VERSION 5.7 ;
  NOWIREEXTENSIONATPIN ON ;
  DIVIDERCHAR "/" ;
  BUSBITCHARS "[]" ;
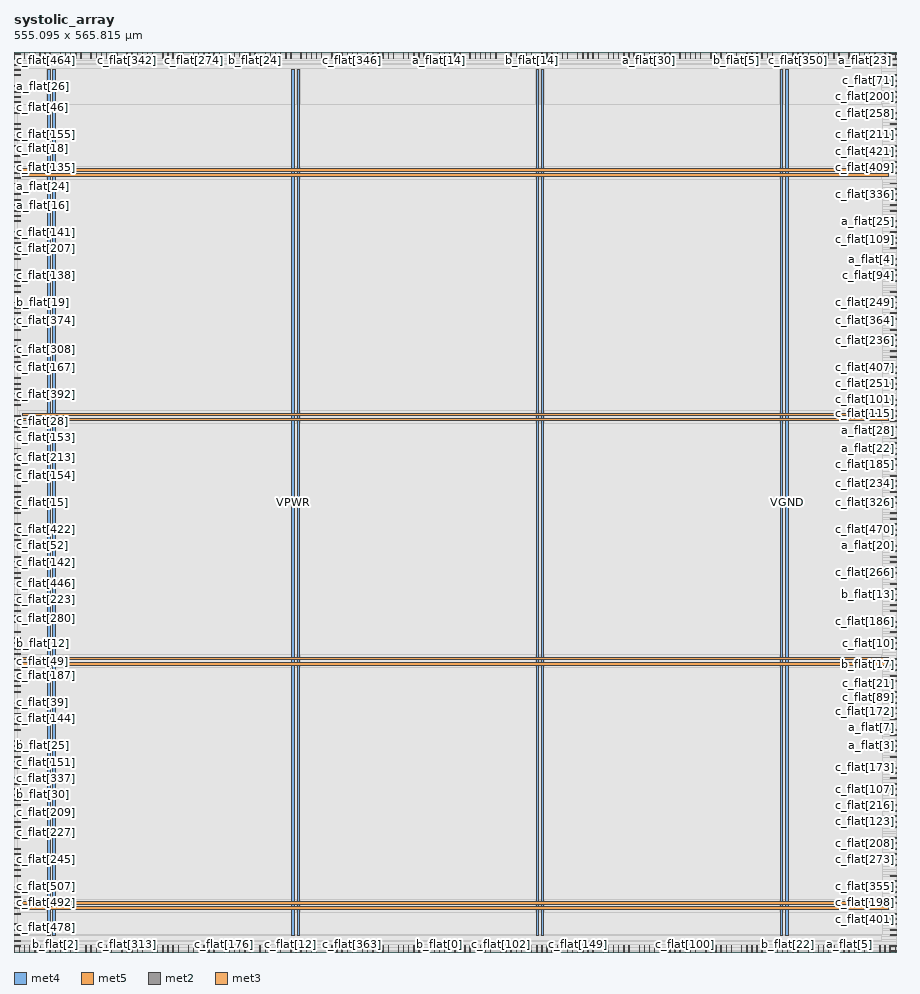
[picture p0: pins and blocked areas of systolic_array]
MACRO systolic_array
  CLASS BLOCK ;
  FOREIGN systolic_array ;
  ORIGIN 0.000 0.000 ;
  SIZE 555.095 BY 565.815 ;
  PIN VGND
    DIRECTION INOUT ;
    USE GROUND ;
    PORT
      LAYER met4 ;
        RECT 24.340 10.640 25.940 555.120 ;
    END
    PORT
      LAYER met4 ;
        RECT 177.940 10.640 179.540 555.120 ;
    END
    PORT
      LAYER met4 ;
        RECT 331.540 10.640 333.140 555.120 ;
    END
    PORT
      LAYER met4 ;
        RECT 485.140 10.640 486.740 555.120 ;
    END
    PORT
      LAYER met5 ;
        RECT 5.280 30.030 549.480 31.630 ;
    END
    PORT
      LAYER met5 ;
        RECT 5.280 183.630 549.480 185.230 ;
    END
    PORT
      LAYER met5 ;
        RECT 5.280 337.230 549.480 338.830 ;
    END
    PORT
      LAYER met5 ;
        RECT 5.280 490.830 549.480 492.430 ;
    END
  END VGND
  PIN VPWR
    DIRECTION INOUT ;
    USE POWER ;
    PORT
      LAYER met4 ;
        RECT 21.040 10.640 22.640 555.120 ;
    END
    PORT
      LAYER met4 ;
        RECT 174.640 10.640 176.240 555.120 ;
    END
    PORT
      LAYER met4 ;
        RECT 328.240 10.640 329.840 555.120 ;
    END
    PORT
      LAYER met4 ;
        RECT 481.840 10.640 483.440 555.120 ;
    END
    PORT
      LAYER met5 ;
        RECT 5.280 26.730 549.480 28.330 ;
    END
    PORT
      LAYER met5 ;
        RECT 5.280 180.330 549.480 181.930 ;
    END
    PORT
      LAYER met5 ;
        RECT 5.280 333.930 549.480 335.530 ;
    END
    PORT
      LAYER met5 ;
        RECT 5.280 487.530 549.480 489.130 ;
    END
  END VPWR
  PIN a_flat[0]
    DIRECTION INPUT ;
    USE SIGNAL ;
    ANTENNAGATEAREA 0.860700 ;
    ANTENNADIFFAREA 0.434700 ;
    PORT
      LAYER met2 ;
        RECT 228.710 0.000 228.990 4.000 ;
    END
  END a_flat[0]
  PIN a_flat[10]
    DIRECTION INPUT ;
    USE SIGNAL ;
    ANTENNAGATEAREA 0.647700 ;
    ANTENNADIFFAREA 0.434700 ;
    PORT
      LAYER met3 ;
        RECT 0.000 95.240 4.000 95.840 ;
    END
  END a_flat[10]
  PIN a_flat[11]
    DIRECTION INPUT ;
    USE SIGNAL ;
    ANTENNAGATEAREA 0.682200 ;
    ANTENNADIFFAREA 0.434700 ;
    PORT
      LAYER met3 ;
        RECT 551.095 319.640 555.095 320.240 ;
    END
  END a_flat[11]
  PIN a_flat[12]
    DIRECTION INPUT ;
    USE SIGNAL ;
    ANTENNAGATEAREA 0.682200 ;
    ANTENNADIFFAREA 0.434700 ;
    PORT
      LAYER met2 ;
        RECT 383.270 0.000 383.550 4.000 ;
    END
  END a_flat[12]
  PIN a_flat[13]
    DIRECTION INPUT ;
    USE SIGNAL ;
    ANTENNAGATEAREA 0.631200 ;
    ANTENNADIFFAREA 0.434700 ;
    PORT
      LAYER met2 ;
        RECT 238.370 561.815 238.650 565.815 ;
    END
  END a_flat[13]
  PIN a_flat[14]
    DIRECTION INPUT ;
    USE SIGNAL ;
    ANTENNAGATEAREA 0.631200 ;
    ANTENNADIFFAREA 0.434700 ;
    PORT
      LAYER met2 ;
        RECT 267.350 561.815 267.630 565.815 ;
    END
  END a_flat[14]
  PIN a_flat[15]
    DIRECTION INPUT ;
    USE SIGNAL ;
    ANTENNAGATEAREA 0.647700 ;
    ANTENNADIFFAREA 0.434700 ;
    PORT
      LAYER met3 ;
        RECT 551.095 353.640 555.095 354.240 ;
    END
  END a_flat[15]
  PIN a_flat[16]
    DIRECTION INPUT ;
    USE SIGNAL ;
    ANTENNAGATEAREA 0.593700 ;
    ANTENNADIFFAREA 0.434700 ;
    PORT
      LAYER met3 ;
        RECT 0.000 469.240 4.000 469.840 ;
    END
  END a_flat[16]
  PIN a_flat[17]
    DIRECTION INPUT ;
    USE SIGNAL ;
    ANTENNAGATEAREA 0.631200 ;
    ANTENNADIFFAREA 0.434700 ;
    PORT
      LAYER met2 ;
        RECT 409.030 561.815 409.310 565.815 ;
    END
  END a_flat[17]
  PIN a_flat[18]
    DIRECTION INPUT ;
    USE SIGNAL ;
    ANTENNAGATEAREA 0.647700 ;
    ANTENNADIFFAREA 0.434700 ;
    PORT
      LAYER met3 ;
        RECT 551.095 561.040 555.095 561.640 ;
    END
  END a_flat[18]
  PIN a_flat[19]
    DIRECTION INPUT ;
    USE SIGNAL ;
    ANTENNAGATEAREA 0.631200 ;
    ANTENNADIFFAREA 0.434700 ;
    PORT
      LAYER met3 ;
        RECT 551.095 448.840 555.095 449.440 ;
    END
  END a_flat[19]
  PIN a_flat[1]
    DIRECTION INPUT ;
    USE SIGNAL ;
    ANTENNAGATEAREA 0.647700 ;
    ANTENNADIFFAREA 0.434700 ;
    PORT
      LAYER met3 ;
        RECT 551.095 550.840 555.095 551.440 ;
    END
  END a_flat[1]
  PIN a_flat[20]
    DIRECTION INPUT ;
    USE SIGNAL ;
    ANTENNAGATEAREA 0.631200 ;
    ANTENNADIFFAREA 0.434700 ;
    PORT
      LAYER met3 ;
        RECT 551.095 255.040 555.095 255.640 ;
    END
  END a_flat[20]
  PIN a_flat[21]
    DIRECTION INPUT ;
    USE SIGNAL ;
    ANTENNAGATEAREA 0.647700 ;
    ANTENNADIFFAREA 0.434700 ;
    PORT
      LAYER met2 ;
        RECT 489.530 561.815 489.810 565.815 ;
    END
  END a_flat[21]
  PIN a_flat[22]
    DIRECTION INPUT ;
    USE SIGNAL ;
    ANTENNAGATEAREA 0.631200 ;
    ANTENNADIFFAREA 0.434700 ;
    PORT
      LAYER met3 ;
        RECT 551.095 316.240 555.095 316.840 ;
    END
  END a_flat[22]
  PIN a_flat[23]
    DIRECTION INPUT ;
    USE SIGNAL ;
    ANTENNAGATEAREA 0.647700 ;
    ANTENNADIFFAREA 0.434700 ;
    PORT
      LAYER met2 ;
        RECT 534.610 561.815 534.890 565.815 ;
    END
  END a_flat[23]
  PIN a_flat[24]
    DIRECTION INPUT ;
    USE SIGNAL ;
    ANTENNAGATEAREA 0.593700 ;
    ANTENNADIFFAREA 0.434700 ;
    PORT
      LAYER met3 ;
        RECT 0.000 476.040 4.000 476.640 ;
    END
  END a_flat[24]
  PIN a_flat[25]
    DIRECTION INPUT ;
    USE SIGNAL ;
    ANTENNAGATEAREA 0.647700 ;
    ANTENNADIFFAREA 0.434700 ;
    PORT
      LAYER met3 ;
        RECT 551.095 459.040 555.095 459.640 ;
    END
  END a_flat[25]
  PIN a_flat[26]
    DIRECTION INPUT ;
    USE SIGNAL ;
    ANTENNAGATEAREA 0.593700 ;
    ANTENNADIFFAREA 0.434700 ;
    PORT
      LAYER met3 ;
        RECT 0.000 544.040 4.000 544.640 ;
    END
  END a_flat[26]
  PIN a_flat[27]
    DIRECTION INPUT ;
    USE SIGNAL ;
    ANTENNAGATEAREA 0.647700 ;
    ANTENNADIFFAREA 0.434700 ;
    PORT
      LAYER met2 ;
        RECT 235.150 561.815 235.430 565.815 ;
    END
  END a_flat[27]
  PIN a_flat[28]
    DIRECTION INPUT ;
    USE SIGNAL ;
    ANTENNAGATEAREA 0.593700 ;
    ANTENNADIFFAREA 0.434700 ;
    PORT
      LAYER met3 ;
        RECT 551.095 323.040 555.095 323.640 ;
    END
  END a_flat[28]
  PIN a_flat[29]
    DIRECTION INPUT ;
    USE SIGNAL ;
    ANTENNAGATEAREA 0.647700 ;
    ANTENNADIFFAREA 0.434700 ;
    PORT
      LAYER met3 ;
        RECT 0.000 292.440 4.000 293.040 ;
    END
  END a_flat[29]
  PIN a_flat[2]
    DIRECTION INPUT ;
    USE SIGNAL ;
    ANTENNAGATEAREA 0.929700 ;
    ANTENNADIFFAREA 0.434700 ;
    PORT
      LAYER met3 ;
        RECT 0.000 3.440 4.000 4.040 ;
    END
  END a_flat[2]
  PIN a_flat[30]
    DIRECTION INPUT ;
    USE SIGNAL ;
    ANTENNAGATEAREA 0.647700 ;
    ANTENNADIFFAREA 0.434700 ;
    PORT
      LAYER met2 ;
        RECT 399.370 561.815 399.650 565.815 ;
    END
  END a_flat[30]
  PIN a_flat[31]
    DIRECTION INPUT ;
    USE SIGNAL ;
    ANTENNAGATEAREA 0.593700 ;
    ANTENNADIFFAREA 0.434700 ;
    PORT
      LAYER met3 ;
        RECT 0.000 489.640 4.000 490.240 ;
    END
  END a_flat[31]
  PIN a_flat[3]
    DIRECTION INPUT ;
    USE SIGNAL ;
    ANTENNAGATEAREA 0.929700 ;
    ANTENNADIFFAREA 0.434700 ;
    PORT
      LAYER met3 ;
        RECT 551.095 129.240 555.095 129.840 ;
    END
  END a_flat[3]
  PIN a_flat[4]
    DIRECTION INPUT ;
    USE SIGNAL ;
    ANTENNAGATEAREA 0.647700 ;
    ANTENNADIFFAREA 0.434700 ;
    PORT
      LAYER met3 ;
        RECT 551.095 435.240 555.095 435.840 ;
    END
  END a_flat[4]
  PIN a_flat[5]
    DIRECTION INPUT ;
    USE SIGNAL ;
    ANTENNAGATEAREA 0.929700 ;
    ANTENNADIFFAREA 0.434700 ;
    PORT
      LAYER met2 ;
        RECT 524.950 0.000 525.230 4.000 ;
    END
  END a_flat[5]
  PIN a_flat[6]
    DIRECTION INPUT ;
    USE SIGNAL ;
    ANTENNAGATEAREA 0.682200 ;
    ANTENNADIFFAREA 0.434700 ;
    PORT
      LAYER met2 ;
        RECT 99.910 561.815 100.190 565.815 ;
    END
  END a_flat[6]
  PIN a_flat[7]
    DIRECTION INPUT ;
    USE SIGNAL ;
    ANTENNAGATEAREA 0.682200 ;
    ANTENNADIFFAREA 0.434700 ;
    PORT
      LAYER met3 ;
        RECT 551.095 136.040 555.095 136.640 ;
    END
  END a_flat[7]
  PIN a_flat[8]
    DIRECTION INPUT ;
    USE SIGNAL ;
    ANTENNAGATEAREA 0.860700 ;
    ANTENNADIFFAREA 0.434700 ;
    PORT
      LAYER met2 ;
        RECT 444.450 0.000 444.730 4.000 ;
    END
  END a_flat[8]
  PIN a_flat[9]
    DIRECTION INPUT ;
    USE SIGNAL ;
    ANTENNAGATEAREA 0.647700 ;
    ANTENNADIFFAREA 0.434700 ;
    PORT
      LAYER met2 ;
        RECT 322.090 561.815 322.370 565.815 ;
    END
  END a_flat[9]
  PIN b_flat[0]
    DIRECTION INPUT ;
    USE SIGNAL ;
    ANTENNAGATEAREA 0.682200 ;
    ANTENNADIFFAREA 0.434700 ;
    PORT
      LAYER met2 ;
        RECT 267.350 0.000 267.630 4.000 ;
    END
  END b_flat[0]
  PIN b_flat[10]
    DIRECTION INPUT ;
    USE SIGNAL ;
    ANTENNAGATEAREA 0.647700 ;
    ANTENNADIFFAREA 0.434700 ;
    PORT
      LAYER met3 ;
        RECT 551.095 479.440 555.095 480.040 ;
    END
  END b_flat[10]
  PIN b_flat[11]
    DIRECTION INPUT ;
    USE SIGNAL ;
    ANTENNAGATEAREA 0.631200 ;
    ANTENNADIFFAREA 0.434700 ;
    PORT
      LAYER met2 ;
        RECT 386.490 561.815 386.770 565.815 ;
    END
  END b_flat[11]
  PIN b_flat[12]
    DIRECTION INPUT ;
    USE SIGNAL ;
    ANTENNAGATEAREA 0.682200 ;
    ANTENNADIFFAREA 0.434700 ;
    PORT
      LAYER met3 ;
        RECT 0.000 193.840 4.000 194.440 ;
    END
  END b_flat[12]
  PIN b_flat[13]
    DIRECTION INPUT ;
    USE SIGNAL ;
    ANTENNAGATEAREA 0.647700 ;
    ANTENNADIFFAREA 0.434700 ;
    PORT
      LAYER met3 ;
        RECT 551.095 224.440 555.095 225.040 ;
    END
  END b_flat[13]
  PIN b_flat[14]
    DIRECTION INPUT ;
    USE SIGNAL ;
    ANTENNAGATEAREA 0.631200 ;
    ANTENNADIFFAREA 0.434700 ;
    PORT
      LAYER met2 ;
        RECT 325.310 561.815 325.590 565.815 ;
    END
  END b_flat[14]
  PIN b_flat[15]
    DIRECTION INPUT ;
    USE SIGNAL ;
    ANTENNAGATEAREA 0.560700 ;
    ANTENNADIFFAREA 0.434700 ;
    PORT
      LAYER met2 ;
        RECT 550.710 561.815 550.990 565.815 ;
    END
  END b_flat[15]
  PIN b_flat[16]
    DIRECTION INPUT ;
    USE SIGNAL ;
    ANTENNAGATEAREA 0.647700 ;
    ANTENNADIFFAREA 0.434700 ;
    PORT
      LAYER met2 ;
        RECT 222.270 561.815 222.550 565.815 ;
    END
  END b_flat[16]
  PIN b_flat[17]
    DIRECTION INPUT ;
    USE SIGNAL ;
    ANTENNAGATEAREA 0.647700 ;
    ANTENNADIFFAREA 0.434700 ;
    PORT
      LAYER met3 ;
        RECT 551.095 180.240 555.095 180.840 ;
    END
  END b_flat[17]
  PIN b_flat[18]
    DIRECTION INPUT ;
    USE SIGNAL ;
    ANTENNAGATEAREA 0.682200 ;
    ANTENNADIFFAREA 0.434700 ;
    PORT
      LAYER met2 ;
        RECT 270.570 0.000 270.850 4.000 ;
    END
  END b_flat[18]
  PIN b_flat[19]
    DIRECTION INPUT ;
    USE SIGNAL ;
    ANTENNAGATEAREA 0.682200 ;
    ANTENNADIFFAREA 0.434700 ;
    PORT
      LAYER met3 ;
        RECT 0.000 408.040 4.000 408.640 ;
    END
  END b_flat[19]
  PIN b_flat[1]
    DIRECTION INPUT ;
    USE SIGNAL ;
    ANTENNAGATEAREA 0.682200 ;
    ANTENNADIFFAREA 0.434700 ;
    PORT
      LAYER met2 ;
        RECT 186.850 0.000 187.130 4.000 ;
    END
  END b_flat[1]
  PIN b_flat[20]
    DIRECTION INPUT ;
    USE SIGNAL ;
    ANTENNAGATEAREA 0.593700 ;
    ANTENNADIFFAREA 0.434700 ;
    PORT
      LAYER met2 ;
        RECT 483.090 0.000 483.370 4.000 ;
    END
  END b_flat[20]
  PIN b_flat[21]
    DIRECTION INPUT ;
    USE SIGNAL ;
    ANTENNAGATEAREA 0.682200 ;
    ANTENNADIFFAREA 0.434700 ;
    PORT
      LAYER met2 ;
        RECT 74.150 561.815 74.430 565.815 ;
    END
  END b_flat[21]
  PIN b_flat[22]
    DIRECTION INPUT ;
    USE SIGNAL ;
    ANTENNAGATEAREA 0.682200 ;
    ANTENNADIFFAREA 0.434700 ;
    PORT
      LAYER met2 ;
        RECT 486.310 0.000 486.590 4.000 ;
    END
  END b_flat[22]
  PIN b_flat[23]
    DIRECTION INPUT ;
    USE SIGNAL ;
    ANTENNAGATEAREA 0.593700 ;
    ANTENNADIFFAREA 0.434700 ;
    PORT
      LAYER met2 ;
        RECT 148.210 0.000 148.490 4.000 ;
    END
  END b_flat[23]
  PIN b_flat[24]
    DIRECTION INPUT ;
    USE SIGNAL ;
    ANTENNAGATEAREA 0.647700 ;
    ANTENNADIFFAREA 0.434700 ;
    PORT
      LAYER met2 ;
        RECT 151.430 561.815 151.710 565.815 ;
    END
  END b_flat[24]
  PIN b_flat[25]
    DIRECTION INPUT ;
    USE SIGNAL ;
    ANTENNAGATEAREA 0.593700 ;
    ANTENNADIFFAREA 0.434700 ;
    PORT
      LAYER met3 ;
        RECT 0.000 129.240 4.000 129.840 ;
    END
  END b_flat[25]
  PIN b_flat[26]
    DIRECTION INPUT ;
    USE SIGNAL ;
    ANTENNAGATEAREA 0.647700 ;
    ANTENNADIFFAREA 0.434700 ;
    PORT
      LAYER met2 ;
        RECT 164.310 0.000 164.590 4.000 ;
    END
  END b_flat[26]
  PIN b_flat[27]
    DIRECTION INPUT ;
    USE SIGNAL ;
    ANTENNAGATEAREA 0.647700 ;
    ANTENNADIFFAREA 0.434700 ;
    PORT
      LAYER met2 ;
        RECT 186.850 561.815 187.130 565.815 ;
    END
  END b_flat[27]
  PIN b_flat[28]
    DIRECTION INPUT ;
    USE SIGNAL ;
    ANTENNAGATEAREA 0.560700 ;
    ANTENNADIFFAREA 0.434700 ;
    PORT
      LAYER met2 ;
        RECT 289.890 561.815 290.170 565.815 ;
    END
  END b_flat[28]
  PIN b_flat[29]
    DIRECTION INPUT ;
    USE SIGNAL ;
    ANTENNAGATEAREA 0.682200 ;
    ANTENNADIFFAREA 0.434700 ;
    PORT
      LAYER met2 ;
        RECT 48.390 0.000 48.670 4.000 ;
    END
  END b_flat[29]
  PIN b_flat[2]
    DIRECTION INPUT ;
    USE SIGNAL ;
    ANTENNAGATEAREA 1.177200 ;
    ANTENNADIFFAREA 0.434700 ;
    PORT
      LAYER met2 ;
        RECT 25.850 0.000 26.130 4.000 ;
    END
  END b_flat[2]
  PIN b_flat[30]
    DIRECTION INPUT ;
    USE SIGNAL ;
    ANTENNAGATEAREA 0.682200 ;
    ANTENNADIFFAREA 0.434700 ;
    PORT
      LAYER met3 ;
        RECT 0.000 98.640 4.000 99.240 ;
    END
  END b_flat[30]
  PIN b_flat[31]
    DIRECTION INPUT ;
    USE SIGNAL ;
    ANTENNAGATEAREA 0.682200 ;
    ANTENNADIFFAREA 0.434700 ;
    PORT
      LAYER met3 ;
        RECT 0.000 47.640 4.000 48.240 ;
    END
  END b_flat[31]
  PIN b_flat[3]
    DIRECTION INPUT ;
    USE SIGNAL ;
    ANTENNAGATEAREA 1.177200 ;
    ANTENNADIFFAREA 0.434700 ;
    PORT
      LAYER met2 ;
        RECT 521.730 0.000 522.010 4.000 ;
    END
  END b_flat[3]
  PIN b_flat[4]
    DIRECTION INPUT ;
    USE SIGNAL ;
    ANTENNAGATEAREA 0.647700 ;
    ANTENNADIFFAREA 0.434700 ;
    PORT
      LAYER met2 ;
        RECT 270.570 561.815 270.850 565.815 ;
    END
  END b_flat[4]
  PIN b_flat[5]
    DIRECTION INPUT ;
    USE SIGNAL ;
    ANTENNAGATEAREA 0.647700 ;
    ANTENNADIFFAREA 0.434700 ;
    PORT
      LAYER met2 ;
        RECT 454.110 561.815 454.390 565.815 ;
    END
  END b_flat[5]
  PIN b_flat[6]
    DIRECTION INPUT ;
    USE SIGNAL ;
    ANTENNAGATEAREA 0.682200 ;
    ANTENNADIFFAREA 0.434700 ;
    PORT
      LAYER met2 ;
        RECT 16.190 0.000 16.470 4.000 ;
    END
  END b_flat[6]
  PIN b_flat[7]
    DIRECTION INPUT ;
    USE SIGNAL ;
    ANTENNAGATEAREA 0.647700 ;
    ANTENNADIFFAREA 0.434700 ;
    PORT
      LAYER met2 ;
        RECT 450.890 561.815 451.170 565.815 ;
    END
  END b_flat[7]
  PIN b_flat[8]
    DIRECTION INPUT ;
    USE SIGNAL ;
    ANTENNAGATEAREA 0.593700 ;
    ANTENNADIFFAREA 0.434700 ;
    PORT
      LAYER met3 ;
        RECT 551.095 285.640 555.095 286.240 ;
    END
  END b_flat[8]
  PIN b_flat[9]
    DIRECTION INPUT ;
    USE SIGNAL ;
    ANTENNAGATEAREA 0.647700 ;
    ANTENNADIFFAREA 0.434700 ;
    PORT
      LAYER met2 ;
        RECT 222.270 0.000 222.550 4.000 ;
    END
  END b_flat[9]
  PIN c_flat[0]
    DIRECTION OUTPUT TRISTATE ;
    USE SIGNAL ;
    ANTENNADIFFAREA 0.445500 ;
    PORT
      LAYER met3 ;
        RECT 551.095 360.440 555.095 361.040 ;
    END
  END c_flat[0]
  PIN c_flat[100]
    DIRECTION OUTPUT TRISTATE ;
    USE SIGNAL ;
    ANTENNADIFFAREA 0.795200 ;
    PORT
      LAYER met2 ;
        RECT 421.910 0.000 422.190 4.000 ;
    END
  END c_flat[100]
  PIN c_flat[101]
    DIRECTION OUTPUT TRISTATE ;
    USE SIGNAL ;
    ANTENNADIFFAREA 0.795200 ;
    PORT
      LAYER met3 ;
        RECT 551.095 346.840 555.095 347.440 ;
    END
  END c_flat[101]
  PIN c_flat[102]
    DIRECTION OUTPUT TRISTATE ;
    USE SIGNAL ;
    ANTENNADIFFAREA 0.795200 ;
    PORT
      LAYER met2 ;
        RECT 305.990 0.000 306.270 4.000 ;
    END
  END c_flat[102]
  PIN c_flat[103]
    DIRECTION OUTPUT TRISTATE ;
    USE SIGNAL ;
    ANTENNADIFFAREA 0.795200 ;
    PORT
      LAYER met2 ;
        RECT 141.770 0.000 142.050 4.000 ;
    END
  END c_flat[103]
  PIN c_flat[104]
    DIRECTION OUTPUT TRISTATE ;
    USE SIGNAL ;
    ANTENNADIFFAREA 0.795200 ;
    PORT
      LAYER met2 ;
        RECT 248.030 561.815 248.310 565.815 ;
    END
  END c_flat[104]
  PIN c_flat[105]
    DIRECTION OUTPUT TRISTATE ;
    USE SIGNAL ;
    ANTENNADIFFAREA 0.795200 ;
    PORT
      LAYER met2 ;
        RECT 505.630 0.000 505.910 4.000 ;
    END
  END c_flat[105]
  PIN c_flat[106]
    DIRECTION OUTPUT TRISTATE ;
    USE SIGNAL ;
    ANTENNADIFFAREA 0.795200 ;
    PORT
      LAYER met2 ;
        RECT 418.690 0.000 418.970 4.000 ;
    END
  END c_flat[106]
  PIN c_flat[107]
    DIRECTION OUTPUT TRISTATE ;
    USE SIGNAL ;
    ANTENNADIFFAREA 0.795200 ;
    PORT
      LAYER met3 ;
        RECT 551.095 102.040 555.095 102.640 ;
    END
  END c_flat[107]
  PIN c_flat[108]
    DIRECTION OUTPUT TRISTATE ;
    USE SIGNAL ;
    ANTENNADIFFAREA 0.445500 ;
    PORT
      LAYER met2 ;
        RECT 251.250 561.815 251.530 565.815 ;
    END
  END c_flat[108]
  PIN c_flat[109]
    DIRECTION OUTPUT TRISTATE ;
    USE SIGNAL ;
    ANTENNADIFFAREA 0.445500 ;
    PORT
      LAYER met3 ;
        RECT 551.095 452.240 555.095 452.840 ;
    END
  END c_flat[109]
  PIN c_flat[10]
    DIRECTION OUTPUT TRISTATE ;
    USE SIGNAL ;
    ANTENNADIFFAREA 0.445500 ;
    PORT
      LAYER met3 ;
        RECT 551.095 193.840 555.095 194.440 ;
    END
  END c_flat[10]
  PIN c_flat[110]
    DIRECTION OUTPUT TRISTATE ;
    USE SIGNAL ;
    ANTENNADIFFAREA 0.445500 ;
    PORT
      LAYER met3 ;
        RECT 551.095 489.640 555.095 490.240 ;
    END
  END c_flat[110]
  PIN c_flat[111]
    DIRECTION OUTPUT TRISTATE ;
    USE SIGNAL ;
    ANTENNADIFFAREA 0.795200 ;
    PORT
      LAYER met2 ;
        RECT 544.270 0.000 544.550 4.000 ;
    END
  END c_flat[111]
  PIN c_flat[112]
    DIRECTION OUTPUT TRISTATE ;
    USE SIGNAL ;
    ANTENNADIFFAREA 0.795200 ;
    PORT
      LAYER met2 ;
        RECT 87.030 0.000 87.310 4.000 ;
    END
  END c_flat[112]
  PIN c_flat[113]
    DIRECTION OUTPUT TRISTATE ;
    USE SIGNAL ;
    ANTENNADIFFAREA 0.795200 ;
    PORT
      LAYER met2 ;
        RECT 12.970 561.815 13.250 565.815 ;
    END
  END c_flat[113]
  PIN c_flat[114]
    DIRECTION OUTPUT TRISTATE ;
    USE SIGNAL ;
    ANTENNADIFFAREA 0.795200 ;
    PORT
      LAYER met3 ;
        RECT 0.000 428.440 4.000 429.040 ;
    END
  END c_flat[114]
  PIN c_flat[115]
    DIRECTION OUTPUT TRISTATE ;
    USE SIGNAL ;
    ANTENNADIFFAREA 0.445500 ;
    PORT
      LAYER met3 ;
        RECT 551.095 333.240 555.095 333.840 ;
    END
  END c_flat[115]
  PIN c_flat[116]
    DIRECTION OUTPUT TRISTATE ;
    USE SIGNAL ;
    ANTENNADIFFAREA 0.795200 ;
    PORT
      LAYER met2 ;
        RECT 29.070 561.815 29.350 565.815 ;
    END
  END c_flat[116]
  PIN c_flat[117]
    DIRECTION OUTPUT TRISTATE ;
    USE SIGNAL ;
    ANTENNADIFFAREA 0.445500 ;
    PORT
      LAYER met2 ;
        RECT 106.350 561.815 106.630 565.815 ;
    END
  END c_flat[117]
  PIN c_flat[118]
    DIRECTION OUTPUT TRISTATE ;
    USE SIGNAL ;
    ANTENNADIFFAREA 0.445500 ;
    PORT
      LAYER met2 ;
        RECT 161.090 561.815 161.370 565.815 ;
    END
  END c_flat[118]
  PIN c_flat[119]
    DIRECTION OUTPUT TRISTATE ;
    USE SIGNAL ;
    ANTENNADIFFAREA 0.795200 ;
    PORT
      LAYER met2 ;
        RECT 537.830 561.815 538.110 565.815 ;
    END
  END c_flat[119]
  PIN c_flat[11]
    DIRECTION OUTPUT TRISTATE ;
    USE SIGNAL ;
    ANTENNADIFFAREA 0.445500 ;
    PORT
      LAYER met3 ;
        RECT 551.095 397.840 555.095 398.440 ;
    END
  END c_flat[11]
  PIN c_flat[120]
    DIRECTION OUTPUT TRISTATE ;
    USE SIGNAL ;
    ANTENNADIFFAREA 0.795200 ;
    PORT
      LAYER met2 ;
        RECT 109.570 0.000 109.850 4.000 ;
    END
  END c_flat[120]
  PIN c_flat[121]
    DIRECTION OUTPUT TRISTATE ;
    USE SIGNAL ;
    ANTENNADIFFAREA 0.795200 ;
    PORT
      LAYER met2 ;
        RECT 553.930 561.815 554.210 565.815 ;
    END
  END c_flat[121]
  PIN c_flat[122]
    DIRECTION OUTPUT TRISTATE ;
    USE SIGNAL ;
    ANTENNADIFFAREA 0.795200 ;
    PORT
      LAYER met2 ;
        RECT 19.410 561.815 19.690 565.815 ;
    END
  END c_flat[122]
  PIN c_flat[123]
    DIRECTION OUTPUT TRISTATE ;
    USE SIGNAL ;
    ANTENNADIFFAREA 0.445500 ;
    PORT
      LAYER met3 ;
        RECT 551.095 81.640 555.095 82.240 ;
    END
  END c_flat[123]
  PIN c_flat[124]
    DIRECTION OUTPUT TRISTATE ;
    USE SIGNAL ;
    ANTENNADIFFAREA 0.795200 ;
    PORT
      LAYER met3 ;
        RECT 551.095 496.440 555.095 497.040 ;
    END
  END c_flat[124]
  PIN c_flat[125]
    DIRECTION OUTPUT TRISTATE ;
    USE SIGNAL ;
    ANTENNADIFFAREA 0.795200 ;
    PORT
      LAYER met2 ;
        RECT 489.530 0.000 489.810 4.000 ;
    END
  END c_flat[125]
  PIN c_flat[126]
    DIRECTION OUTPUT TRISTATE ;
    USE SIGNAL ;
    ANTENNADIFFAREA 0.795200 ;
    PORT
      LAYER met3 ;
        RECT 0.000 78.240 4.000 78.840 ;
    END
  END c_flat[126]
  PIN c_flat[127]
    DIRECTION OUTPUT TRISTATE ;
    USE SIGNAL ;
    ANTENNADIFFAREA 0.795200 ;
    PORT
      LAYER met3 ;
        RECT 0.000 510.040 4.000 510.640 ;
    END
  END c_flat[127]
  PIN c_flat[128]
    DIRECTION OUTPUT TRISTATE ;
    USE SIGNAL ;
    ANTENNADIFFAREA 0.795200 ;
    PORT
      LAYER met3 ;
        RECT 0.000 496.440 4.000 497.040 ;
    END
  END c_flat[128]
  PIN c_flat[129]
    DIRECTION OUTPUT TRISTATE ;
    USE SIGNAL ;
    ANTENNADIFFAREA 0.445500 ;
    PORT
      LAYER met2 ;
        RECT 119.230 561.815 119.510 565.815 ;
    END
  END c_flat[129]
  PIN c_flat[12]
    DIRECTION OUTPUT TRISTATE ;
    USE SIGNAL ;
    ANTENNADIFFAREA 0.795200 ;
    PORT
      LAYER met2 ;
        RECT 173.970 0.000 174.250 4.000 ;
    END
  END c_flat[12]
  PIN c_flat[130]
    DIRECTION OUTPUT TRISTATE ;
    USE SIGNAL ;
    ANTENNADIFFAREA 0.795200 ;
    PORT
      LAYER met2 ;
        RECT 351.070 0.000 351.350 4.000 ;
    END
  END c_flat[130]
  PIN c_flat[131]
    DIRECTION OUTPUT TRISTATE ;
    USE SIGNAL ;
    ANTENNADIFFAREA 0.445500 ;
    PORT
      LAYER met2 ;
        RECT 486.310 561.815 486.590 565.815 ;
    END
  END c_flat[131]
  PIN c_flat[132]
    DIRECTION OUTPUT TRISTATE ;
    USE SIGNAL ;
    ANTENNADIFFAREA 0.795200 ;
    PORT
      LAYER met3 ;
        RECT 0.000 336.640 4.000 337.240 ;
    END
  END c_flat[132]
  PIN c_flat[133]
    DIRECTION OUTPUT TRISTATE ;
    USE SIGNAL ;
    ANTENNADIFFAREA 0.795200 ;
    PORT
      LAYER met2 ;
        RECT 12.970 0.000 13.250 4.000 ;
    END
  END c_flat[133]
  PIN c_flat[134]
    DIRECTION OUTPUT TRISTATE ;
    USE SIGNAL ;
    ANTENNADIFFAREA 0.795200 ;
    PORT
      LAYER met2 ;
        RECT 231.930 561.815 232.210 565.815 ;
    END
  END c_flat[134]
  PIN c_flat[135]
    DIRECTION OUTPUT TRISTATE ;
    USE SIGNAL ;
    ANTENNADIFFAREA 0.795200 ;
    PORT
      LAYER met3 ;
        RECT 0.000 493.040 4.000 493.640 ;
    END
  END c_flat[135]
  PIN c_flat[136]
    DIRECTION OUTPUT TRISTATE ;
    USE SIGNAL ;
    ANTENNADIFFAREA 0.445500 ;
    PORT
      LAYER met3 ;
        RECT 551.095 329.840 555.095 330.440 ;
    END
  END c_flat[136]
  PIN c_flat[137]
    DIRECTION OUTPUT TRISTATE ;
    USE SIGNAL ;
    ANTENNADIFFAREA 0.445500 ;
    PORT
      LAYER met3 ;
        RECT 551.095 387.640 555.095 388.240 ;
    END
  END c_flat[137]
  PIN c_flat[138]
    DIRECTION OUTPUT TRISTATE ;
    USE SIGNAL ;
    ANTENNADIFFAREA 0.795200 ;
    PORT
      LAYER met3 ;
        RECT 0.000 425.040 4.000 425.640 ;
    END
  END c_flat[138]
  PIN c_flat[139]
    DIRECTION OUTPUT TRISTATE ;
    USE SIGNAL ;
    ANTENNADIFFAREA 0.445500 ;
    PORT
      LAYER met2 ;
        RECT 438.010 561.815 438.290 565.815 ;
    END
  END c_flat[139]
  PIN c_flat[13]
    DIRECTION OUTPUT TRISTATE ;
    USE SIGNAL ;
    ANTENNADIFFAREA 0.795200 ;
    PORT
      LAYER met2 ;
        RECT 228.710 561.815 228.990 565.815 ;
    END
  END c_flat[13]
  PIN c_flat[140]
    DIRECTION OUTPUT TRISTATE ;
    USE SIGNAL ;
    ANTENNADIFFAREA 0.795200 ;
    PORT
      LAYER met3 ;
        RECT 551.095 275.440 555.095 276.040 ;
    END
  END c_flat[140]
  PIN c_flat[141]
    DIRECTION OUTPUT TRISTATE ;
    USE SIGNAL ;
    ANTENNADIFFAREA 0.795200 ;
    PORT
      LAYER met3 ;
        RECT 0.000 452.240 4.000 452.840 ;
    END
  END c_flat[141]
  PIN c_flat[142]
    DIRECTION OUTPUT TRISTATE ;
    USE SIGNAL ;
    ANTENNADIFFAREA 0.795200 ;
    PORT
      LAYER met3 ;
        RECT 0.000 244.840 4.000 245.440 ;
    END
  END c_flat[142]
  PIN c_flat[143]
    DIRECTION OUTPUT TRISTATE ;
    USE SIGNAL ;
    ANTENNADIFFAREA 0.795200 ;
    PORT
      LAYER met2 ;
        RECT 206.170 0.000 206.450 4.000 ;
    END
  END c_flat[143]
  PIN c_flat[144]
    DIRECTION OUTPUT TRISTATE ;
    USE SIGNAL ;
    ANTENNADIFFAREA 0.795200 ;
    PORT
      LAYER met3 ;
        RECT 0.000 146.240 4.000 146.840 ;
    END
  END c_flat[144]
  PIN c_flat[145]
    DIRECTION OUTPUT TRISTATE ;
    USE SIGNAL ;
    ANTENNADIFFAREA 0.795200 ;
    PORT
      LAYER met3 ;
        RECT 0.000 61.240 4.000 61.840 ;
    END
  END c_flat[145]
  PIN c_flat[146]
    DIRECTION OUTPUT TRISTATE ;
    USE SIGNAL ;
    ANTENNADIFFAREA 0.795200 ;
    PORT
      LAYER met3 ;
        RECT 0.000 241.440 4.000 242.040 ;
    END
  END c_flat[146]
  PIN c_flat[147]
    DIRECTION OUTPUT TRISTATE ;
    USE SIGNAL ;
    ANTENNADIFFAREA 0.795200 ;
    PORT
      LAYER met2 ;
        RECT 219.050 0.000 219.330 4.000 ;
    END
  END c_flat[147]
  PIN c_flat[148]
    DIRECTION OUTPUT TRISTATE ;
    USE SIGNAL ;
    ANTENNADIFFAREA 0.795200 ;
    PORT
      LAYER met2 ;
        RECT 376.830 561.815 377.110 565.815 ;
    END
  END c_flat[148]
  PIN c_flat[149]
    DIRECTION OUTPUT TRISTATE ;
    USE SIGNAL ;
    ANTENNADIFFAREA 0.795200 ;
    PORT
      LAYER met2 ;
        RECT 354.290 0.000 354.570 4.000 ;
    END
  END c_flat[149]
  PIN c_flat[14]
    DIRECTION OUTPUT TRISTATE ;
    USE SIGNAL ;
    ANTENNADIFFAREA 0.795200 ;
    PORT
      LAYER met2 ;
        RECT 164.310 561.815 164.590 565.815 ;
    END
  END c_flat[14]
  PIN c_flat[150]
    DIRECTION OUTPUT TRISTATE ;
    USE SIGNAL ;
    ANTENNADIFFAREA 0.795200 ;
    PORT
      LAYER met2 ;
        RECT 363.950 561.815 364.230 565.815 ;
    END
  END c_flat[150]
  PIN c_flat[151]
    DIRECTION OUTPUT TRISTATE ;
    USE SIGNAL ;
    ANTENNADIFFAREA 0.795200 ;
    PORT
      LAYER met3 ;
        RECT 0.000 119.040 4.000 119.640 ;
    END
  END c_flat[151]
  PIN c_flat[152]
    DIRECTION OUTPUT TRISTATE ;
    USE SIGNAL ;
    ANTENNADIFFAREA 0.795200 ;
    PORT
      LAYER met3 ;
        RECT 551.095 183.640 555.095 184.240 ;
    END
  END c_flat[152]
  PIN c_flat[153]
    DIRECTION OUTPUT TRISTATE ;
    USE SIGNAL ;
    ANTENNADIFFAREA 0.795200 ;
    PORT
      LAYER met3 ;
        RECT 0.000 323.040 4.000 323.640 ;
    END
  END c_flat[153]
  PIN c_flat[154]
    DIRECTION OUTPUT TRISTATE ;
    USE SIGNAL ;
    ANTENNADIFFAREA 0.795200 ;
    PORT
      LAYER met3 ;
        RECT 0.000 299.240 4.000 299.840 ;
    END
  END c_flat[154]
  PIN c_flat[155]
    DIRECTION OUTPUT TRISTATE ;
    USE SIGNAL ;
    ANTENNADIFFAREA 0.795200 ;
    PORT
      LAYER met3 ;
        RECT 0.000 513.440 4.000 514.040 ;
    END
  END c_flat[155]
  PIN c_flat[156]
    DIRECTION OUTPUT TRISTATE ;
    USE SIGNAL ;
    ANTENNADIFFAREA 0.795200 ;
    PORT
      LAYER met3 ;
        RECT 0.000 183.640 4.000 184.240 ;
    END
  END c_flat[156]
  PIN c_flat[157]
    DIRECTION OUTPUT TRISTATE ;
    USE SIGNAL ;
    ANTENNADIFFAREA 0.445500 ;
    PORT
      LAYER met2 ;
        RECT 312.430 561.815 312.710 565.815 ;
    END
  END c_flat[157]
  PIN c_flat[158]
    DIRECTION OUTPUT TRISTATE ;
    USE SIGNAL ;
    ANTENNADIFFAREA 0.795200 ;
    PORT
      LAYER met2 ;
        RECT 48.390 561.815 48.670 565.815 ;
    END
  END c_flat[158]
  PIN c_flat[159]
    DIRECTION OUTPUT TRISTATE ;
    USE SIGNAL ;
    ANTENNADIFFAREA 0.795200 ;
    PORT
      LAYER met3 ;
        RECT 0.000 51.040 4.000 51.640 ;
    END
  END c_flat[159]
  PIN c_flat[15]
    DIRECTION OUTPUT TRISTATE ;
    USE SIGNAL ;
    ANTENNADIFFAREA 0.795200 ;
    PORT
      LAYER met3 ;
        RECT 0.000 282.240 4.000 282.840 ;
    END
  END c_flat[15]
  PIN c_flat[160]
    DIRECTION OUTPUT TRISTATE ;
    USE SIGNAL ;
    ANTENNADIFFAREA 0.795200 ;
    PORT
      LAYER met2 ;
        RECT 280.230 561.815 280.510 565.815 ;
    END
  END c_flat[160]
  PIN c_flat[161]
    DIRECTION OUTPUT TRISTATE ;
    USE SIGNAL ;
    ANTENNADIFFAREA 0.795200 ;
    PORT
      LAYER met2 ;
        RECT 441.230 561.815 441.510 565.815 ;
    END
  END c_flat[161]
  PIN c_flat[162]
    DIRECTION OUTPUT TRISTATE ;
    USE SIGNAL ;
    ANTENNADIFFAREA 0.795200 ;
    PORT
      LAYER met2 ;
        RECT 254.470 0.000 254.750 4.000 ;
    END
  END c_flat[162]
  PIN c_flat[163]
    DIRECTION OUTPUT TRISTATE ;
    USE SIGNAL ;
    ANTENNADIFFAREA 0.795200 ;
    PORT
      LAYER met3 ;
        RECT 0.000 149.640 4.000 150.240 ;
    END
  END c_flat[163]
  PIN c_flat[164]
    DIRECTION OUTPUT TRISTATE ;
    USE SIGNAL ;
    ANTENNADIFFAREA 0.445500 ;
    PORT
      LAYER met3 ;
        RECT 551.095 251.640 555.095 252.240 ;
    END
  END c_flat[164]
  PIN c_flat[165]
    DIRECTION OUTPUT TRISTATE ;
    USE SIGNAL ;
    ANTENNADIFFAREA 0.795200 ;
    PORT
      LAYER met2 ;
        RECT 289.890 0.000 290.170 4.000 ;
    END
  END c_flat[165]
  PIN c_flat[166]
    DIRECTION OUTPUT TRISTATE ;
    USE SIGNAL ;
    ANTENNADIFFAREA 0.445500 ;
    PORT
      LAYER met2 ;
        RECT 202.950 561.815 203.230 565.815 ;
    END
  END c_flat[166]
  PIN c_flat[167]
    DIRECTION OUTPUT TRISTATE ;
    USE SIGNAL ;
    ANTENNADIFFAREA 0.795200 ;
    PORT
      LAYER met3 ;
        RECT 0.000 367.240 4.000 367.840 ;
    END
  END c_flat[167]
  PIN c_flat[168]
    DIRECTION OUTPUT TRISTATE ;
    USE SIGNAL ;
    ANTENNADIFFAREA 0.795200 ;
    PORT
      LAYER met3 ;
        RECT 0.000 380.840 4.000 381.440 ;
    END
  END c_flat[168]
  PIN c_flat[169]
    DIRECTION OUTPUT TRISTATE ;
    USE SIGNAL ;
    ANTENNADIFFAREA 0.445500 ;
    PORT
      LAYER met2 ;
        RECT 383.270 561.815 383.550 565.815 ;
    END
  END c_flat[169]
  PIN c_flat[16]
    DIRECTION OUTPUT TRISTATE ;
    USE SIGNAL ;
    ANTENNADIFFAREA 0.445500 ;
    PORT
      LAYER met3 ;
        RECT 551.095 221.040 555.095 221.640 ;
    END
  END c_flat[16]
  PIN c_flat[170]
    DIRECTION OUTPUT TRISTATE ;
    USE SIGNAL ;
    ANTENNADIFFAREA 0.795200 ;
    PORT
      LAYER met2 ;
        RECT 170.750 561.815 171.030 565.815 ;
    END
  END c_flat[170]
  PIN c_flat[171]
    DIRECTION OUTPUT TRISTATE ;
    USE SIGNAL ;
    ANTENNADIFFAREA 0.795200 ;
    PORT
      LAYER met3 ;
        RECT 551.095 340.040 555.095 340.640 ;
    END
  END c_flat[171]
  PIN c_flat[172]
    DIRECTION OUTPUT TRISTATE ;
    USE SIGNAL ;
    ANTENNADIFFAREA 0.445500 ;
    PORT
      LAYER met3 ;
        RECT 551.095 146.240 555.095 146.840 ;
    END
  END c_flat[172]
  PIN c_flat[173]
    DIRECTION OUTPUT TRISTATE ;
    USE SIGNAL ;
    ANTENNADIFFAREA 0.445500 ;
    PORT
      LAYER met3 ;
        RECT 551.095 115.640 555.095 116.240 ;
    END
  END c_flat[173]
  PIN c_flat[174]
    DIRECTION OUTPUT TRISTATE ;
    USE SIGNAL ;
    ANTENNADIFFAREA 0.795200 ;
    PORT
      LAYER met2 ;
        RECT 476.650 561.815 476.930 565.815 ;
    END
  END c_flat[174]
  PIN c_flat[175]
    DIRECTION OUTPUT TRISTATE ;
    USE SIGNAL ;
    ANTENNADIFFAREA 0.445500 ;
    PORT
      LAYER met3 ;
        RECT 551.095 132.640 555.095 133.240 ;
    END
  END c_flat[175]
  PIN c_flat[176]
    DIRECTION OUTPUT TRISTATE ;
    USE SIGNAL ;
    ANTENNADIFFAREA 0.795200 ;
    PORT
      LAYER met2 ;
        RECT 132.110 0.000 132.390 4.000 ;
    END
  END c_flat[176]
  PIN c_flat[177]
    DIRECTION OUTPUT TRISTATE ;
    USE SIGNAL ;
    ANTENNADIFFAREA 0.445500 ;
    PORT
      LAYER met2 ;
        RECT 431.570 561.815 431.850 565.815 ;
    END
  END c_flat[177]
  PIN c_flat[178]
    DIRECTION OUTPUT TRISTATE ;
    USE SIGNAL ;
    ANTENNADIFFAREA 0.445500 ;
    PORT
      LAYER met3 ;
        RECT 551.095 428.440 555.095 429.040 ;
    END
  END c_flat[178]
  PIN c_flat[179]
    DIRECTION OUTPUT TRISTATE ;
    USE SIGNAL ;
    ANTENNADIFFAREA 0.445500 ;
    PORT
      LAYER met2 ;
        RECT 93.470 561.815 93.750 565.815 ;
    END
  END c_flat[179]
  PIN c_flat[17]
    DIRECTION OUTPUT TRISTATE ;
    USE SIGNAL ;
    ANTENNADIFFAREA 0.795200 ;
    PORT
      LAYER met2 ;
        RECT 125.670 0.000 125.950 4.000 ;
    END
  END c_flat[17]
  PIN c_flat[180]
    DIRECTION OUTPUT TRISTATE ;
    USE SIGNAL ;
    ANTENNADIFFAREA 0.445500 ;
    PORT
      LAYER met2 ;
        RECT 141.770 561.815 142.050 565.815 ;
    END
  END c_flat[180]
  PIN c_flat[181]
    DIRECTION OUTPUT TRISTATE ;
    USE SIGNAL ;
    ANTENNADIFFAREA 0.445500 ;
    PORT
      LAYER met2 ;
        RECT 341.410 561.815 341.690 565.815 ;
    END
  END c_flat[181]
  PIN c_flat[182]
    DIRECTION OUTPUT TRISTATE ;
    USE SIGNAL ;
    ANTENNADIFFAREA 0.795200 ;
    PORT
      LAYER met2 ;
        RECT 260.910 0.000 261.190 4.000 ;
    END
  END c_flat[182]
  PIN c_flat[183]
    DIRECTION OUTPUT TRISTATE ;
    USE SIGNAL ;
    ANTENNADIFFAREA 0.795200 ;
    PORT
      LAYER met2 ;
        RECT 405.810 0.000 406.090 4.000 ;
    END
  END c_flat[183]
  PIN c_flat[184]
    DIRECTION OUTPUT TRISTATE ;
    USE SIGNAL ;
    ANTENNADIFFAREA 0.795200 ;
    PORT
      LAYER met2 ;
        RECT 524.950 561.815 525.230 565.815 ;
    END
  END c_flat[184]
  PIN c_flat[185]
    DIRECTION OUTPUT TRISTATE ;
    USE SIGNAL ;
    ANTENNADIFFAREA 0.445500 ;
    PORT
      LAYER met3 ;
        RECT 551.095 306.040 555.095 306.640 ;
    END
  END c_flat[185]
  PIN c_flat[186]
    DIRECTION OUTPUT TRISTATE ;
    USE SIGNAL ;
    ANTENNADIFFAREA 0.795200 ;
    PORT
      LAYER met3 ;
        RECT 551.095 207.440 555.095 208.040 ;
    END
  END c_flat[186]
  PIN c_flat[187]
    DIRECTION OUTPUT TRISTATE ;
    USE SIGNAL ;
    ANTENNADIFFAREA 0.795200 ;
    PORT
      LAYER met3 ;
        RECT 0.000 173.440 4.000 174.040 ;
    END
  END c_flat[187]
  PIN c_flat[188]
    DIRECTION OUTPUT TRISTATE ;
    USE SIGNAL ;
    ANTENNADIFFAREA 0.445500 ;
    PORT
      LAYER met2 ;
        RECT 293.110 561.815 293.390 565.815 ;
    END
  END c_flat[188]
  PIN c_flat[189]
    DIRECTION OUTPUT TRISTATE ;
    USE SIGNAL ;
    ANTENNADIFFAREA 0.795200 ;
    PORT
      LAYER met2 ;
        RECT 412.250 561.815 412.530 565.815 ;
    END
  END c_flat[189]
  PIN c_flat[18]
    DIRECTION OUTPUT TRISTATE ;
    USE SIGNAL ;
    ANTENNADIFFAREA 0.795200 ;
    PORT
      LAYER met3 ;
        RECT 0.000 499.840 4.000 500.440 ;
    END
  END c_flat[18]
  PIN c_flat[190]
    DIRECTION OUTPUT TRISTATE ;
    USE SIGNAL ;
    ANTENNADIFFAREA 0.795200 ;
    PORT
      LAYER met3 ;
        RECT 0.000 285.640 4.000 286.240 ;
    END
  END c_flat[190]
  PIN c_flat[191]
    DIRECTION OUTPUT TRISTATE ;
    USE SIGNAL ;
    ANTENNADIFFAREA 0.445500 ;
    PORT
      LAYER met3 ;
        RECT 551.095 312.840 555.095 313.440 ;
    END
  END c_flat[191]
  PIN c_flat[192]
    DIRECTION OUTPUT TRISTATE ;
    USE SIGNAL ;
    ANTENNADIFFAREA 0.795200 ;
    PORT
      LAYER met2 ;
        RECT 58.050 0.000 58.330 4.000 ;
    END
  END c_flat[192]
  PIN c_flat[193]
    DIRECTION OUTPUT TRISTATE ;
    USE SIGNAL ;
    ANTENNADIFFAREA 0.445500 ;
    PORT
      LAYER met3 ;
        RECT 551.095 455.640 555.095 456.240 ;
    END
  END c_flat[193]
  PIN c_flat[194]
    DIRECTION OUTPUT TRISTATE ;
    USE SIGNAL ;
    ANTENNADIFFAREA 0.795200 ;
    PORT
      LAYER met2 ;
        RECT 3.310 0.000 3.590 4.000 ;
    END
  END c_flat[194]
  PIN c_flat[195]
    DIRECTION OUTPUT TRISTATE ;
    USE SIGNAL ;
    ANTENNADIFFAREA 0.795200 ;
    PORT
      LAYER met3 ;
        RECT 0.000 360.440 4.000 361.040 ;
    END
  END c_flat[195]
  PIN c_flat[196]
    DIRECTION OUTPUT TRISTATE ;
    USE SIGNAL ;
    ANTENNADIFFAREA 0.795200 ;
    PORT
      LAYER met2 ;
        RECT 386.490 0.000 386.770 4.000 ;
    END
  END c_flat[196]
  PIN c_flat[197]
    DIRECTION OUTPUT TRISTATE ;
    USE SIGNAL ;
    ANTENNADIFFAREA 0.445500 ;
    PORT
      LAYER met2 ;
        RECT 38.730 561.815 39.010 565.815 ;
    END
  END c_flat[197]
  PIN c_flat[198]
    DIRECTION OUTPUT TRISTATE ;
    USE SIGNAL ;
    ANTENNADIFFAREA 0.445500 ;
    PORT
      LAYER met3 ;
        RECT 551.095 30.640 555.095 31.240 ;
    END
  END c_flat[198]
  PIN c_flat[199]
    DIRECTION OUTPUT TRISTATE ;
    USE SIGNAL ;
    ANTENNADIFFAREA 0.795200 ;
    PORT
      LAYER met2 ;
        RECT 512.070 0.000 512.350 4.000 ;
    END
  END c_flat[199]
  PIN c_flat[19]
    DIRECTION OUTPUT TRISTATE ;
    USE SIGNAL ;
    ANTENNADIFFAREA 0.795200 ;
    PORT
      LAYER met2 ;
        RECT 103.130 0.000 103.410 4.000 ;
    END
  END c_flat[19]
  PIN c_flat[1]
    DIRECTION OUTPUT TRISTATE ;
    USE SIGNAL ;
    ANTENNADIFFAREA 0.445500 ;
    PORT
      LAYER met2 ;
        RECT 64.490 561.815 64.770 565.815 ;
    END
  END c_flat[1]
  PIN c_flat[200]
    DIRECTION OUTPUT TRISTATE ;
    USE SIGNAL ;
    ANTENNADIFFAREA 0.795200 ;
    PORT
      LAYER met3 ;
        RECT 551.095 537.240 555.095 537.840 ;
    END
  END c_flat[200]
  PIN c_flat[201]
    DIRECTION OUTPUT TRISTATE ;
    USE SIGNAL ;
    ANTENNADIFFAREA 0.795200 ;
    PORT
      LAYER met2 ;
        RECT 54.830 561.815 55.110 565.815 ;
    END
  END c_flat[201]
  PIN c_flat[202]
    DIRECTION OUTPUT TRISTATE ;
    USE SIGNAL ;
    ANTENNADIFFAREA 0.795200 ;
    PORT
      LAYER met2 ;
        RECT 421.910 561.815 422.190 565.815 ;
    END
  END c_flat[202]
  PIN c_flat[203]
    DIRECTION OUTPUT TRISTATE ;
    USE SIGNAL ;
    ANTENNADIFFAREA 0.795200 ;
    PORT
      LAYER met3 ;
        RECT 0.000 486.240 4.000 486.840 ;
    END
  END c_flat[203]
  PIN c_flat[204]
    DIRECTION OUTPUT TRISTATE ;
    USE SIGNAL ;
    ANTENNADIFFAREA 0.795200 ;
    PORT
      LAYER met2 ;
        RECT 531.390 0.000 531.670 4.000 ;
    END
  END c_flat[204]
  PIN c_flat[205]
    DIRECTION OUTPUT TRISTATE ;
    USE SIGNAL ;
    ANTENNADIFFAREA 0.445500 ;
    PORT
      LAYER met2 ;
        RECT 528.170 561.815 528.450 565.815 ;
    END
  END c_flat[205]
  PIN c_flat[206]
    DIRECTION OUTPUT TRISTATE ;
    USE SIGNAL ;
    ANTENNADIFFAREA 0.445500 ;
    PORT
      LAYER met3 ;
        RECT 551.095 431.840 555.095 432.440 ;
    END
  END c_flat[206]
  PIN c_flat[207]
    DIRECTION OUTPUT TRISTATE ;
    USE SIGNAL ;
    ANTENNADIFFAREA 0.795200 ;
    PORT
      LAYER met3 ;
        RECT 0.000 442.040 4.000 442.640 ;
    END
  END c_flat[207]
  PIN c_flat[208]
    DIRECTION OUTPUT TRISTATE ;
    USE SIGNAL ;
    ANTENNADIFFAREA 0.795200 ;
    PORT
      LAYER met3 ;
        RECT 551.095 68.040 555.095 68.640 ;
    END
  END c_flat[208]
  PIN c_flat[209]
    DIRECTION OUTPUT TRISTATE ;
    USE SIGNAL ;
    ANTENNADIFFAREA 0.795200 ;
    PORT
      LAYER met3 ;
        RECT 0.000 91.840 4.000 92.440 ;
    END
  END c_flat[209]
  PIN c_flat[20]
    DIRECTION OUTPUT TRISTATE ;
    USE SIGNAL ;
    ANTENNADIFFAREA 0.795200 ;
    PORT
      LAYER met3 ;
        RECT 0.000 377.440 4.000 378.040 ;
    END
  END c_flat[20]
  PIN c_flat[210]
    DIRECTION OUTPUT TRISTATE ;
    USE SIGNAL ;
    ANTENNADIFFAREA 0.795200 ;
    PORT
      LAYER met2 ;
        RECT 492.750 0.000 493.030 4.000 ;
    END
  END c_flat[210]
  PIN c_flat[211]
    DIRECTION OUTPUT TRISTATE ;
    USE SIGNAL ;
    ANTENNADIFFAREA 0.445500 ;
    PORT
      LAYER met3 ;
        RECT 551.095 513.440 555.095 514.040 ;
    END
  END c_flat[211]
  PIN c_flat[212]
    DIRECTION OUTPUT TRISTATE ;
    USE SIGNAL ;
    ANTENNADIFFAREA 0.795200 ;
    PORT
      LAYER met3 ;
        RECT 0.000 268.640 4.000 269.240 ;
    END
  END c_flat[212]
  PIN c_flat[213]
    DIRECTION OUTPUT TRISTATE ;
    USE SIGNAL ;
    ANTENNADIFFAREA 0.795200 ;
    PORT
      LAYER met3 ;
        RECT 0.000 306.040 4.000 306.640 ;
    END
  END c_flat[213]
  PIN c_flat[214]
    DIRECTION OUTPUT TRISTATE ;
    USE SIGNAL ;
    ANTENNADIFFAREA 0.795200 ;
    PORT
      LAYER met3 ;
        RECT 0.000 462.440 4.000 463.040 ;
    END
  END c_flat[214]
  PIN c_flat[215]
    DIRECTION OUTPUT TRISTATE ;
    USE SIGNAL ;
    ANTENNADIFFAREA 0.795200 ;
    PORT
      LAYER met3 ;
        RECT 0.000 326.440 4.000 327.040 ;
    END
  END c_flat[215]
  PIN c_flat[216]
    DIRECTION OUTPUT TRISTATE ;
    USE SIGNAL ;
    ANTENNADIFFAREA 0.445500 ;
    PORT
      LAYER met3 ;
        RECT 551.095 91.840 555.095 92.440 ;
    END
  END c_flat[216]
  PIN c_flat[217]
    DIRECTION OUTPUT TRISTATE ;
    USE SIGNAL ;
    ANTENNADIFFAREA 0.445500 ;
    PORT
      LAYER met3 ;
        RECT 551.095 108.840 555.095 109.440 ;
    END
  END c_flat[217]
  PIN c_flat[218]
    DIRECTION OUTPUT TRISTATE ;
    USE SIGNAL ;
    ANTENNADIFFAREA 0.795200 ;
    PORT
      LAYER met2 ;
        RECT 412.250 0.000 412.530 4.000 ;
    END
  END c_flat[218]
  PIN c_flat[219]
    DIRECTION OUTPUT TRISTATE ;
    USE SIGNAL ;
    ANTENNADIFFAREA 0.795200 ;
    PORT
      LAYER met3 ;
        RECT 551.095 516.840 555.095 517.440 ;
    END
  END c_flat[219]
  PIN c_flat[21]
    DIRECTION OUTPUT TRISTATE ;
    USE SIGNAL ;
    ANTENNADIFFAREA 0.445500 ;
    PORT
      LAYER met3 ;
        RECT 551.095 173.440 555.095 174.040 ;
    END
  END c_flat[21]
  PIN c_flat[220]
    DIRECTION OUTPUT TRISTATE ;
    USE SIGNAL ;
    ANTENNADIFFAREA 0.795200 ;
    PORT
      LAYER met2 ;
        RECT 67.710 0.000 67.990 4.000 ;
    END
  END c_flat[220]
  PIN c_flat[221]
    DIRECTION OUTPUT TRISTATE ;
    USE SIGNAL ;
    ANTENNADIFFAREA 0.445500 ;
    PORT
      LAYER met3 ;
        RECT 551.095 404.640 555.095 405.240 ;
    END
  END c_flat[221]
  PIN c_flat[222]
    DIRECTION OUTPUT TRISTATE ;
    USE SIGNAL ;
    ANTENNADIFFAREA 0.795200 ;
    PORT
      LAYER met3 ;
        RECT 0.000 17.040 4.000 17.640 ;
    END
  END c_flat[222]
  PIN c_flat[223]
    DIRECTION OUTPUT TRISTATE ;
    USE SIGNAL ;
    ANTENNADIFFAREA 0.795200 ;
    PORT
      LAYER met3 ;
        RECT 0.000 221.040 4.000 221.640 ;
    END
  END c_flat[223]
  PIN c_flat[224]
    DIRECTION OUTPUT TRISTATE ;
    USE SIGNAL ;
    ANTENNADIFFAREA 0.795200 ;
    PORT
      LAYER met2 ;
        RECT 402.590 0.000 402.870 4.000 ;
    END
  END c_flat[224]
  PIN c_flat[225]
    DIRECTION OUTPUT TRISTATE ;
    USE SIGNAL ;
    ANTENNADIFFAREA 0.795200 ;
    PORT
      LAYER met2 ;
        RECT 32.290 561.815 32.570 565.815 ;
    END
  END c_flat[225]
  PIN c_flat[226]
    DIRECTION OUTPUT TRISTATE ;
    USE SIGNAL ;
    ANTENNADIFFAREA 0.795200 ;
    PORT
      LAYER met2 ;
        RECT 425.130 0.000 425.410 4.000 ;
    END
  END c_flat[226]
  PIN c_flat[227]
    DIRECTION OUTPUT TRISTATE ;
    USE SIGNAL ;
    ANTENNADIFFAREA 0.795200 ;
    PORT
      LAYER met3 ;
        RECT 0.000 74.840 4.000 75.440 ;
    END
  END c_flat[227]
  PIN c_flat[228]
    DIRECTION OUTPUT TRISTATE ;
    USE SIGNAL ;
    ANTENNADIFFAREA 0.795200 ;
    PORT
      LAYER met3 ;
        RECT 0.000 346.840 4.000 347.440 ;
    END
  END c_flat[228]
  PIN c_flat[229]
    DIRECTION OUTPUT TRISTATE ;
    USE SIGNAL ;
    ANTENNADIFFAREA 0.445500 ;
    PORT
      LAYER met2 ;
        RECT 396.150 561.815 396.430 565.815 ;
    END
  END c_flat[229]
  PIN c_flat[22]
    DIRECTION OUTPUT TRISTATE ;
    USE SIGNAL ;
    ANTENNADIFFAREA 0.795200 ;
    PORT
      LAYER met2 ;
        RECT 83.810 561.815 84.090 565.815 ;
    END
  END c_flat[22]
  PIN c_flat[230]
    DIRECTION OUTPUT TRISTATE ;
    USE SIGNAL ;
    ANTENNADIFFAREA 0.795200 ;
    PORT
      LAYER met2 ;
        RECT 144.990 561.815 145.270 565.815 ;
    END
  END c_flat[230]
  PIN c_flat[231]
    DIRECTION OUTPUT TRISTATE ;
    USE SIGNAL ;
    ANTENNADIFFAREA 0.795200 ;
    PORT
      LAYER met2 ;
        RECT 202.950 0.000 203.230 4.000 ;
    END
  END c_flat[231]
  PIN c_flat[232]
    DIRECTION OUTPUT TRISTATE ;
    USE SIGNAL ;
    ANTENNADIFFAREA 0.795200 ;
    PORT
      LAYER met2 ;
        RECT 553.930 0.000 554.210 4.000 ;
    END
  END c_flat[232]
  PIN c_flat[233]
    DIRECTION OUTPUT TRISTATE ;
    USE SIGNAL ;
    ANTENNADIFFAREA 0.795200 ;
    PORT
      LAYER met3 ;
        RECT 0.000 200.640 4.000 201.240 ;
    END
  END c_flat[233]
  PIN c_flat[234]
    DIRECTION OUTPUT TRISTATE ;
    USE SIGNAL ;
    ANTENNADIFFAREA 0.445500 ;
    PORT
      LAYER met3 ;
        RECT 551.095 299.240 555.095 299.840 ;
    END
  END c_flat[234]
  PIN c_flat[235]
    DIRECTION OUTPUT TRISTATE ;
    USE SIGNAL ;
    ANTENNADIFFAREA 0.445500 ;
    PORT
      LAYER met3 ;
        RECT 551.095 200.640 555.095 201.240 ;
    END
  END c_flat[235]
  PIN c_flat[236]
    DIRECTION OUTPUT TRISTATE ;
    USE SIGNAL ;
    ANTENNADIFFAREA 0.445500 ;
    PORT
      LAYER met3 ;
        RECT 551.095 384.240 555.095 384.840 ;
    END
  END c_flat[236]
  PIN c_flat[237]
    DIRECTION OUTPUT TRISTATE ;
    USE SIGNAL ;
    ANTENNADIFFAREA 0.795200 ;
    PORT
      LAYER met3 ;
        RECT 0.000 234.640 4.000 235.240 ;
    END
  END c_flat[237]
  PIN c_flat[238]
    DIRECTION OUTPUT TRISTATE ;
    USE SIGNAL ;
    ANTENNADIFFAREA 0.795200 ;
    PORT
      LAYER met3 ;
        RECT 551.095 47.640 555.095 48.240 ;
    END
  END c_flat[238]
  PIN c_flat[239]
    DIRECTION OUTPUT TRISTATE ;
    USE SIGNAL ;
    ANTENNADIFFAREA 0.795200 ;
    PORT
      LAYER met2 ;
        RECT 116.010 561.815 116.290 565.815 ;
    END
  END c_flat[239]
  PIN c_flat[23]
    DIRECTION OUTPUT TRISTATE ;
    USE SIGNAL ;
    ANTENNADIFFAREA 0.795200 ;
    PORT
      LAYER met3 ;
        RECT 551.095 0.040 555.095 0.640 ;
    END
  END c_flat[23]
  PIN c_flat[240]
    DIRECTION OUTPUT TRISTATE ;
    USE SIGNAL ;
    ANTENNADIFFAREA 0.795200 ;
    PORT
      LAYER met2 ;
        RECT 112.790 0.000 113.070 4.000 ;
    END
  END c_flat[240]
  PIN c_flat[241]
    DIRECTION OUTPUT TRISTATE ;
    USE SIGNAL ;
    ANTENNADIFFAREA 0.445500 ;
    PORT
      LAYER met3 ;
        RECT 551.095 149.640 555.095 150.240 ;
    END
  END c_flat[241]
  PIN c_flat[242]
    DIRECTION OUTPUT TRISTATE ;
    USE SIGNAL ;
    ANTENNADIFFAREA 0.795200 ;
    PORT
      LAYER met2 ;
        RECT 77.370 561.815 77.650 565.815 ;
    END
  END c_flat[242]
  PIN c_flat[243]
    DIRECTION OUTPUT TRISTATE ;
    USE SIGNAL ;
    ANTENNADIFFAREA 0.795200 ;
    PORT
      LAYER met2 ;
        RECT 434.790 0.000 435.070 4.000 ;
    END
  END c_flat[243]
  PIN c_flat[244]
    DIRECTION OUTPUT TRISTATE ;
    USE SIGNAL ;
    ANTENNADIFFAREA 0.795200 ;
    PORT
      LAYER met2 ;
        RECT 328.530 0.000 328.810 4.000 ;
    END
  END c_flat[244]
  PIN c_flat[245]
    DIRECTION OUTPUT TRISTATE ;
    USE SIGNAL ;
    ANTENNADIFFAREA 0.795200 ;
    PORT
      LAYER met3 ;
        RECT 0.000 57.840 4.000 58.440 ;
    END
  END c_flat[245]
  PIN c_flat[246]
    DIRECTION OUTPUT TRISTATE ;
    USE SIGNAL ;
    ANTENNADIFFAREA 0.795200 ;
    PORT
      LAYER met3 ;
        RECT 0.000 176.840 4.000 177.440 ;
    END
  END c_flat[246]
  PIN c_flat[247]
    DIRECTION OUTPUT TRISTATE ;
    USE SIGNAL ;
    ANTENNADIFFAREA 0.445500 ;
    PORT
      LAYER met2 ;
        RECT 334.970 561.815 335.250 565.815 ;
    END
  END c_flat[247]
  PIN c_flat[248]
    DIRECTION OUTPUT TRISTATE ;
    USE SIGNAL ;
    ANTENNADIFFAREA 0.795200 ;
    PORT
      LAYER met2 ;
        RECT 193.290 561.815 193.570 565.815 ;
    END
  END c_flat[248]
  PIN c_flat[249]
    DIRECTION OUTPUT TRISTATE ;
    USE SIGNAL ;
    ANTENNADIFFAREA 0.445500 ;
    PORT
      LAYER met3 ;
        RECT 551.095 408.040 555.095 408.640 ;
    END
  END c_flat[249]
  PIN c_flat[24]
    DIRECTION OUTPUT TRISTATE ;
    USE SIGNAL ;
    ANTENNADIFFAREA 0.795200 ;
    PORT
      LAYER met3 ;
        RECT 0.000 217.640 4.000 218.240 ;
    END
  END c_flat[24]
  PIN c_flat[250]
    DIRECTION OUTPUT TRISTATE ;
    USE SIGNAL ;
    ANTENNADIFFAREA 0.795200 ;
    PORT
      LAYER met3 ;
        RECT 0.000 71.440 4.000 72.040 ;
    END
  END c_flat[250]
  PIN c_flat[251]
    DIRECTION OUTPUT TRISTATE ;
    USE SIGNAL ;
    ANTENNADIFFAREA 0.795200 ;
    PORT
      LAYER met3 ;
        RECT 551.095 357.040 555.095 357.640 ;
    END
  END c_flat[251]
  PIN c_flat[252]
    DIRECTION OUTPUT TRISTATE ;
    USE SIGNAL ;
    ANTENNADIFFAREA 0.445500 ;
    PORT
      LAYER met2 ;
        RECT 244.810 561.815 245.090 565.815 ;
    END
  END c_flat[252]
  PIN c_flat[253]
    DIRECTION OUTPUT TRISTATE ;
    USE SIGNAL ;
    ANTENNADIFFAREA 0.795200 ;
    PORT
      LAYER met3 ;
        RECT 0.000 309.440 4.000 310.040 ;
    END
  END c_flat[253]
  PIN c_flat[254]
    DIRECTION OUTPUT TRISTATE ;
    USE SIGNAL ;
    ANTENNADIFFAREA 0.445500 ;
    PORT
      LAYER met2 ;
        RECT 209.390 561.815 209.670 565.815 ;
    END
  END c_flat[254]
  PIN c_flat[255]
    DIRECTION OUTPUT TRISTATE ;
    USE SIGNAL ;
    ANTENNADIFFAREA 0.795200 ;
    PORT
      LAYER met3 ;
        RECT 0.000 142.840 4.000 143.440 ;
    END
  END c_flat[255]
  PIN c_flat[256]
    DIRECTION OUTPUT TRISTATE ;
    USE SIGNAL ;
    ANTENNADIFFAREA 0.795200 ;
    PORT
      LAYER met3 ;
        RECT 0.000 224.440 4.000 225.040 ;
    END
  END c_flat[256]
  PIN c_flat[257]
    DIRECTION OUTPUT TRISTATE ;
    USE SIGNAL ;
    ANTENNADIFFAREA 0.795200 ;
    PORT
      LAYER met3 ;
        RECT 0.000 37.440 4.000 38.040 ;
    END
  END c_flat[257]
  PIN c_flat[258]
    DIRECTION OUTPUT TRISTATE ;
    USE SIGNAL ;
    ANTENNADIFFAREA 0.445500 ;
    PORT
      LAYER met3 ;
        RECT 551.095 527.040 555.095 527.640 ;
    END
  END c_flat[258]
  PIN c_flat[259]
    DIRECTION OUTPUT TRISTATE ;
    USE SIGNAL ;
    ANTENNADIFFAREA 0.795200 ;
    PORT
      LAYER met2 ;
        RECT 534.610 0.000 534.890 4.000 ;
    END
  END c_flat[259]
  PIN c_flat[25]
    DIRECTION OUTPUT TRISTATE ;
    USE SIGNAL ;
    ANTENNADIFFAREA 0.795200 ;
    PORT
      LAYER met3 ;
        RECT 0.000 404.640 4.000 405.240 ;
    END
  END c_flat[25]
  PIN c_flat[260]
    DIRECTION OUTPUT TRISTATE ;
    USE SIGNAL ;
    ANTENNADIFFAREA 0.795200 ;
    PORT
      LAYER met3 ;
        RECT 0.000 435.240 4.000 435.840 ;
    END
  END c_flat[260]
  PIN c_flat[261]
    DIRECTION OUTPUT TRISTATE ;
    USE SIGNAL ;
    ANTENNADIFFAREA 0.445500 ;
    PORT
      LAYER met3 ;
        RECT 551.095 85.040 555.095 85.640 ;
    END
  END c_flat[261]
  PIN c_flat[262]
    DIRECTION OUTPUT TRISTATE ;
    USE SIGNAL ;
    ANTENNADIFFAREA 0.795200 ;
    PORT
      LAYER met2 ;
        RECT 167.530 0.000 167.810 4.000 ;
    END
  END c_flat[262]
  PIN c_flat[263]
    DIRECTION OUTPUT TRISTATE ;
    USE SIGNAL ;
    ANTENNADIFFAREA 0.795200 ;
    PORT
      LAYER met2 ;
        RECT 470.210 0.000 470.490 4.000 ;
    END
  END c_flat[263]
  PIN c_flat[264]
    DIRECTION OUTPUT TRISTATE ;
    USE SIGNAL ;
    ANTENNADIFFAREA 0.795200 ;
    PORT
      LAYER met2 ;
        RECT 296.330 0.000 296.610 4.000 ;
    END
  END c_flat[264]
  PIN c_flat[265]
    DIRECTION OUTPUT TRISTATE ;
    USE SIGNAL ;
    ANTENNADIFFAREA 0.445500 ;
    PORT
      LAYER met2 ;
        RECT 463.770 561.815 464.050 565.815 ;
    END
  END c_flat[265]
  PIN c_flat[266]
    DIRECTION OUTPUT TRISTATE ;
    USE SIGNAL ;
    ANTENNADIFFAREA 0.445500 ;
    PORT
      LAYER met3 ;
        RECT 551.095 238.040 555.095 238.640 ;
    END
  END c_flat[266]
  PIN c_flat[267]
    DIRECTION OUTPUT TRISTATE ;
    USE SIGNAL ;
    ANTENNADIFFAREA 0.795200 ;
    PORT
      LAYER met3 ;
        RECT 551.095 204.040 555.095 204.640 ;
    END
  END c_flat[267]
  PIN c_flat[268]
    DIRECTION OUTPUT TRISTATE ;
    USE SIGNAL ;
    ANTENNADIFFAREA 0.795200 ;
    PORT
      LAYER met2 ;
        RECT 80.590 0.000 80.870 4.000 ;
    END
  END c_flat[268]
  PIN c_flat[269]
    DIRECTION OUTPUT TRISTATE ;
    USE SIGNAL ;
    ANTENNADIFFAREA 0.445500 ;
    PORT
      LAYER met3 ;
        RECT 551.095 227.840 555.095 228.440 ;
    END
  END c_flat[269]
  PIN c_flat[26]
    DIRECTION OUTPUT TRISTATE ;
    USE SIGNAL ;
    ANTENNADIFFAREA 0.795200 ;
    PORT
      LAYER met2 ;
        RECT 508.850 0.000 509.130 4.000 ;
    END
  END c_flat[26]
  PIN c_flat[270]
    DIRECTION OUTPUT TRISTATE ;
    USE SIGNAL ;
    ANTENNADIFFAREA 0.795200 ;
    PORT
      LAYER met2 ;
        RECT 380.050 0.000 380.330 4.000 ;
    END
  END c_flat[270]
  PIN c_flat[271]
    DIRECTION OUTPUT TRISTATE ;
    USE SIGNAL ;
    ANTENNADIFFAREA 0.795200 ;
    PORT
      LAYER met3 ;
        RECT 0.000 506.640 4.000 507.240 ;
    END
  END c_flat[271]
  PIN c_flat[272]
    DIRECTION OUTPUT TRISTATE ;
    USE SIGNAL ;
    ANTENNADIFFAREA 0.445500 ;
    PORT
      LAYER met3 ;
        RECT 551.095 411.440 555.095 412.040 ;
    END
  END c_flat[272]
  PIN c_flat[273]
    DIRECTION OUTPUT TRISTATE ;
    USE SIGNAL ;
    ANTENNADIFFAREA 0.445500 ;
    PORT
      LAYER met3 ;
        RECT 551.095 57.840 555.095 58.440 ;
    END
  END c_flat[273]
  PIN c_flat[274]
    DIRECTION OUTPUT TRISTATE ;
    USE SIGNAL ;
    ANTENNADIFFAREA 0.445500 ;
    PORT
      LAYER met2 ;
        RECT 112.790 561.815 113.070 565.815 ;
    END
  END c_flat[274]
  PIN c_flat[275]
    DIRECTION OUTPUT TRISTATE ;
    USE SIGNAL ;
    ANTENNADIFFAREA 0.795200 ;
    PORT
      LAYER met2 ;
        RECT 357.510 0.000 357.790 4.000 ;
    END
  END c_flat[275]
  PIN c_flat[276]
    DIRECTION OUTPUT TRISTATE ;
    USE SIGNAL ;
    ANTENNADIFFAREA 0.795200 ;
    PORT
      LAYER met3 ;
        RECT 551.095 241.440 555.095 242.040 ;
    END
  END c_flat[276]
  PIN c_flat[277]
    DIRECTION OUTPUT TRISTATE ;
    USE SIGNAL ;
    ANTENNADIFFAREA 0.795200 ;
    PORT
      LAYER met3 ;
        RECT 551.095 170.040 555.095 170.640 ;
    END
  END c_flat[277]
  PIN c_flat[278]
    DIRECTION OUTPUT TRISTATE ;
    USE SIGNAL ;
    ANTENNADIFFAREA 0.795200 ;
    PORT
      LAYER met2 ;
        RECT 235.150 0.000 235.430 4.000 ;
    END
  END c_flat[278]
  PIN c_flat[279]
    DIRECTION OUTPUT TRISTATE ;
    USE SIGNAL ;
    ANTENNADIFFAREA 0.795200 ;
    PORT
      LAYER met3 ;
        RECT 0.000 418.240 4.000 418.840 ;
    END
  END c_flat[279]
  PIN c_flat[27]
    DIRECTION OUTPUT TRISTATE ;
    USE SIGNAL ;
    ANTENNADIFFAREA 0.795200 ;
    PORT
      LAYER met2 ;
        RECT 363.950 0.000 364.230 4.000 ;
    END
  END c_flat[27]
  PIN c_flat[280]
    DIRECTION OUTPUT TRISTATE ;
    USE SIGNAL ;
    ANTENNADIFFAREA 0.795200 ;
    PORT
      LAYER met3 ;
        RECT 0.000 214.240 4.000 214.840 ;
    END
  END c_flat[280]
  PIN c_flat[281]
    DIRECTION OUTPUT TRISTATE ;
    USE SIGNAL ;
    ANTENNADIFFAREA 0.795200 ;
    PORT
      LAYER met2 ;
        RECT 77.370 0.000 77.650 4.000 ;
    END
  END c_flat[281]
  PIN c_flat[282]
    DIRECTION OUTPUT TRISTATE ;
    USE SIGNAL ;
    ANTENNADIFFAREA 0.445500 ;
    PORT
      LAYER met3 ;
        RECT 551.095 125.840 555.095 126.440 ;
    END
  END c_flat[282]
  PIN c_flat[283]
    DIRECTION OUTPUT TRISTATE ;
    USE SIGNAL ;
    ANTENNADIFFAREA 0.795200 ;
    PORT
      LAYER met2 ;
        RECT 338.190 561.815 338.470 565.815 ;
    END
  END c_flat[283]
  PIN c_flat[284]
    DIRECTION OUTPUT TRISTATE ;
    USE SIGNAL ;
    ANTENNADIFFAREA 0.795200 ;
    PORT
      LAYER met2 ;
        RECT 244.810 0.000 245.090 4.000 ;
    END
  END c_flat[284]
  PIN c_flat[285]
    DIRECTION OUTPUT TRISTATE ;
    USE SIGNAL ;
    ANTENNADIFFAREA 0.795200 ;
    PORT
      LAYER met3 ;
        RECT 0.000 6.840 4.000 7.440 ;
    END
  END c_flat[285]
  PIN c_flat[286]
    DIRECTION OUTPUT TRISTATE ;
    USE SIGNAL ;
    ANTENNADIFFAREA 0.795200 ;
    PORT
      LAYER met3 ;
        RECT 0.000 207.440 4.000 208.040 ;
    END
  END c_flat[286]
  PIN c_flat[287]
    DIRECTION OUTPUT TRISTATE ;
    USE SIGNAL ;
    ANTENNADIFFAREA 0.795200 ;
    PORT
      LAYER met2 ;
        RECT 457.330 0.000 457.610 4.000 ;
    END
  END c_flat[287]
  PIN c_flat[288]
    DIRECTION OUTPUT TRISTATE ;
    USE SIGNAL ;
    ANTENNADIFFAREA 0.795200 ;
    PORT
      LAYER met2 ;
        RECT 447.670 561.815 447.950 565.815 ;
    END
  END c_flat[288]
  PIN c_flat[289]
    DIRECTION OUTPUT TRISTATE ;
    USE SIGNAL ;
    ANTENNADIFFAREA 0.795200 ;
    PORT
      LAYER met2 ;
        RECT 547.490 0.000 547.770 4.000 ;
    END
  END c_flat[289]
  PIN c_flat[28]
    DIRECTION OUTPUT TRISTATE ;
    USE SIGNAL ;
    ANTENNADIFFAREA 0.795200 ;
    PORT
      LAYER met3 ;
        RECT 0.000 333.240 4.000 333.840 ;
    END
  END c_flat[28]
  PIN c_flat[290]
    DIRECTION OUTPUT TRISTATE ;
    USE SIGNAL ;
    ANTENNADIFFAREA 0.795200 ;
    PORT
      LAYER met3 ;
        RECT 0.000 421.640 4.000 422.240 ;
    END
  END c_flat[290]
  PIN c_flat[291]
    DIRECTION OUTPUT TRISTATE ;
    USE SIGNAL ;
    ANTENNADIFFAREA 0.795200 ;
    PORT
      LAYER met2 ;
        RECT 248.030 0.000 248.310 4.000 ;
    END
  END c_flat[291]
  PIN c_flat[292]
    DIRECTION OUTPUT TRISTATE ;
    USE SIGNAL ;
    ANTENNADIFFAREA 0.445500 ;
    PORT
      LAYER met3 ;
        RECT 551.095 112.240 555.095 112.840 ;
    END
  END c_flat[292]
  PIN c_flat[293]
    DIRECTION OUTPUT TRISTATE ;
    USE SIGNAL ;
    ANTENNADIFFAREA 0.445500 ;
    PORT
      LAYER met3 ;
        RECT 551.095 421.640 555.095 422.240 ;
    END
  END c_flat[293]
  PIN c_flat[294]
    DIRECTION OUTPUT TRISTATE ;
    USE SIGNAL ;
    ANTENNADIFFAREA 0.795200 ;
    PORT
      LAYER met2 ;
        RECT 360.730 0.000 361.010 4.000 ;
    END
  END c_flat[294]
  PIN c_flat[295]
    DIRECTION OUTPUT TRISTATE ;
    USE SIGNAL ;
    ANTENNADIFFAREA 0.795200 ;
    PORT
      LAYER met2 ;
        RECT 293.110 0.000 293.390 4.000 ;
    END
  END c_flat[295]
  PIN c_flat[296]
    DIRECTION OUTPUT TRISTATE ;
    USE SIGNAL ;
    ANTENNADIFFAREA 0.795200 ;
    PORT
      LAYER met2 ;
        RECT 206.170 561.815 206.450 565.815 ;
    END
  END c_flat[296]
  PIN c_flat[297]
    DIRECTION OUTPUT TRISTATE ;
    USE SIGNAL ;
    ANTENNADIFFAREA 0.795200 ;
    PORT
      LAYER met2 ;
        RECT 51.610 0.000 51.890 4.000 ;
    END
  END c_flat[297]
  PIN c_flat[298]
    DIRECTION OUTPUT TRISTATE ;
    USE SIGNAL ;
    ANTENNADIFFAREA 0.795200 ;
    PORT
      LAYER met3 ;
        RECT 0.000 302.640 4.000 303.240 ;
    END
  END c_flat[298]
  PIN c_flat[299]
    DIRECTION OUTPUT TRISTATE ;
    USE SIGNAL ;
    ANTENNADIFFAREA 0.795200 ;
    PORT
      LAYER met3 ;
        RECT 0.000 27.240 4.000 27.840 ;
    END
  END c_flat[299]
  PIN c_flat[29]
    DIRECTION OUTPUT TRISTATE ;
    USE SIGNAL ;
    ANTENNADIFFAREA 0.795200 ;
    PORT
      LAYER met2 ;
        RECT 425.130 561.815 425.410 565.815 ;
    END
  END c_flat[29]
  PIN c_flat[2]
    DIRECTION OUTPUT TRISTATE ;
    USE SIGNAL ;
    ANTENNADIFFAREA 0.445500 ;
    PORT
      LAYER met3 ;
        RECT 551.095 105.440 555.095 106.040 ;
    END
  END c_flat[2]
  PIN c_flat[300]
    DIRECTION OUTPUT TRISTATE ;
    USE SIGNAL ;
    ANTENNADIFFAREA 0.795200 ;
    PORT
      LAYER met2 ;
        RECT 518.510 561.815 518.790 565.815 ;
    END
  END c_flat[300]
  PIN c_flat[301]
    DIRECTION OUTPUT TRISTATE ;
    USE SIGNAL ;
    ANTENNADIFFAREA 0.795200 ;
    PORT
      LAYER met2 ;
        RECT 35.510 0.000 35.790 4.000 ;
    END
  END c_flat[301]
  PIN c_flat[302]
    DIRECTION OUTPUT TRISTATE ;
    USE SIGNAL ;
    ANTENNADIFFAREA 0.795200 ;
    PORT
      LAYER met3 ;
        RECT 551.095 564.440 555.095 565.040 ;
    END
  END c_flat[302]
  PIN c_flat[303]
    DIRECTION OUTPUT TRISTATE ;
    USE SIGNAL ;
    ANTENNADIFFAREA 0.795200 ;
    PORT
      LAYER met2 ;
        RECT 309.210 0.000 309.490 4.000 ;
    END
  END c_flat[303]
  PIN c_flat[304]
    DIRECTION OUTPUT TRISTATE ;
    USE SIGNAL ;
    ANTENNADIFFAREA 0.795200 ;
    PORT
      LAYER met2 ;
        RECT 161.090 0.000 161.370 4.000 ;
    END
  END c_flat[304]
  PIN c_flat[305]
    DIRECTION OUTPUT TRISTATE ;
    USE SIGNAL ;
    ANTENNADIFFAREA 0.795200 ;
    PORT
      LAYER met3 ;
        RECT 0.000 394.440 4.000 395.040 ;
    END
  END c_flat[305]
  PIN c_flat[306]
    DIRECTION OUTPUT TRISTATE ;
    USE SIGNAL ;
    ANTENNADIFFAREA 0.445500 ;
    PORT
      LAYER met3 ;
        RECT 551.095 244.840 555.095 245.440 ;
    END
  END c_flat[306]
  PIN c_flat[307]
    DIRECTION OUTPUT TRISTATE ;
    USE SIGNAL ;
    ANTENNADIFFAREA 0.795200 ;
    PORT
      LAYER met2 ;
        RECT 550.710 0.000 550.990 4.000 ;
    END
  END c_flat[307]
  PIN c_flat[308]
    DIRECTION OUTPUT TRISTATE ;
    USE SIGNAL ;
    ANTENNADIFFAREA 0.795200 ;
    PORT
      LAYER met3 ;
        RECT 0.000 374.040 4.000 374.640 ;
    END
  END c_flat[308]
  PIN c_flat[309]
    DIRECTION OUTPUT TRISTATE ;
    USE SIGNAL ;
    ANTENNADIFFAREA 0.795200 ;
    PORT
      LAYER met3 ;
        RECT 0.000 170.040 4.000 170.640 ;
    END
  END c_flat[309]
  PIN c_flat[30]
    DIRECTION OUTPUT TRISTATE ;
    USE SIGNAL ;
    ANTENNADIFFAREA 0.795200 ;
    PORT
      LAYER met2 ;
        RECT 277.010 561.815 277.290 565.815 ;
    END
  END c_flat[30]
  PIN c_flat[310]
    DIRECTION OUTPUT TRISTATE ;
    USE SIGNAL ;
    ANTENNADIFFAREA 0.795200 ;
    PORT
      LAYER met3 ;
        RECT 0.000 278.840 4.000 279.440 ;
    END
  END c_flat[310]
  PIN c_flat[311]
    DIRECTION OUTPUT TRISTATE ;
    USE SIGNAL ;
    ANTENNADIFFAREA 0.795200 ;
    PORT
      LAYER met2 ;
        RECT 473.430 561.815 473.710 565.815 ;
    END
  END c_flat[311]
  PIN c_flat[312]
    DIRECTION OUTPUT TRISTATE ;
    USE SIGNAL ;
    ANTENNADIFFAREA 0.795200 ;
    PORT
      LAYER met2 ;
        RECT 547.490 561.815 547.770 565.815 ;
    END
  END c_flat[312]
  PIN c_flat[313]
    DIRECTION OUTPUT TRISTATE ;
    USE SIGNAL ;
    ANTENNADIFFAREA 0.795200 ;
    PORT
      LAYER met2 ;
        RECT 70.930 0.000 71.210 4.000 ;
    END
  END c_flat[313]
  PIN c_flat[314]
    DIRECTION OUTPUT TRISTATE ;
    USE SIGNAL ;
    ANTENNADIFFAREA 0.795200 ;
    PORT
      LAYER met3 ;
        RECT 0.000 561.040 4.000 561.640 ;
    END
  END c_flat[314]
  PIN c_flat[315]
    DIRECTION OUTPUT TRISTATE ;
    USE SIGNAL ;
    ANTENNADIFFAREA 0.795200 ;
    PORT
      LAYER met2 ;
        RECT 460.550 0.000 460.830 4.000 ;
    END
  END c_flat[315]
  PIN c_flat[316]
    DIRECTION OUTPUT TRISTATE ;
    USE SIGNAL ;
    ANTENNADIFFAREA 0.795200 ;
    PORT
      LAYER met3 ;
        RECT 0.000 414.840 4.000 415.440 ;
    END
  END c_flat[316]
  PIN c_flat[317]
    DIRECTION OUTPUT TRISTATE ;
    USE SIGNAL ;
    ANTENNADIFFAREA 0.445500 ;
    PORT
      LAYER met2 ;
        RECT 444.450 561.815 444.730 565.815 ;
    END
  END c_flat[317]
  PIN c_flat[318]
    DIRECTION OUTPUT TRISTATE ;
    USE SIGNAL ;
    ANTENNADIFFAREA 0.445500 ;
    PORT
      LAYER met3 ;
        RECT 551.095 44.240 555.095 44.840 ;
    END
  END c_flat[318]
  PIN c_flat[319]
    DIRECTION OUTPUT TRISTATE ;
    USE SIGNAL ;
    ANTENNADIFFAREA 0.795200 ;
    PORT
      LAYER met2 ;
        RECT 251.250 0.000 251.530 4.000 ;
    END
  END c_flat[319]
  PIN c_flat[31]
    DIRECTION OUTPUT TRISTATE ;
    USE SIGNAL ;
    ANTENNADIFFAREA 0.795200 ;
    PORT
      LAYER met2 ;
        RECT 180.410 561.815 180.690 565.815 ;
    END
  END c_flat[31]
  PIN c_flat[320]
    DIRECTION OUTPUT TRISTATE ;
    USE SIGNAL ;
    ANTENNADIFFAREA 0.795200 ;
    PORT
      LAYER met2 ;
        RECT 196.510 0.000 196.790 4.000 ;
    END
  END c_flat[320]
  PIN c_flat[321]
    DIRECTION OUTPUT TRISTATE ;
    USE SIGNAL ;
    ANTENNADIFFAREA 0.795200 ;
    PORT
      LAYER met2 ;
        RECT 541.050 561.815 541.330 565.815 ;
    END
  END c_flat[321]
  PIN c_flat[322]
    DIRECTION OUTPUT TRISTATE ;
    USE SIGNAL ;
    ANTENNADIFFAREA 0.445500 ;
    PORT
      LAYER met2 ;
        RECT 215.830 561.815 216.110 565.815 ;
    END
  END c_flat[322]
  PIN c_flat[323]
    DIRECTION OUTPUT TRISTATE ;
    USE SIGNAL ;
    ANTENNADIFFAREA 0.795200 ;
    PORT
      LAYER met3 ;
        RECT 0.000 210.840 4.000 211.440 ;
    END
  END c_flat[323]
  PIN c_flat[324]
    DIRECTION OUTPUT TRISTATE ;
    USE SIGNAL ;
    ANTENNADIFFAREA 0.795200 ;
    PORT
      LAYER met2 ;
        RECT 315.650 0.000 315.930 4.000 ;
    END
  END c_flat[324]
  PIN c_flat[325]
    DIRECTION OUTPUT TRISTATE ;
    USE SIGNAL ;
    ANTENNADIFFAREA 0.795200 ;
    PORT
      LAYER met2 ;
        RECT 138.550 0.000 138.830 4.000 ;
    END
  END c_flat[325]
  PIN c_flat[326]
    DIRECTION OUTPUT TRISTATE ;
    USE SIGNAL ;
    ANTENNADIFFAREA 0.795200 ;
    PORT
      LAYER met3 ;
        RECT 551.095 282.240 555.095 282.840 ;
    END
  END c_flat[326]
  PIN c_flat[327]
    DIRECTION OUTPUT TRISTATE ;
    USE SIGNAL ;
    ANTENNADIFFAREA 0.795200 ;
    PORT
      LAYER met2 ;
        RECT 264.130 0.000 264.410 4.000 ;
    END
  END c_flat[327]
  PIN c_flat[328]
    DIRECTION OUTPUT TRISTATE ;
    USE SIGNAL ;
    ANTENNADIFFAREA 0.795200 ;
    PORT
      LAYER met3 ;
        RECT 0.000 289.040 4.000 289.640 ;
    END
  END c_flat[328]
  PIN c_flat[329]
    DIRECTION OUTPUT TRISTATE ;
    USE SIGNAL ;
    ANTENNADIFFAREA 0.795200 ;
    PORT
      LAYER met2 ;
        RECT 502.410 0.000 502.690 4.000 ;
    END
  END c_flat[329]
  PIN c_flat[32]
    DIRECTION OUTPUT TRISTATE ;
    USE SIGNAL ;
    ANTENNADIFFAREA 0.795200 ;
    PORT
      LAYER met3 ;
        RECT 551.095 88.440 555.095 89.040 ;
    END
  END c_flat[32]
  PIN c_flat[330]
    DIRECTION OUTPUT TRISTATE ;
    USE SIGNAL ;
    ANTENNADIFFAREA 0.795200 ;
    PORT
      LAYER met3 ;
        RECT 551.095 61.240 555.095 61.840 ;
    END
  END c_flat[330]
  PIN c_flat[331]
    DIRECTION OUTPUT TRISTATE ;
    USE SIGNAL ;
    ANTENNADIFFAREA 0.795200 ;
    PORT
      LAYER met2 ;
        RECT 199.730 0.000 200.010 4.000 ;
    END
  END c_flat[331]
  PIN c_flat[332]
    DIRECTION OUTPUT TRISTATE ;
    USE SIGNAL ;
    ANTENNADIFFAREA 0.795200 ;
    PORT
      LAYER met2 ;
        RECT 9.750 561.815 10.030 565.815 ;
    END
  END c_flat[332]
  PIN c_flat[333]
    DIRECTION OUTPUT TRISTATE ;
    USE SIGNAL ;
    ANTENNADIFFAREA 0.795200 ;
    PORT
      LAYER met2 ;
        RECT 370.390 0.000 370.670 4.000 ;
    END
  END c_flat[333]
  PIN c_flat[334]
    DIRECTION OUTPUT TRISTATE ;
    USE SIGNAL ;
    ANTENNADIFFAREA 0.795200 ;
    PORT
      LAYER met3 ;
        RECT 551.095 523.640 555.095 524.240 ;
    END
  END c_flat[334]
  PIN c_flat[335]
    DIRECTION OUTPUT TRISTATE ;
    USE SIGNAL ;
    ANTENNADIFFAREA 0.795200 ;
    PORT
      LAYER met2 ;
        RECT 428.350 0.000 428.630 4.000 ;
    END
  END c_flat[335]
  PIN c_flat[336]
    DIRECTION OUTPUT TRISTATE ;
    USE SIGNAL ;
    ANTENNADIFFAREA 0.445500 ;
    PORT
      LAYER met3 ;
        RECT 551.095 476.040 555.095 476.640 ;
    END
  END c_flat[336]
  PIN c_flat[337]
    DIRECTION OUTPUT TRISTATE ;
    USE SIGNAL ;
    ANTENNADIFFAREA 0.795200 ;
    PORT
      LAYER met3 ;
        RECT 0.000 108.840 4.000 109.440 ;
    END
  END c_flat[337]
  PIN c_flat[338]
    DIRECTION OUTPUT TRISTATE ;
    USE SIGNAL ;
    ANTENNADIFFAREA 0.795200 ;
    PORT
      LAYER met2 ;
        RECT 528.170 0.000 528.450 4.000 ;
    END
  END c_flat[338]
  PIN c_flat[339]
    DIRECTION OUTPUT TRISTATE ;
    USE SIGNAL ;
    ANTENNADIFFAREA 0.445500 ;
    PORT
      LAYER met3 ;
        RECT 551.095 261.840 555.095 262.440 ;
    END
  END c_flat[339]
  PIN c_flat[33]
    DIRECTION OUTPUT TRISTATE ;
    USE SIGNAL ;
    ANTENNADIFFAREA 0.795200 ;
    PORT
      LAYER met2 ;
        RECT 344.630 561.815 344.910 565.815 ;
    END
  END c_flat[33]
  PIN c_flat[340]
    DIRECTION OUTPUT TRISTATE ;
    USE SIGNAL ;
    ANTENNADIFFAREA 0.795200 ;
    PORT
      LAYER met2 ;
        RECT 338.190 0.000 338.470 4.000 ;
    END
  END c_flat[340]
  PIN c_flat[341]
    DIRECTION OUTPUT TRISTATE ;
    USE SIGNAL ;
    ANTENNADIFFAREA 0.795200 ;
    PORT
      LAYER met2 ;
        RECT 331.750 561.815 332.030 565.815 ;
    END
  END c_flat[341]
  PIN c_flat[342]
    DIRECTION OUTPUT TRISTATE ;
    USE SIGNAL ;
    ANTENNADIFFAREA 0.445500 ;
    PORT
      LAYER met2 ;
        RECT 70.930 561.815 71.210 565.815 ;
    END
  END c_flat[342]
  PIN c_flat[343]
    DIRECTION OUTPUT TRISTATE ;
    USE SIGNAL ;
    ANTENNADIFFAREA 0.795200 ;
    PORT
      LAYER met2 ;
        RECT 399.370 0.000 399.650 4.000 ;
    END
  END c_flat[343]
  PIN c_flat[344]
    DIRECTION OUTPUT TRISTATE ;
    USE SIGNAL ;
    ANTENNADIFFAREA 0.795200 ;
    PORT
      LAYER met2 ;
        RECT 447.670 0.000 447.950 4.000 ;
    END
  END c_flat[344]
  PIN c_flat[345]
    DIRECTION OUTPUT TRISTATE ;
    USE SIGNAL ;
    ANTENNADIFFAREA 0.795200 ;
    PORT
      LAYER met2 ;
        RECT 173.970 561.815 174.250 565.815 ;
    END
  END c_flat[345]
  PIN c_flat[346]
    DIRECTION OUTPUT TRISTATE ;
    USE SIGNAL ;
    ANTENNADIFFAREA 0.795200 ;
    PORT
      LAYER met2 ;
        RECT 212.610 561.815 212.890 565.815 ;
    END
  END c_flat[346]
  PIN c_flat[347]
    DIRECTION OUTPUT TRISTATE ;
    USE SIGNAL ;
    ANTENNADIFFAREA 0.795200 ;
    PORT
      LAYER met3 ;
        RECT 0.000 516.840 4.000 517.440 ;
    END
  END c_flat[347]
  PIN c_flat[348]
    DIRECTION OUTPUT TRISTATE ;
    USE SIGNAL ;
    ANTENNADIFFAREA 0.795200 ;
    PORT
      LAYER met2 ;
        RECT 125.670 561.815 125.950 565.815 ;
    END
  END c_flat[348]
  PIN c_flat[349]
    DIRECTION OUTPUT TRISTATE ;
    USE SIGNAL ;
    ANTENNADIFFAREA 0.445500 ;
    PORT
      LAYER met3 ;
        RECT 551.095 139.440 555.095 140.040 ;
    END
  END c_flat[349]
  PIN c_flat[34]
    DIRECTION OUTPUT TRISTATE ;
    USE SIGNAL ;
    ANTENNADIFFAREA 0.795200 ;
    PORT
      LAYER met2 ;
        RECT 508.850 561.815 509.130 565.815 ;
    END
  END c_flat[34]
  PIN c_flat[350]
    DIRECTION OUTPUT TRISTATE ;
    USE SIGNAL ;
    ANTENNADIFFAREA 0.445500 ;
    PORT
      LAYER met2 ;
        RECT 492.750 561.815 493.030 565.815 ;
    END
  END c_flat[350]
  PIN c_flat[351]
    DIRECTION OUTPUT TRISTATE ;
    USE SIGNAL ;
    ANTENNADIFFAREA 0.795200 ;
    PORT
      LAYER met2 ;
        RECT 537.830 0.000 538.110 4.000 ;
    END
  END c_flat[351]
  PIN c_flat[352]
    DIRECTION OUTPUT TRISTATE ;
    USE SIGNAL ;
    ANTENNADIFFAREA 0.795200 ;
    PORT
      LAYER met2 ;
        RECT 241.590 0.000 241.870 4.000 ;
    END
  END c_flat[352]
  PIN c_flat[353]
    DIRECTION OUTPUT TRISTATE ;
    USE SIGNAL ;
    ANTENNADIFFAREA 0.795200 ;
    PORT
      LAYER met2 ;
        RECT 283.450 0.000 283.730 4.000 ;
    END
  END c_flat[353]
  PIN c_flat[354]
    DIRECTION OUTPUT TRISTATE ;
    USE SIGNAL ;
    ANTENNADIFFAREA 0.445500 ;
    PORT
      LAYER met3 ;
        RECT 551.095 520.240 555.095 520.840 ;
    END
  END c_flat[354]
  PIN c_flat[355]
    DIRECTION OUTPUT TRISTATE ;
    USE SIGNAL ;
    ANTENNADIFFAREA 0.795200 ;
    PORT
      LAYER met3 ;
        RECT 551.095 40.840 555.095 41.440 ;
    END
  END c_flat[355]
  PIN c_flat[356]
    DIRECTION OUTPUT TRISTATE ;
    USE SIGNAL ;
    ANTENNADIFFAREA 0.445500 ;
    PORT
      LAYER met2 ;
        RECT 22.630 561.815 22.910 565.815 ;
    END
  END c_flat[356]
  PIN c_flat[357]
    DIRECTION OUTPUT TRISTATE ;
    USE SIGNAL ;
    ANTENNADIFFAREA 0.795200 ;
    PORT
      LAYER met2 ;
        RECT 135.330 0.000 135.610 4.000 ;
    END
  END c_flat[357]
  PIN c_flat[358]
    DIRECTION OUTPUT TRISTATE ;
    USE SIGNAL ;
    ANTENNADIFFAREA 0.795200 ;
    PORT
      LAYER met2 ;
        RECT 260.910 561.815 261.190 565.815 ;
    END
  END c_flat[358]
  PIN c_flat[359]
    DIRECTION OUTPUT TRISTATE ;
    USE SIGNAL ;
    ANTENNADIFFAREA 0.795200 ;
    PORT
      LAYER met2 ;
        RECT 296.330 561.815 296.610 565.815 ;
    END
  END c_flat[359]
  PIN c_flat[35]
    DIRECTION OUTPUT TRISTATE ;
    USE SIGNAL ;
    ANTENNADIFFAREA 0.795200 ;
    PORT
      LAYER met3 ;
        RECT 0.000 139.440 4.000 140.040 ;
    END
  END c_flat[35]
  PIN c_flat[360]
    DIRECTION OUTPUT TRISTATE ;
    USE SIGNAL ;
    ANTENNADIFFAREA 0.445500 ;
    PORT
      LAYER met3 ;
        RECT 551.095 292.440 555.095 293.040 ;
    END
  END c_flat[360]
  PIN c_flat[361]
    DIRECTION OUTPUT TRISTATE ;
    USE SIGNAL ;
    ANTENNADIFFAREA 0.445500 ;
    PORT
      LAYER met2 ;
        RECT 402.590 561.815 402.870 565.815 ;
    END
  END c_flat[361]
  PIN c_flat[362]
    DIRECTION OUTPUT TRISTATE ;
    USE SIGNAL ;
    ANTENNADIFFAREA 0.795200 ;
    PORT
      LAYER met2 ;
        RECT 466.990 561.815 467.270 565.815 ;
    END
  END c_flat[362]
  PIN c_flat[363]
    DIRECTION OUTPUT TRISTATE ;
    USE SIGNAL ;
    ANTENNADIFFAREA 0.795200 ;
    PORT
      LAYER met2 ;
        RECT 212.610 0.000 212.890 4.000 ;
    END
  END c_flat[363]
  PIN c_flat[364]
    DIRECTION OUTPUT TRISTATE ;
    USE SIGNAL ;
    ANTENNADIFFAREA 0.445500 ;
    PORT
      LAYER met3 ;
        RECT 551.095 401.240 555.095 401.840 ;
    END
  END c_flat[364]
  PIN c_flat[365]
    DIRECTION OUTPUT TRISTATE ;
    USE SIGNAL ;
    ANTENNADIFFAREA 0.795200 ;
    PORT
      LAYER met2 ;
        RECT 392.930 0.000 393.210 4.000 ;
    END
  END c_flat[365]
  PIN c_flat[366]
    DIRECTION OUTPUT TRISTATE ;
    USE SIGNAL ;
    ANTENNADIFFAREA 0.795200 ;
    PORT
      LAYER met3 ;
        RECT 0.000 166.640 4.000 167.240 ;
    END
  END c_flat[366]
  PIN c_flat[367]
    DIRECTION OUTPUT TRISTATE ;
    USE SIGNAL ;
    ANTENNADIFFAREA 0.795200 ;
    PORT
      LAYER met2 ;
        RECT 99.910 0.000 100.190 4.000 ;
    END
  END c_flat[367]
  PIN c_flat[368]
    DIRECTION OUTPUT TRISTATE ;
    USE SIGNAL ;
    ANTENNADIFFAREA 0.795200 ;
    PORT
      LAYER met3 ;
        RECT 0.000 438.640 4.000 439.240 ;
    END
  END c_flat[368]
  PIN c_flat[369]
    DIRECTION OUTPUT TRISTATE ;
    USE SIGNAL ;
    ANTENNADIFFAREA 0.795200 ;
    PORT
      LAYER met2 ;
        RECT 312.430 0.000 312.710 4.000 ;
    END
  END c_flat[369]
  PIN c_flat[36]
    DIRECTION OUTPUT TRISTATE ;
    USE SIGNAL ;
    ANTENNADIFFAREA 0.795200 ;
    PORT
      LAYER met3 ;
        RECT 0.000 540.640 4.000 541.240 ;
    END
  END c_flat[36]
  PIN c_flat[370]
    DIRECTION OUTPUT TRISTATE ;
    USE SIGNAL ;
    ANTENNADIFFAREA 0.445500 ;
    PORT
      LAYER met3 ;
        RECT 551.095 506.640 555.095 507.240 ;
    END
  END c_flat[370]
  PIN c_flat[371]
    DIRECTION OUTPUT TRISTATE ;
    USE SIGNAL ;
    ANTENNADIFFAREA 0.445500 ;
    PORT
      LAYER met3 ;
        RECT 551.095 197.240 555.095 197.840 ;
    END
  END c_flat[371]
  PIN c_flat[372]
    DIRECTION OUTPUT TRISTATE ;
    USE SIGNAL ;
    ANTENNADIFFAREA 0.795200 ;
    PORT
      LAYER met3 ;
        RECT 551.095 10.240 555.095 10.840 ;
    END
  END c_flat[372]
  PIN c_flat[373]
    DIRECTION OUTPUT TRISTATE ;
    USE SIGNAL ;
    ANTENNADIFFAREA 0.795200 ;
    PORT
      LAYER met3 ;
        RECT 551.095 295.840 555.095 296.440 ;
    END
  END c_flat[373]
  PIN c_flat[374]
    DIRECTION OUTPUT TRISTATE ;
    USE SIGNAL ;
    ANTENNADIFFAREA 0.795200 ;
    PORT
      LAYER met3 ;
        RECT 0.000 401.240 4.000 401.840 ;
    END
  END c_flat[374]
  PIN c_flat[375]
    DIRECTION OUTPUT TRISTATE ;
    USE SIGNAL ;
    ANTENNADIFFAREA 0.795200 ;
    PORT
      LAYER met2 ;
        RECT 190.070 0.000 190.350 4.000 ;
    END
  END c_flat[375]
  PIN c_flat[376]
    DIRECTION OUTPUT TRISTATE ;
    USE SIGNAL ;
    ANTENNADIFFAREA 0.795200 ;
    PORT
      LAYER met2 ;
        RECT 157.870 561.815 158.150 565.815 ;
    END
  END c_flat[376]
  PIN c_flat[377]
    DIRECTION OUTPUT TRISTATE ;
    USE SIGNAL ;
    ANTENNADIFFAREA 0.795200 ;
    PORT
      LAYER met2 ;
        RECT 122.450 561.815 122.730 565.815 ;
    END
  END c_flat[377]
  PIN c_flat[378]
    DIRECTION OUTPUT TRISTATE ;
    USE SIGNAL ;
    ANTENNADIFFAREA 0.795200 ;
    PORT
      LAYER met2 ;
        RECT 138.550 561.815 138.830 565.815 ;
    END
  END c_flat[378]
  PIN c_flat[379]
    DIRECTION OUTPUT TRISTATE ;
    USE SIGNAL ;
    ANTENNADIFFAREA 0.445500 ;
    PORT
      LAYER met3 ;
        RECT 551.095 248.240 555.095 248.840 ;
    END
  END c_flat[379]
  PIN c_flat[37]
    DIRECTION OUTPUT TRISTATE ;
    USE SIGNAL ;
    ANTENNADIFFAREA 0.795200 ;
    PORT
      LAYER met3 ;
        RECT 0.000 105.440 4.000 106.040 ;
    END
  END c_flat[37]
  PIN c_flat[380]
    DIRECTION OUTPUT TRISTATE ;
    USE SIGNAL ;
    ANTENNADIFFAREA 0.795200 ;
    PORT
      LAYER met3 ;
        RECT 0.000 482.840 4.000 483.440 ;
    END
  END c_flat[380]
  PIN c_flat[381]
    DIRECTION OUTPUT TRISTATE ;
    USE SIGNAL ;
    ANTENNADIFFAREA 0.445500 ;
    PORT
      LAYER met3 ;
        RECT 551.095 363.840 555.095 364.440 ;
    END
  END c_flat[381]
  PIN c_flat[382]
    DIRECTION OUTPUT TRISTATE ;
    USE SIGNAL ;
    ANTENNADIFFAREA 0.795200 ;
    PORT
      LAYER met2 ;
        RECT 35.510 561.815 35.790 565.815 ;
    END
  END c_flat[382]
  PIN c_flat[383]
    DIRECTION OUTPUT TRISTATE ;
    USE SIGNAL ;
    ANTENNADIFFAREA 0.795200 ;
    PORT
      LAYER met3 ;
        RECT 0.000 81.640 4.000 82.240 ;
    END
  END c_flat[383]
  PIN c_flat[384]
    DIRECTION OUTPUT TRISTATE ;
    USE SIGNAL ;
    ANTENNADIFFAREA 0.795200 ;
    PORT
      LAYER met2 ;
        RECT 286.670 0.000 286.950 4.000 ;
    END
  END c_flat[384]
  PIN c_flat[385]
    DIRECTION OUTPUT TRISTATE ;
    USE SIGNAL ;
    ANTENNADIFFAREA 0.795200 ;
    PORT
      LAYER met3 ;
        RECT 0.000 448.840 4.000 449.440 ;
    END
  END c_flat[385]
  PIN c_flat[386]
    DIRECTION OUTPUT TRISTATE ;
    USE SIGNAL ;
    ANTENNADIFFAREA 0.445500 ;
    PORT
      LAYER met3 ;
        RECT 551.095 78.240 555.095 78.840 ;
    END
  END c_flat[386]
  PIN c_flat[387]
    DIRECTION OUTPUT TRISTATE ;
    USE SIGNAL ;
    ANTENNADIFFAREA 0.795200 ;
    PORT
      LAYER met2 ;
        RECT 32.290 0.000 32.570 4.000 ;
    END
  END c_flat[387]
  PIN c_flat[388]
    DIRECTION OUTPUT TRISTATE ;
    USE SIGNAL ;
    ANTENNADIFFAREA 0.795200 ;
    PORT
      LAYER met2 ;
        RECT 157.870 0.000 158.150 4.000 ;
    END
  END c_flat[388]
  PIN c_flat[389]
    DIRECTION OUTPUT TRISTATE ;
    USE SIGNAL ;
    ANTENNADIFFAREA 0.445500 ;
    PORT
      LAYER met3 ;
        RECT 551.095 64.640 555.095 65.240 ;
    END
  END c_flat[389]
  PIN c_flat[38]
    DIRECTION OUTPUT TRISTATE ;
    USE SIGNAL ;
    ANTENNADIFFAREA 0.795200 ;
    PORT
      LAYER met2 ;
        RECT 103.130 561.815 103.410 565.815 ;
    END
  END c_flat[38]
  PIN c_flat[390]
    DIRECTION OUTPUT TRISTATE ;
    USE SIGNAL ;
    ANTENNADIFFAREA 0.445500 ;
    PORT
      LAYER met3 ;
        RECT 551.095 217.640 555.095 218.240 ;
    END
  END c_flat[390]
  PIN c_flat[391]
    DIRECTION OUTPUT TRISTATE ;
    USE SIGNAL ;
    ANTENNADIFFAREA 0.795200 ;
    PORT
      LAYER met3 ;
        RECT 0.000 397.840 4.000 398.440 ;
    END
  END c_flat[391]
  PIN c_flat[392]
    DIRECTION OUTPUT TRISTATE ;
    USE SIGNAL ;
    ANTENNADIFFAREA 0.795200 ;
    PORT
      LAYER met3 ;
        RECT 0.000 350.240 4.000 350.840 ;
    END
  END c_flat[392]
  PIN c_flat[393]
    DIRECTION OUTPUT TRISTATE ;
    USE SIGNAL ;
    ANTENNADIFFAREA 0.795200 ;
    PORT
      LAYER met2 ;
        RECT 373.610 0.000 373.890 4.000 ;
    END
  END c_flat[393]
  PIN c_flat[394]
    DIRECTION OUTPUT TRISTATE ;
    USE SIGNAL ;
    ANTENNADIFFAREA 0.445500 ;
    PORT
      LAYER met2 ;
        RECT 512.070 561.815 512.350 565.815 ;
    END
  END c_flat[394]
  PIN c_flat[395]
    DIRECTION OUTPUT TRISTATE ;
    USE SIGNAL ;
    ANTENNADIFFAREA 0.795200 ;
    PORT
      LAYER met2 ;
        RECT 347.850 0.000 348.130 4.000 ;
    END
  END c_flat[395]
  PIN c_flat[396]
    DIRECTION OUTPUT TRISTATE ;
    USE SIGNAL ;
    ANTENNADIFFAREA 0.795200 ;
    PORT
      LAYER met3 ;
        RECT 0.000 312.840 4.000 313.440 ;
    END
  END c_flat[396]
  PIN c_flat[397]
    DIRECTION OUTPUT TRISTATE ;
    USE SIGNAL ;
    ANTENNADIFFAREA 0.795200 ;
    PORT
      LAYER met3 ;
        RECT 551.095 544.040 555.095 544.640 ;
    END
  END c_flat[397]
  PIN c_flat[398]
    DIRECTION OUTPUT TRISTATE ;
    USE SIGNAL ;
    ANTENNADIFFAREA 0.795200 ;
    PORT
      LAYER met2 ;
        RECT 515.290 561.815 515.570 565.815 ;
    END
  END c_flat[398]
  PIN c_flat[399]
    DIRECTION OUTPUT TRISTATE ;
    USE SIGNAL ;
    ANTENNADIFFAREA 0.795200 ;
    PORT
      LAYER met2 ;
        RECT 380.050 561.815 380.330 565.815 ;
    END
  END c_flat[399]
  PIN c_flat[39]
    DIRECTION OUTPUT TRISTATE ;
    USE SIGNAL ;
    ANTENNADIFFAREA 0.795200 ;
    PORT
      LAYER met3 ;
        RECT 0.000 156.440 4.000 157.040 ;
    END
  END c_flat[39]
  PIN c_flat[3]
    DIRECTION OUTPUT TRISTATE ;
    USE SIGNAL ;
    ANTENNADIFFAREA 0.445500 ;
    PORT
      LAYER met2 ;
        RECT 190.070 561.815 190.350 565.815 ;
    END
  END c_flat[3]
  PIN c_flat[400]
    DIRECTION OUTPUT TRISTATE ;
    USE SIGNAL ;
    ANTENNADIFFAREA 0.795200 ;
    PORT
      LAYER met2 ;
        RECT 177.190 0.000 177.470 4.000 ;
    END
  END c_flat[400]
  PIN c_flat[401]
    DIRECTION OUTPUT TRISTATE ;
    USE SIGNAL ;
    ANTENNADIFFAREA 0.445500 ;
    PORT
      LAYER met3 ;
        RECT 551.095 20.440 555.095 21.040 ;
    END
  END c_flat[401]
  PIN c_flat[402]
    DIRECTION OUTPUT TRISTATE ;
    USE SIGNAL ;
    ANTENNADIFFAREA 0.445500 ;
    PORT
      LAYER met3 ;
        RECT 551.095 163.240 555.095 163.840 ;
    END
  END c_flat[402]
  PIN c_flat[403]
    DIRECTION OUTPUT TRISTATE ;
    USE SIGNAL ;
    ANTENNADIFFAREA 0.795200 ;
    PORT
      LAYER met3 ;
        RECT 551.095 309.440 555.095 310.040 ;
    END
  END c_flat[403]
  PIN c_flat[404]
    DIRECTION OUTPUT TRISTATE ;
    USE SIGNAL ;
    ANTENNADIFFAREA 0.445500 ;
    PORT
      LAYER met2 ;
        RECT 299.550 561.815 299.830 565.815 ;
    END
  END c_flat[404]
  PIN c_flat[405]
    DIRECTION OUTPUT TRISTATE ;
    USE SIGNAL ;
    ANTENNADIFFAREA 0.795200 ;
    PORT
      LAYER met2 ;
        RECT 415.470 0.000 415.750 4.000 ;
    END
  END c_flat[405]
  PIN c_flat[406]
    DIRECTION OUTPUT TRISTATE ;
    USE SIGNAL ;
    ANTENNADIFFAREA 0.795200 ;
    PORT
      LAYER met2 ;
        RECT 41.950 561.815 42.230 565.815 ;
    END
  END c_flat[406]
  PIN c_flat[407]
    DIRECTION OUTPUT TRISTATE ;
    USE SIGNAL ;
    ANTENNADIFFAREA 0.445500 ;
    PORT
      LAYER met3 ;
        RECT 551.095 367.240 555.095 367.840 ;
    END
  END c_flat[407]
  PIN c_flat[408]
    DIRECTION OUTPUT TRISTATE ;
    USE SIGNAL ;
    ANTENNADIFFAREA 0.795200 ;
    PORT
      LAYER met2 ;
        RECT 531.390 561.815 531.670 565.815 ;
    END
  END c_flat[408]
  PIN c_flat[409]
    DIRECTION OUTPUT TRISTATE ;
    USE SIGNAL ;
    ANTENNADIFFAREA 0.445500 ;
    PORT
      LAYER met3 ;
        RECT 551.095 493.040 555.095 493.640 ;
    END
  END c_flat[409]
  PIN c_flat[40]
    DIRECTION OUTPUT TRISTATE ;
    USE SIGNAL ;
    ANTENNADIFFAREA 0.795200 ;
    PORT
      LAYER met3 ;
        RECT 0.000 533.840 4.000 534.440 ;
    END
  END c_flat[40]
  PIN c_flat[410]
    DIRECTION OUTPUT TRISTATE ;
    USE SIGNAL ;
    ANTENNADIFFAREA 0.445500 ;
    PORT
      LAYER met2 ;
        RECT 58.050 561.815 58.330 565.815 ;
    END
  END c_flat[410]
  PIN c_flat[411]
    DIRECTION OUTPUT TRISTATE ;
    USE SIGNAL ;
    ANTENNADIFFAREA 0.795200 ;
    PORT
      LAYER met3 ;
        RECT 0.000 554.240 4.000 554.840 ;
    END
  END c_flat[411]
  PIN c_flat[412]
    DIRECTION OUTPUT TRISTATE ;
    USE SIGNAL ;
    ANTENNADIFFAREA 0.795200 ;
    PORT
      LAYER met3 ;
        RECT 0.000 445.440 4.000 446.040 ;
    END
  END c_flat[412]
  PIN c_flat[413]
    DIRECTION OUTPUT TRISTATE ;
    USE SIGNAL ;
    ANTENNADIFFAREA 0.795200 ;
    PORT
      LAYER met2 ;
        RECT 96.690 0.000 96.970 4.000 ;
    END
  END c_flat[413]
  PIN c_flat[414]
    DIRECTION OUTPUT TRISTATE ;
    USE SIGNAL ;
    ANTENNADIFFAREA 0.795200 ;
    PORT
      LAYER met2 ;
        RECT 144.990 0.000 145.270 4.000 ;
    END
  END c_flat[414]
  PIN c_flat[415]
    DIRECTION OUTPUT TRISTATE ;
    USE SIGNAL ;
    ANTENNADIFFAREA 0.795200 ;
    PORT
      LAYER met2 ;
        RECT 515.290 0.000 515.570 4.000 ;
    END
  END c_flat[415]
  PIN c_flat[416]
    DIRECTION OUTPUT TRISTATE ;
    USE SIGNAL ;
    ANTENNADIFFAREA 0.795200 ;
    PORT
      LAYER met3 ;
        RECT 0.000 557.640 4.000 558.240 ;
    END
  END c_flat[416]
  PIN c_flat[417]
    DIRECTION OUTPUT TRISTATE ;
    USE SIGNAL ;
    ANTENNADIFFAREA 0.795200 ;
    PORT
      LAYER met3 ;
        RECT 0.000 54.440 4.000 55.040 ;
    END
  END c_flat[417]
  PIN c_flat[418]
    DIRECTION OUTPUT TRISTATE ;
    USE SIGNAL ;
    ANTENNADIFFAREA 0.795200 ;
    PORT
      LAYER met2 ;
        RECT 309.210 561.815 309.490 565.815 ;
    END
  END c_flat[418]
  PIN c_flat[419]
    DIRECTION OUTPUT TRISTATE ;
    USE SIGNAL ;
    ANTENNADIFFAREA 0.445500 ;
    PORT
      LAYER met2 ;
        RECT 286.670 561.815 286.950 565.815 ;
    END
  END c_flat[419]
  PIN c_flat[41]
    DIRECTION OUTPUT TRISTATE ;
    USE SIGNAL ;
    ANTENNADIFFAREA 0.795200 ;
    PORT
      LAYER met2 ;
        RECT 199.730 561.815 200.010 565.815 ;
    END
  END c_flat[41]
  PIN c_flat[420]
    DIRECTION OUTPUT TRISTATE ;
    USE SIGNAL ;
    ANTENNADIFFAREA 0.795200 ;
    PORT
      LAYER met3 ;
        RECT 0.000 197.240 4.000 197.840 ;
    END
  END c_flat[420]
  PIN c_flat[421]
    DIRECTION OUTPUT TRISTATE ;
    USE SIGNAL ;
    ANTENNADIFFAREA 0.795200 ;
    PORT
      LAYER met3 ;
        RECT 551.095 503.240 555.095 503.840 ;
    END
  END c_flat[421]
  PIN c_flat[422]
    DIRECTION OUTPUT TRISTATE ;
    USE SIGNAL ;
    ANTENNADIFFAREA 0.795200 ;
    PORT
      LAYER met3 ;
        RECT 0.000 265.240 4.000 265.840 ;
    END
  END c_flat[422]
  PIN c_flat[423]
    DIRECTION OUTPUT TRISTATE ;
    USE SIGNAL ;
    ANTENNADIFFAREA 0.445500 ;
    PORT
      LAYER met2 ;
        RECT 167.530 561.815 167.810 565.815 ;
    END
  END c_flat[423]
  PIN c_flat[424]
    DIRECTION OUTPUT TRISTATE ;
    USE SIGNAL ;
    ANTENNADIFFAREA 0.795200 ;
    PORT
      LAYER met3 ;
        RECT 0.000 85.040 4.000 85.640 ;
    END
  END c_flat[424]
  PIN c_flat[425]
    DIRECTION OUTPUT TRISTATE ;
    USE SIGNAL ;
    ANTENNADIFFAREA 0.445500 ;
    PORT
      LAYER met3 ;
        RECT 551.095 442.040 555.095 442.640 ;
    END
  END c_flat[425]
  PIN c_flat[426]
    DIRECTION OUTPUT TRISTATE ;
    USE SIGNAL ;
    ANTENNADIFFAREA 0.795200 ;
    PORT
      LAYER met3 ;
        RECT 0.000 163.240 4.000 163.840 ;
    END
  END c_flat[426]
  PIN c_flat[427]
    DIRECTION OUTPUT TRISTATE ;
    USE SIGNAL ;
    ANTENNADIFFAREA 0.795200 ;
    PORT
      LAYER met3 ;
        RECT 0.000 125.840 4.000 126.440 ;
    END
  END c_flat[427]
  PIN c_flat[428]
    DIRECTION OUTPUT TRISTATE ;
    USE SIGNAL ;
    ANTENNADIFFAREA 0.795200 ;
    PORT
      LAYER met2 ;
        RECT 470.210 561.815 470.490 565.815 ;
    END
  END c_flat[428]
  PIN c_flat[429]
    DIRECTION OUTPUT TRISTATE ;
    USE SIGNAL ;
    ANTENNADIFFAREA 0.795200 ;
    PORT
      LAYER met2 ;
        RECT 495.970 561.815 496.250 565.815 ;
    END
  END c_flat[429]
  PIN c_flat[42]
    DIRECTION OUTPUT TRISTATE ;
    USE SIGNAL ;
    ANTENNADIFFAREA 0.445500 ;
    PORT
      LAYER met2 ;
        RECT 499.190 561.815 499.470 565.815 ;
    END
  END c_flat[42]
  PIN c_flat[430]
    DIRECTION OUTPUT TRISTATE ;
    USE SIGNAL ;
    ANTENNADIFFAREA 0.795200 ;
    PORT
      LAYER met3 ;
        RECT 0.000 275.440 4.000 276.040 ;
    END
  END c_flat[430]
  PIN c_flat[431]
    DIRECTION OUTPUT TRISTATE ;
    USE SIGNAL ;
    ANTENNADIFFAREA 0.795200 ;
    PORT
      LAYER met2 ;
        RECT 315.650 561.815 315.930 565.815 ;
    END
  END c_flat[431]
  PIN c_flat[432]
    DIRECTION OUTPUT TRISTATE ;
    USE SIGNAL ;
    ANTENNADIFFAREA 0.795200 ;
    PORT
      LAYER met3 ;
        RECT 0.000 550.840 4.000 551.440 ;
    END
  END c_flat[432]
  PIN c_flat[433]
    DIRECTION OUTPUT TRISTATE ;
    USE SIGNAL ;
    ANTENNADIFFAREA 0.795200 ;
    PORT
      LAYER met2 ;
        RECT 6.530 0.000 6.810 4.000 ;
    END
  END c_flat[433]
  PIN c_flat[434]
    DIRECTION OUTPUT TRISTATE ;
    USE SIGNAL ;
    ANTENNADIFFAREA 0.795200 ;
    PORT
      LAYER met3 ;
        RECT 0.000 353.640 4.000 354.240 ;
    END
  END c_flat[434]
  PIN c_flat[435]
    DIRECTION OUTPUT TRISTATE ;
    USE SIGNAL ;
    ANTENNADIFFAREA 0.795200 ;
    PORT
      LAYER met2 ;
        RECT 325.310 0.000 325.590 4.000 ;
    END
  END c_flat[435]
  PIN c_flat[436]
    DIRECTION OUTPUT TRISTATE ;
    USE SIGNAL ;
    ANTENNADIFFAREA 0.445500 ;
    PORT
      LAYER met3 ;
        RECT 551.095 98.640 555.095 99.240 ;
    END
  END c_flat[436]
  PIN c_flat[437]
    DIRECTION OUTPUT TRISTATE ;
    USE SIGNAL ;
    ANTENNADIFFAREA 0.445500 ;
    PORT
      LAYER met2 ;
        RECT 367.170 561.815 367.450 565.815 ;
    END
  END c_flat[437]
  PIN c_flat[438]
    DIRECTION OUTPUT TRISTATE ;
    USE SIGNAL ;
    ANTENNADIFFAREA 0.445500 ;
    PORT
      LAYER met3 ;
        RECT 551.095 153.040 555.095 153.640 ;
    END
  END c_flat[438]
  PIN c_flat[439]
    DIRECTION OUTPUT TRISTATE ;
    USE SIGNAL ;
    ANTENNADIFFAREA 0.795200 ;
    PORT
      LAYER met2 ;
        RECT 6.530 561.815 6.810 565.815 ;
    END
  END c_flat[439]
  PIN c_flat[43]
    DIRECTION OUTPUT TRISTATE ;
    USE SIGNAL ;
    ANTENNADIFFAREA 0.795200 ;
    PORT
      LAYER met3 ;
        RECT 0.000 261.840 4.000 262.440 ;
    END
  END c_flat[43]
  PIN c_flat[440]
    DIRECTION OUTPUT TRISTATE ;
    USE SIGNAL ;
    ANTENNADIFFAREA 0.795200 ;
    PORT
      LAYER met3 ;
        RECT 0.000 258.440 4.000 259.040 ;
    END
  END c_flat[440]
  PIN c_flat[441]
    DIRECTION OUTPUT TRISTATE ;
    USE SIGNAL ;
    ANTENNADIFFAREA 0.795200 ;
    PORT
      LAYER met2 ;
        RECT 273.790 0.000 274.070 4.000 ;
    END
  END c_flat[441]
  PIN c_flat[442]
    DIRECTION OUTPUT TRISTATE ;
    USE SIGNAL ;
    ANTENNADIFFAREA 0.795200 ;
    PORT
      LAYER met2 ;
        RECT 302.770 561.815 303.050 565.815 ;
    END
  END c_flat[442]
  PIN c_flat[443]
    DIRECTION OUTPUT TRISTATE ;
    USE SIGNAL ;
    ANTENNADIFFAREA 0.795200 ;
    PORT
      LAYER met2 ;
        RECT 499.190 0.000 499.470 4.000 ;
    END
  END c_flat[443]
  PIN c_flat[444]
    DIRECTION OUTPUT TRISTATE ;
    USE SIGNAL ;
    ANTENNADIFFAREA 0.795200 ;
    PORT
      LAYER met2 ;
        RECT 231.930 0.000 232.210 4.000 ;
    END
  END c_flat[444]
  PIN c_flat[445]
    DIRECTION OUTPUT TRISTATE ;
    USE SIGNAL ;
    ANTENNADIFFAREA 0.795200 ;
    PORT
      LAYER met3 ;
        RECT 0.000 190.440 4.000 191.040 ;
    END
  END c_flat[445]
  PIN c_flat[446]
    DIRECTION OUTPUT TRISTATE ;
    USE SIGNAL ;
    ANTENNADIFFAREA 0.795200 ;
    PORT
      LAYER met3 ;
        RECT 0.000 231.240 4.000 231.840 ;
    END
  END c_flat[446]
  PIN c_flat[447]
    DIRECTION OUTPUT TRISTATE ;
    USE SIGNAL ;
    ANTENNADIFFAREA 0.795200 ;
    PORT
      LAYER met3 ;
        RECT 0.000 391.040 4.000 391.640 ;
    END
  END c_flat[447]
  PIN c_flat[448]
    DIRECTION OUTPUT TRISTATE ;
    USE SIGNAL ;
    ANTENNADIFFAREA 0.795200 ;
    PORT
      LAYER met2 ;
        RECT 473.430 0.000 473.710 4.000 ;
    END
  END c_flat[448]
  PIN c_flat[449]
    DIRECTION OUTPUT TRISTATE ;
    USE SIGNAL ;
    ANTENNADIFFAREA 0.795200 ;
    PORT
      LAYER met2 ;
        RECT 0.090 561.815 0.370 565.815 ;
    END
  END c_flat[449]
  PIN c_flat[44]
    DIRECTION OUTPUT TRISTATE ;
    USE SIGNAL ;
    ANTENNADIFFAREA 0.795200 ;
    PORT
      LAYER met3 ;
        RECT 551.095 54.440 555.095 55.040 ;
    END
  END c_flat[44]
  PIN c_flat[450]
    DIRECTION OUTPUT TRISTATE ;
    USE SIGNAL ;
    ANTENNADIFFAREA 0.445500 ;
    PORT
      LAYER met3 ;
        RECT 551.095 472.640 555.095 473.240 ;
    END
  END c_flat[450]
  PIN c_flat[451]
    DIRECTION OUTPUT TRISTATE ;
    USE SIGNAL ;
    ANTENNADIFFAREA 0.795200 ;
    PORT
      LAYER met2 ;
        RECT 225.490 561.815 225.770 565.815 ;
    END
  END c_flat[451]
  PIN c_flat[452]
    DIRECTION OUTPUT TRISTATE ;
    USE SIGNAL ;
    ANTENNADIFFAREA 0.795200 ;
    PORT
      LAYER met3 ;
        RECT 0.000 329.840 4.000 330.440 ;
    END
  END c_flat[452]
  PIN c_flat[453]
    DIRECTION OUTPUT TRISTATE ;
    USE SIGNAL ;
    ANTENNADIFFAREA 0.795200 ;
    PORT
      LAYER met2 ;
        RECT 466.990 0.000 467.270 4.000 ;
    END
  END c_flat[453]
  PIN c_flat[454]
    DIRECTION OUTPUT TRISTATE ;
    USE SIGNAL ;
    ANTENNADIFFAREA 0.795200 ;
    PORT
      LAYER met2 ;
        RECT 357.510 561.815 357.790 565.815 ;
    END
  END c_flat[454]
  PIN c_flat[455]
    DIRECTION OUTPUT TRISTATE ;
    USE SIGNAL ;
    ANTENNADIFFAREA 0.445500 ;
    PORT
      LAYER met3 ;
        RECT 551.095 122.440 555.095 123.040 ;
    END
  END c_flat[455]
  PIN c_flat[456]
    DIRECTION OUTPUT TRISTATE ;
    USE SIGNAL ;
    ANTENNADIFFAREA 0.795200 ;
    PORT
      LAYER met2 ;
        RECT 183.630 561.815 183.910 565.815 ;
    END
  END c_flat[456]
  PIN c_flat[457]
    DIRECTION OUTPUT TRISTATE ;
    USE SIGNAL ;
    ANTENNADIFFAREA 0.795200 ;
    PORT
      LAYER met3 ;
        RECT 551.095 3.440 555.095 4.040 ;
    END
  END c_flat[457]
  PIN c_flat[458]
    DIRECTION OUTPUT TRISTATE ;
    USE SIGNAL ;
    ANTENNADIFFAREA 0.795200 ;
    PORT
      LAYER met3 ;
        RECT 0.000 537.240 4.000 537.840 ;
    END
  END c_flat[458]
  PIN c_flat[459]
    DIRECTION OUTPUT TRISTATE ;
    USE SIGNAL ;
    ANTENNADIFFAREA 0.795200 ;
    PORT
      LAYER met2 ;
        RECT 74.150 0.000 74.430 4.000 ;
    END
  END c_flat[459]
  PIN c_flat[45]
    DIRECTION OUTPUT TRISTATE ;
    USE SIGNAL ;
    ANTENNADIFFAREA 0.445500 ;
    PORT
      LAYER met3 ;
        RECT 551.095 374.040 555.095 374.640 ;
    END
  END c_flat[45]
  PIN c_flat[460]
    DIRECTION OUTPUT TRISTATE ;
    USE SIGNAL ;
    ANTENNADIFFAREA 0.795200 ;
    PORT
      LAYER met2 ;
        RECT 341.410 0.000 341.690 4.000 ;
    END
  END c_flat[460]
  PIN c_flat[461]
    DIRECTION OUTPUT TRISTATE ;
    USE SIGNAL ;
    ANTENNADIFFAREA 0.445500 ;
    PORT
      LAYER met3 ;
        RECT 551.095 469.240 555.095 469.840 ;
    END
  END c_flat[461]
  PIN c_flat[462]
    DIRECTION OUTPUT TRISTATE ;
    USE SIGNAL ;
    ANTENNADIFFAREA 0.795200 ;
    PORT
      LAYER met2 ;
        RECT 154.650 0.000 154.930 4.000 ;
    END
  END c_flat[462]
  PIN c_flat[463]
    DIRECTION OUTPUT TRISTATE ;
    USE SIGNAL ;
    ANTENNADIFFAREA 0.445500 ;
    PORT
      LAYER met3 ;
        RECT 551.095 17.040 555.095 17.640 ;
    END
  END c_flat[463]
  PIN c_flat[464]
    DIRECTION OUTPUT TRISTATE ;
    USE SIGNAL ;
    ANTENNADIFFAREA 0.445500 ;
    PORT
      LAYER met2 ;
        RECT 16.190 561.815 16.470 565.815 ;
    END
  END c_flat[464]
  PIN c_flat[465]
    DIRECTION OUTPUT TRISTATE ;
    USE SIGNAL ;
    ANTENNADIFFAREA 0.795200 ;
    PORT
      LAYER met3 ;
        RECT 0.000 316.240 4.000 316.840 ;
    END
  END c_flat[465]
  PIN c_flat[466]
    DIRECTION OUTPUT TRISTATE ;
    USE SIGNAL ;
    ANTENNADIFFAREA 0.445500 ;
    PORT
      LAYER met3 ;
        RECT 551.095 533.840 555.095 534.440 ;
    END
  END c_flat[466]
  PIN c_flat[467]
    DIRECTION OUTPUT TRISTATE ;
    USE SIGNAL ;
    ANTENNADIFFAREA 0.795200 ;
    PORT
      LAYER met3 ;
        RECT 0.000 564.440 4.000 565.040 ;
    END
  END c_flat[467]
  PIN c_flat[468]
    DIRECTION OUTPUT TRISTATE ;
    USE SIGNAL ;
    ANTENNADIFFAREA 0.445500 ;
    PORT
      LAYER met2 ;
        RECT 51.610 561.815 51.890 565.815 ;
    END
  END c_flat[468]
  PIN c_flat[469]
    DIRECTION OUTPUT TRISTATE ;
    USE SIGNAL ;
    ANTENNADIFFAREA 0.445500 ;
    PORT
      LAYER met3 ;
        RECT 551.095 156.440 555.095 157.040 ;
    END
  END c_flat[469]
  PIN c_flat[46]
    DIRECTION OUTPUT TRISTATE ;
    USE SIGNAL ;
    ANTENNADIFFAREA 0.795200 ;
    PORT
      LAYER met3 ;
        RECT 0.000 530.440 4.000 531.040 ;
    END
  END c_flat[46]
  PIN c_flat[470]
    DIRECTION OUTPUT TRISTATE ;
    USE SIGNAL ;
    ANTENNADIFFAREA 0.445500 ;
    PORT
      LAYER met3 ;
        RECT 551.095 265.240 555.095 265.840 ;
    END
  END c_flat[470]
  PIN c_flat[471]
    DIRECTION OUTPUT TRISTATE ;
    USE SIGNAL ;
    ANTENNADIFFAREA 0.795200 ;
    PORT
      LAYER met2 ;
        RECT 254.470 561.815 254.750 565.815 ;
    END
  END c_flat[471]
  PIN c_flat[472]
    DIRECTION OUTPUT TRISTATE ;
    USE SIGNAL ;
    ANTENNADIFFAREA 0.795200 ;
    PORT
      LAYER met2 ;
        RECT 128.890 561.815 129.170 565.815 ;
    END
  END c_flat[472]
  PIN c_flat[473]
    DIRECTION OUTPUT TRISTATE ;
    USE SIGNAL ;
    ANTENNADIFFAREA 0.795200 ;
    PORT
      LAYER met3 ;
        RECT 0.000 459.040 4.000 459.640 ;
    END
  END c_flat[473]
  PIN c_flat[474]
    DIRECTION OUTPUT TRISTATE ;
    USE SIGNAL ;
    ANTENNADIFFAREA 0.795200 ;
    PORT
      LAYER met2 ;
        RECT 54.830 0.000 55.110 4.000 ;
    END
  END c_flat[474]
  PIN c_flat[475]
    DIRECTION OUTPUT TRISTATE ;
    USE SIGNAL ;
    ANTENNADIFFAREA 0.795200 ;
    PORT
      LAYER met3 ;
        RECT 0.000 248.240 4.000 248.840 ;
    END
  END c_flat[475]
  PIN c_flat[476]
    DIRECTION OUTPUT TRISTATE ;
    USE SIGNAL ;
    ANTENNADIFFAREA 0.445500 ;
    PORT
      LAYER met3 ;
        RECT 551.095 499.840 555.095 500.440 ;
    END
  END c_flat[476]
  PIN c_flat[477]
    DIRECTION OUTPUT TRISTATE ;
    USE SIGNAL ;
    ANTENNADIFFAREA 0.445500 ;
    PORT
      LAYER met3 ;
        RECT 551.095 465.840 555.095 466.440 ;
    END
  END c_flat[477]
  PIN c_flat[478]
    DIRECTION OUTPUT TRISTATE ;
    USE SIGNAL ;
    ANTENNADIFFAREA 0.795200 ;
    PORT
      LAYER met3 ;
        RECT 0.000 10.240 4.000 10.840 ;
    END
  END c_flat[478]
  PIN c_flat[479]
    DIRECTION OUTPUT TRISTATE ;
    USE SIGNAL ;
    ANTENNADIFFAREA 0.445500 ;
    PORT
      LAYER met3 ;
        RECT 551.095 414.840 555.095 415.440 ;
    END
  END c_flat[479]
  PIN c_flat[47]
    DIRECTION OUTPUT TRISTATE ;
    USE SIGNAL ;
    ANTENNADIFFAREA 0.445500 ;
    PORT
      LAYER met3 ;
        RECT 551.095 231.240 555.095 231.840 ;
    END
  END c_flat[47]
  PIN c_flat[480]
    DIRECTION OUTPUT TRISTATE ;
    USE SIGNAL ;
    ANTENNADIFFAREA 0.445500 ;
    PORT
      LAYER met3 ;
        RECT 551.095 13.640 555.095 14.240 ;
    END
  END c_flat[480]
  PIN c_flat[481]
    DIRECTION OUTPUT TRISTATE ;
    USE SIGNAL ;
    ANTENNADIFFAREA 0.445500 ;
    PORT
      LAYER met2 ;
        RECT 257.690 561.815 257.970 565.815 ;
    END
  END c_flat[481]
  PIN c_flat[482]
    DIRECTION OUTPUT TRISTATE ;
    USE SIGNAL ;
    ANTENNADIFFAREA 0.795200 ;
    PORT
      LAYER met2 ;
        RECT 428.350 561.815 428.630 565.815 ;
    END
  END c_flat[482]
  PIN c_flat[483]
    DIRECTION OUTPUT TRISTATE ;
    USE SIGNAL ;
    ANTENNADIFFAREA 0.795200 ;
    PORT
      LAYER met3 ;
        RECT 0.000 34.040 4.000 34.640 ;
    END
  END c_flat[483]
  PIN c_flat[484]
    DIRECTION OUTPUT TRISTATE ;
    USE SIGNAL ;
    ANTENNADIFFAREA 0.795200 ;
    PORT
      LAYER met2 ;
        RECT 479.870 0.000 480.150 4.000 ;
    END
  END c_flat[484]
  PIN c_flat[485]
    DIRECTION OUTPUT TRISTATE ;
    USE SIGNAL ;
    ANTENNADIFFAREA 0.445500 ;
    PORT
      LAYER met3 ;
        RECT 551.095 176.840 555.095 177.440 ;
    END
  END c_flat[485]
  PIN c_flat[486]
    DIRECTION OUTPUT TRISTATE ;
    USE SIGNAL ;
    ANTENNADIFFAREA 0.795200 ;
    PORT
      LAYER met3 ;
        RECT 0.000 520.240 4.000 520.840 ;
    END
  END c_flat[486]
  PIN c_flat[487]
    DIRECTION OUTPUT TRISTATE ;
    USE SIGNAL ;
    ANTENNADIFFAREA 0.795200 ;
    PORT
      LAYER met2 ;
        RECT 318.870 0.000 319.150 4.000 ;
    END
  END c_flat[487]
  PIN c_flat[488]
    DIRECTION OUTPUT TRISTATE ;
    USE SIGNAL ;
    ANTENNADIFFAREA 0.795200 ;
    PORT
      LAYER met2 ;
        RECT 61.270 0.000 61.550 4.000 ;
    END
  END c_flat[488]
  PIN c_flat[489]
    DIRECTION OUTPUT TRISTATE ;
    USE SIGNAL ;
    ANTENNADIFFAREA 0.445500 ;
    PORT
      LAYER met2 ;
        RECT 87.030 561.815 87.310 565.815 ;
    END
  END c_flat[489]
  PIN c_flat[48]
    DIRECTION OUTPUT TRISTATE ;
    USE SIGNAL ;
    ANTENNADIFFAREA 0.445500 ;
    PORT
      LAYER met3 ;
        RECT 551.095 391.040 555.095 391.640 ;
    END
  END c_flat[48]
  PIN c_flat[490]
    DIRECTION OUTPUT TRISTATE ;
    USE SIGNAL ;
    ANTENNADIFFAREA 0.445500 ;
    PORT
      LAYER met2 ;
        RECT 505.630 561.815 505.910 565.815 ;
    END
  END c_flat[490]
  PIN c_flat[491]
    DIRECTION OUTPUT TRISTATE ;
    USE SIGNAL ;
    ANTENNADIFFAREA 0.795200 ;
    PORT
      LAYER met2 ;
        RECT 225.490 0.000 225.770 4.000 ;
    END
  END c_flat[491]
  PIN c_flat[492]
    DIRECTION OUTPUT TRISTATE ;
    USE SIGNAL ;
    ANTENNADIFFAREA 0.795200 ;
    PORT
      LAYER met3 ;
        RECT 0.000 30.640 4.000 31.240 ;
    END
  END c_flat[492]
  PIN c_flat[493]
    DIRECTION OUTPUT TRISTATE ;
    USE SIGNAL ;
    ANTENNADIFFAREA 0.445500 ;
    PORT
      LAYER met3 ;
        RECT 551.095 289.040 555.095 289.640 ;
    END
  END c_flat[493]
  PIN c_flat[494]
    DIRECTION OUTPUT TRISTATE ;
    USE SIGNAL ;
    ANTENNADIFFAREA 0.795200 ;
    PORT
      LAYER met2 ;
        RECT 450.890 0.000 451.170 4.000 ;
    END
  END c_flat[494]
  PIN c_flat[495]
    DIRECTION OUTPUT TRISTATE ;
    USE SIGNAL ;
    ANTENNADIFFAREA 0.445500 ;
    PORT
      LAYER met2 ;
        RECT 347.850 561.815 348.130 565.815 ;
    END
  END c_flat[495]
  PIN c_flat[496]
    DIRECTION OUTPUT TRISTATE ;
    USE SIGNAL ;
    ANTENNADIFFAREA 0.795200 ;
    PORT
      LAYER met2 ;
        RECT 438.010 0.000 438.290 4.000 ;
    END
  END c_flat[496]
  PIN c_flat[497]
    DIRECTION OUTPUT TRISTATE ;
    USE SIGNAL ;
    ANTENNADIFFAREA 0.795200 ;
    PORT
      LAYER met2 ;
        RECT 183.630 0.000 183.910 4.000 ;
    END
  END c_flat[497]
  PIN c_flat[498]
    DIRECTION OUTPUT TRISTATE ;
    USE SIGNAL ;
    ANTENNADIFFAREA 0.795200 ;
    PORT
      LAYER met2 ;
        RECT 29.070 0.000 29.350 4.000 ;
    END
  END c_flat[498]
  PIN c_flat[499]
    DIRECTION OUTPUT TRISTATE ;
    USE SIGNAL ;
    ANTENNADIFFAREA 0.445500 ;
    PORT
      LAYER met3 ;
        RECT 551.095 23.840 555.095 24.440 ;
    END
  END c_flat[499]
  PIN c_flat[49]
    DIRECTION OUTPUT TRISTATE ;
    USE SIGNAL ;
    ANTENNADIFFAREA 0.795200 ;
    PORT
      LAYER met3 ;
        RECT 0.000 187.040 4.000 187.640 ;
    END
  END c_flat[49]
  PIN c_flat[4]
    DIRECTION OUTPUT TRISTATE ;
    USE SIGNAL ;
    ANTENNADIFFAREA 0.795200 ;
    PORT
      LAYER met2 ;
        RECT 96.690 561.815 96.970 565.815 ;
    END
  END c_flat[4]
  PIN c_flat[500]
    DIRECTION OUTPUT TRISTATE ;
    USE SIGNAL ;
    ANTENNADIFFAREA 0.795200 ;
    PORT
      LAYER met3 ;
        RECT 551.095 557.640 555.095 558.240 ;
    END
  END c_flat[500]
  PIN c_flat[501]
    DIRECTION OUTPUT TRISTATE ;
    USE SIGNAL ;
    ANTENNADIFFAREA 0.795200 ;
    PORT
      LAYER met3 ;
        RECT 0.000 343.440 4.000 344.040 ;
    END
  END c_flat[501]
  PIN c_flat[502]
    DIRECTION OUTPUT TRISTATE ;
    USE SIGNAL ;
    ANTENNADIFFAREA 0.795200 ;
    PORT
      LAYER met3 ;
        RECT 0.000 384.240 4.000 384.840 ;
    END
  END c_flat[502]
  PIN c_flat[503]
    DIRECTION OUTPUT TRISTATE ;
    USE SIGNAL ;
    ANTENNADIFFAREA 0.795200 ;
    PORT
      LAYER met3 ;
        RECT 0.000 370.640 4.000 371.240 ;
    END
  END c_flat[503]
  PIN c_flat[504]
    DIRECTION OUTPUT TRISTATE ;
    USE SIGNAL ;
    ANTENNADIFFAREA 0.795200 ;
    PORT
      LAYER met2 ;
        RECT 22.630 0.000 22.910 4.000 ;
    END
  END c_flat[504]
  PIN c_flat[505]
    DIRECTION OUTPUT TRISTATE ;
    USE SIGNAL ;
    ANTENNADIFFAREA 0.795200 ;
    PORT
      LAYER met2 ;
        RECT 122.450 0.000 122.730 4.000 ;
    END
  END c_flat[505]
  PIN c_flat[506]
    DIRECTION OUTPUT TRISTATE ;
    USE SIGNAL ;
    ANTENNADIFFAREA 0.795200 ;
    PORT
      LAYER met3 ;
        RECT 551.095 336.640 555.095 337.240 ;
    END
  END c_flat[506]
  PIN c_flat[507]
    DIRECTION OUTPUT TRISTATE ;
    USE SIGNAL ;
    ANTENNADIFFAREA 0.795200 ;
    PORT
      LAYER met3 ;
        RECT 0.000 40.840 4.000 41.440 ;
    END
  END c_flat[507]
  PIN c_flat[508]
    DIRECTION OUTPUT TRISTATE ;
    USE SIGNAL ;
    ANTENNADIFFAREA 0.445500 ;
    PORT
      LAYER met2 ;
        RECT 318.870 561.815 319.150 565.815 ;
    END
  END c_flat[508]
  PIN c_flat[509]
    DIRECTION OUTPUT TRISTATE ;
    USE SIGNAL ;
    ANTENNADIFFAREA 0.795200 ;
    PORT
      LAYER met2 ;
        RECT 460.550 561.815 460.830 565.815 ;
    END
  END c_flat[509]
  PIN c_flat[50]
    DIRECTION OUTPUT TRISTATE ;
    USE SIGNAL ;
    ANTENNADIFFAREA 0.795200 ;
    PORT
      LAYER met3 ;
        RECT 0.000 23.840 4.000 24.440 ;
    END
  END c_flat[50]
  PIN c_flat[510]
    DIRECTION OUTPUT TRISTATE ;
    USE SIGNAL ;
    ANTENNADIFFAREA 0.795200 ;
    PORT
      LAYER met2 ;
        RECT 90.250 0.000 90.530 4.000 ;
    END
  END c_flat[510]
  PIN c_flat[511]
    DIRECTION OUTPUT TRISTATE ;
    USE SIGNAL ;
    ANTENNADIFFAREA 0.445500 ;
    PORT
      LAYER met3 ;
        RECT 551.095 380.840 555.095 381.440 ;
    END
  END c_flat[511]
  PIN c_flat[51]
    DIRECTION OUTPUT TRISTATE ;
    USE SIGNAL ;
    ANTENNADIFFAREA 0.795200 ;
    PORT
      LAYER met2 ;
        RECT 483.090 561.815 483.370 565.815 ;
    END
  END c_flat[51]
  PIN c_flat[52]
    DIRECTION OUTPUT TRISTATE ;
    USE SIGNAL ;
    ANTENNADIFFAREA 0.795200 ;
    PORT
      LAYER met3 ;
        RECT 0.000 255.040 4.000 255.640 ;
    END
  END c_flat[52]
  PIN c_flat[53]
    DIRECTION OUTPUT TRISTATE ;
    USE SIGNAL ;
    ANTENNADIFFAREA 0.445500 ;
    PORT
      LAYER met3 ;
        RECT 551.095 482.840 555.095 483.440 ;
    END
  END c_flat[53]
  PIN c_flat[54]
    DIRECTION OUTPUT TRISTATE ;
    USE SIGNAL ;
    ANTENNADIFFAREA 0.445500 ;
    PORT
      LAYER met3 ;
        RECT 551.095 214.240 555.095 214.840 ;
    END
  END c_flat[54]
  PIN c_flat[55]
    DIRECTION OUTPUT TRISTATE ;
    USE SIGNAL ;
    ANTENNADIFFAREA 0.795200 ;
    PORT
      LAYER met3 ;
        RECT 0.000 13.640 4.000 14.240 ;
    END
  END c_flat[55]
  PIN c_flat[56]
    DIRECTION OUTPUT TRISTATE ;
    USE SIGNAL ;
    ANTENNADIFFAREA 0.795200 ;
    PORT
      LAYER met2 ;
        RECT 418.690 561.815 418.970 565.815 ;
    END
  END c_flat[56]
  PIN c_flat[57]
    DIRECTION OUTPUT TRISTATE ;
    USE SIGNAL ;
    ANTENNADIFFAREA 0.795200 ;
    PORT
      LAYER met2 ;
        RECT 80.590 561.815 80.870 565.815 ;
    END
  END c_flat[57]
  PIN c_flat[58]
    DIRECTION OUTPUT TRISTATE ;
    USE SIGNAL ;
    ANTENNADIFFAREA 0.795200 ;
    PORT
      LAYER met2 ;
        RECT 180.410 0.000 180.690 4.000 ;
    END
  END c_flat[58]
  PIN c_flat[59]
    DIRECTION OUTPUT TRISTATE ;
    USE SIGNAL ;
    ANTENNADIFFAREA 0.795200 ;
    PORT
      LAYER met3 ;
        RECT 551.095 377.440 555.095 378.040 ;
    END
  END c_flat[59]
  PIN c_flat[5]
    DIRECTION OUTPUT TRISTATE ;
    USE SIGNAL ;
    ANTENNADIFFAREA 0.795200 ;
    PORT
      LAYER met2 ;
        RECT 463.770 0.000 464.050 4.000 ;
    END
  END c_flat[5]
  PIN c_flat[60]
    DIRECTION OUTPUT TRISTATE ;
    USE SIGNAL ;
    ANTENNADIFFAREA 0.445500 ;
    PORT
      LAYER met3 ;
        RECT 551.095 190.440 555.095 191.040 ;
    END
  END c_flat[60]
  PIN c_flat[61]
    DIRECTION OUTPUT TRISTATE ;
    USE SIGNAL ;
    ANTENNADIFFAREA 0.795200 ;
    PORT
      LAYER met3 ;
        RECT 0.000 102.040 4.000 102.640 ;
    END
  END c_flat[61]
  PIN c_flat[62]
    DIRECTION OUTPUT TRISTATE ;
    USE SIGNAL ;
    ANTENNADIFFAREA 0.795200 ;
    PORT
      LAYER met3 ;
        RECT 551.095 34.040 555.095 34.640 ;
    END
  END c_flat[62]
  PIN c_flat[63]
    DIRECTION OUTPUT TRISTATE ;
    USE SIGNAL ;
    ANTENNADIFFAREA 0.795200 ;
    PORT
      LAYER met2 ;
        RECT 93.470 0.000 93.750 4.000 ;
    END
  END c_flat[63]
  PIN c_flat[64]
    DIRECTION OUTPUT TRISTATE ;
    USE SIGNAL ;
    ANTENNADIFFAREA 0.795200 ;
    PORT
      LAYER met2 ;
        RECT 277.010 0.000 277.290 4.000 ;
    END
  END c_flat[64]
  PIN c_flat[65]
    DIRECTION OUTPUT TRISTATE ;
    USE SIGNAL ;
    ANTENNADIFFAREA 0.795200 ;
    PORT
      LAYER met3 ;
        RECT 551.095 268.640 555.095 269.240 ;
    END
  END c_flat[65]
  PIN c_flat[66]
    DIRECTION OUTPUT TRISTATE ;
    USE SIGNAL ;
    ANTENNADIFFAREA 0.795200 ;
    PORT
      LAYER met2 ;
        RECT 405.810 561.815 406.090 565.815 ;
    END
  END c_flat[66]
  PIN c_flat[67]
    DIRECTION OUTPUT TRISTATE ;
    USE SIGNAL ;
    ANTENNADIFFAREA 0.445500 ;
    PORT
      LAYER met3 ;
        RECT 551.095 540.640 555.095 541.240 ;
    END
  END c_flat[67]
  PIN c_flat[68]
    DIRECTION OUTPUT TRISTATE ;
    USE SIGNAL ;
    ANTENNADIFFAREA 0.445500 ;
    PORT
      LAYER met3 ;
        RECT 551.095 37.440 555.095 38.040 ;
    END
  END c_flat[68]
  PIN c_flat[69]
    DIRECTION OUTPUT TRISTATE ;
    USE SIGNAL ;
    ANTENNADIFFAREA 0.795200 ;
    PORT
      LAYER met2 ;
        RECT 45.170 0.000 45.450 4.000 ;
    END
  END c_flat[69]
  PIN c_flat[6]
    DIRECTION OUTPUT TRISTATE ;
    USE SIGNAL ;
    ANTENNADIFFAREA 0.445500 ;
    PORT
      LAYER met3 ;
        RECT 551.095 343.440 555.095 344.040 ;
    END
  END c_flat[6]
  PIN c_flat[70]
    DIRECTION OUTPUT TRISTATE ;
    USE SIGNAL ;
    ANTENNADIFFAREA 0.795200 ;
    PORT
      LAYER met2 ;
        RECT 9.750 0.000 10.030 4.000 ;
    END
  END c_flat[70]
  PIN c_flat[71]
    DIRECTION OUTPUT TRISTATE ;
    USE SIGNAL ;
    ANTENNADIFFAREA 0.445500 ;
    PORT
      LAYER met3 ;
        RECT 551.095 547.440 555.095 548.040 ;
    END
  END c_flat[71]
  PIN c_flat[72]
    DIRECTION OUTPUT TRISTATE ;
    USE SIGNAL ;
    ANTENNADIFFAREA 0.445500 ;
    PORT
      LAYER met2 ;
        RECT 389.710 561.815 389.990 565.815 ;
    END
  END c_flat[72]
  PIN c_flat[73]
    DIRECTION OUTPUT TRISTATE ;
    USE SIGNAL ;
    ANTENNADIFFAREA 0.445500 ;
    PORT
      LAYER met3 ;
        RECT 551.095 71.440 555.095 72.040 ;
    END
  END c_flat[73]
  PIN c_flat[74]
    DIRECTION OUTPUT TRISTATE ;
    USE SIGNAL ;
    ANTENNADIFFAREA 0.795200 ;
    PORT
      LAYER met3 ;
        RECT 0.000 64.640 4.000 65.240 ;
    END
  END c_flat[74]
  PIN c_flat[75]
    DIRECTION OUTPUT TRISTATE ;
    USE SIGNAL ;
    ANTENNADIFFAREA 0.795200 ;
    PORT
      LAYER met3 ;
        RECT 0.000 115.640 4.000 116.240 ;
    END
  END c_flat[75]
  PIN c_flat[76]
    DIRECTION OUTPUT TRISTATE ;
    USE SIGNAL ;
    ANTENNADIFFAREA 0.795200 ;
    PORT
      LAYER met3 ;
        RECT 0.000 132.640 4.000 133.240 ;
    END
  END c_flat[76]
  PIN c_flat[77]
    DIRECTION OUTPUT TRISTATE ;
    USE SIGNAL ;
    ANTENNADIFFAREA 0.795200 ;
    PORT
      LAYER met2 ;
        RECT 376.830 0.000 377.110 4.000 ;
    END
  END c_flat[77]
  PIN c_flat[78]
    DIRECTION OUTPUT TRISTATE ;
    USE SIGNAL ;
    ANTENNADIFFAREA 0.795200 ;
    PORT
      LAYER met2 ;
        RECT 0.090 0.000 0.370 4.000 ;
    END
  END c_flat[78]
  PIN c_flat[79]
    DIRECTION OUTPUT TRISTATE ;
    USE SIGNAL ;
    ANTENNADIFFAREA 0.795200 ;
    PORT
      LAYER met2 ;
        RECT 441.230 0.000 441.510 4.000 ;
    END
  END c_flat[79]
  PIN c_flat[7]
    DIRECTION OUTPUT TRISTATE ;
    USE SIGNAL ;
    ANTENNADIFFAREA 0.795200 ;
    PORT
      LAYER met3 ;
        RECT 0.000 238.040 4.000 238.640 ;
    END
  END c_flat[7]
  PIN c_flat[80]
    DIRECTION OUTPUT TRISTATE ;
    USE SIGNAL ;
    ANTENNADIFFAREA 0.795200 ;
    PORT
      LAYER met3 ;
        RECT 0.000 465.840 4.000 466.440 ;
    END
  END c_flat[80]
  PIN c_flat[81]
    DIRECTION OUTPUT TRISTATE ;
    USE SIGNAL ;
    ANTENNADIFFAREA 0.445500 ;
    PORT
      LAYER met2 ;
        RECT 135.330 561.815 135.610 565.815 ;
    END
  END c_flat[81]
  PIN c_flat[82]
    DIRECTION OUTPUT TRISTATE ;
    USE SIGNAL ;
    ANTENNADIFFAREA 0.795200 ;
    PORT
      LAYER met3 ;
        RECT 0.000 153.040 4.000 153.640 ;
    END
  END c_flat[82]
  PIN c_flat[83]
    DIRECTION OUTPUT TRISTATE ;
    USE SIGNAL ;
    ANTENNADIFFAREA 0.795200 ;
    PORT
      LAYER met2 ;
        RECT 116.010 0.000 116.290 4.000 ;
    END
  END c_flat[83]
  PIN c_flat[84]
    DIRECTION OUTPUT TRISTATE ;
    USE SIGNAL ;
    ANTENNADIFFAREA 0.795200 ;
    PORT
      LAYER met2 ;
        RECT 38.730 0.000 39.010 4.000 ;
    END
  END c_flat[84]
  PIN c_flat[85]
    DIRECTION OUTPUT TRISTATE ;
    USE SIGNAL ;
    ANTENNADIFFAREA 0.795200 ;
    PORT
      LAYER met2 ;
        RECT 273.790 561.815 274.070 565.815 ;
    END
  END c_flat[85]
  PIN c_flat[86]
    DIRECTION OUTPUT TRISTATE ;
    USE SIGNAL ;
    ANTENNADIFFAREA 0.445500 ;
    PORT
      LAYER met2 ;
        RECT 148.210 561.815 148.490 565.815 ;
    END
  END c_flat[86]
  PIN c_flat[87]
    DIRECTION OUTPUT TRISTATE ;
    USE SIGNAL ;
    ANTENNADIFFAREA 0.795200 ;
    PORT
      LAYER met2 ;
        RECT 299.550 0.000 299.830 4.000 ;
    END
  END c_flat[87]
  PIN c_flat[88]
    DIRECTION OUTPUT TRISTATE ;
    USE SIGNAL ;
    ANTENNADIFFAREA 0.795200 ;
    PORT
      LAYER met2 ;
        RECT 373.610 561.815 373.890 565.815 ;
    END
  END c_flat[88]
  PIN c_flat[89]
    DIRECTION OUTPUT TRISTATE ;
    USE SIGNAL ;
    ANTENNADIFFAREA 0.445500 ;
    PORT
      LAYER met3 ;
        RECT 551.095 159.840 555.095 160.440 ;
    END
  END c_flat[89]
  PIN c_flat[8]
    DIRECTION OUTPUT TRISTATE ;
    USE SIGNAL ;
    ANTENNADIFFAREA 0.795200 ;
    PORT
      LAYER met3 ;
        RECT 0.000 357.040 4.000 357.640 ;
    END
  END c_flat[8]
  PIN c_flat[90]
    DIRECTION OUTPUT TRISTATE ;
    USE SIGNAL ;
    ANTENNADIFFAREA 0.445500 ;
    PORT
      LAYER met3 ;
        RECT 551.095 445.440 555.095 446.040 ;
    END
  END c_flat[90]
  PIN c_flat[91]
    DIRECTION OUTPUT TRISTATE ;
    USE SIGNAL ;
    ANTENNADIFFAREA 0.795200 ;
    PORT
      LAYER met2 ;
        RECT 119.230 0.000 119.510 4.000 ;
    END
  END c_flat[91]
  PIN c_flat[92]
    DIRECTION OUTPUT TRISTATE ;
    USE SIGNAL ;
    ANTENNADIFFAREA 0.795200 ;
    PORT
      LAYER met2 ;
        RECT 209.390 0.000 209.670 4.000 ;
    END
  END c_flat[92]
  PIN c_flat[93]
    DIRECTION OUTPUT TRISTATE ;
    USE SIGNAL ;
    ANTENNADIFFAREA 0.795200 ;
    PORT
      LAYER met2 ;
        RECT 331.750 0.000 332.030 4.000 ;
    END
  END c_flat[93]
  PIN c_flat[94]
    DIRECTION OUTPUT TRISTATE ;
    USE SIGNAL ;
    ANTENNADIFFAREA 0.445500 ;
    PORT
      LAYER met3 ;
        RECT 551.095 425.040 555.095 425.640 ;
    END
  END c_flat[94]
  PIN c_flat[95]
    DIRECTION OUTPUT TRISTATE ;
    USE SIGNAL ;
    ANTENNADIFFAREA 0.795200 ;
    PORT
      LAYER met2 ;
        RECT 334.970 0.000 335.250 4.000 ;
    END
  END c_flat[95]
  PIN c_flat[96]
    DIRECTION OUTPUT TRISTATE ;
    USE SIGNAL ;
    ANTENNADIFFAREA 0.445500 ;
    PORT
      LAYER met2 ;
        RECT 360.730 561.815 361.010 565.815 ;
    END
  END c_flat[96]
  PIN c_flat[97]
    DIRECTION OUTPUT TRISTATE ;
    USE SIGNAL ;
    ANTENNADIFFAREA 0.445500 ;
    PORT
      LAYER met2 ;
        RECT 354.290 561.815 354.570 565.815 ;
    END
  END c_flat[97]
  PIN c_flat[98]
    DIRECTION OUTPUT TRISTATE ;
    USE SIGNAL ;
    ANTENNADIFFAREA 0.795200 ;
    PORT
      LAYER met3 ;
        RECT 0.000 527.040 4.000 527.640 ;
    END
  END c_flat[98]
  PIN c_flat[99]
    DIRECTION OUTPUT TRISTATE ;
    USE SIGNAL ;
    ANTENNADIFFAREA 0.795200 ;
    PORT
      LAYER met2 ;
        RECT 61.270 561.815 61.550 565.815 ;
    END
  END c_flat[99]
  PIN c_flat[9]
    DIRECTION OUTPUT TRISTATE ;
    USE SIGNAL ;
    ANTENNADIFFAREA 0.795200 ;
    PORT
      LAYER met2 ;
        RECT 396.150 0.000 396.430 4.000 ;
    END
  END c_flat[9]
  PIN clk
    DIRECTION INPUT ;
    USE SIGNAL ;
    ANTENNAGATEAREA 1.286700 ;
    ANTENNADIFFAREA 0.434700 ;
    PORT
      LAYER met3 ;
        RECT 0.000 122.440 4.000 123.040 ;
    END
  END clk
  PIN en
    DIRECTION INPUT ;
    USE SIGNAL ;
    ANTENNAGATEAREA 0.647700 ;
    ANTENNADIFFAREA 0.434700 ;
    PORT
      LAYER met3 ;
        RECT 0.000 472.640 4.000 473.240 ;
    END
  END en
  PIN rst
    DIRECTION INPUT ;
    USE SIGNAL ;
    ANTENNAGATEAREA 0.682200 ;
    ANTENNADIFFAREA 0.434700 ;
    PORT
      LAYER met3 ;
        RECT 551.095 272.040 555.095 272.640 ;
    END
  END rst
  OBS
      LAYER li1 ;
        RECT 5.520 10.795 549.240 554.965 ;
      LAYER met1 ;
        RECT 0.070 9.220 554.690 557.220 ;
      LAYER met2 ;
        RECT 0.650 561.535 6.250 564.925 ;
        RECT 7.090 561.535 9.470 564.925 ;
        RECT 10.310 561.535 12.690 564.925 ;
        RECT 13.530 561.535 15.910 564.925 ;
        RECT 16.750 561.535 19.130 564.925 ;
        RECT 19.970 561.535 22.350 564.925 ;
        RECT 23.190 561.535 28.790 564.925 ;
        RECT 29.630 561.535 32.010 564.925 ;
        RECT 32.850 561.535 35.230 564.925 ;
        RECT 36.070 561.535 38.450 564.925 ;
        RECT 39.290 561.535 41.670 564.925 ;
        RECT 42.510 561.535 48.110 564.925 ;
        RECT 48.950 561.535 51.330 564.925 ;
        RECT 52.170 561.535 54.550 564.925 ;
        RECT 55.390 561.535 57.770 564.925 ;
        RECT 58.610 561.535 60.990 564.925 ;
        RECT 61.830 561.535 64.210 564.925 ;
        RECT 65.050 561.535 70.650 564.925 ;
        RECT 71.490 561.535 73.870 564.925 ;
        RECT 74.710 561.535 77.090 564.925 ;
        RECT 77.930 561.535 80.310 564.925 ;
        RECT 81.150 561.535 83.530 564.925 ;
        RECT 84.370 561.535 86.750 564.925 ;
        RECT 87.590 561.535 93.190 564.925 ;
        RECT 94.030 561.535 96.410 564.925 ;
        RECT 97.250 561.535 99.630 564.925 ;
        RECT 100.470 561.535 102.850 564.925 ;
        RECT 103.690 561.535 106.070 564.925 ;
        RECT 106.910 561.535 112.510 564.925 ;
        RECT 113.350 561.535 115.730 564.925 ;
        RECT 116.570 561.535 118.950 564.925 ;
        RECT 119.790 561.535 122.170 564.925 ;
        RECT 123.010 561.535 125.390 564.925 ;
        RECT 126.230 561.535 128.610 564.925 ;
        RECT 129.450 561.535 135.050 564.925 ;
        RECT 135.890 561.535 138.270 564.925 ;
        RECT 139.110 561.535 141.490 564.925 ;
        RECT 142.330 561.535 144.710 564.925 ;
        RECT 145.550 561.535 147.930 564.925 ;
        RECT 148.770 561.535 151.150 564.925 ;
        RECT 151.990 561.535 157.590 564.925 ;
        RECT 158.430 561.535 160.810 564.925 ;
        RECT 161.650 561.535 164.030 564.925 ;
        RECT 164.870 561.535 167.250 564.925 ;
        RECT 168.090 561.535 170.470 564.925 ;
        RECT 171.310 561.535 173.690 564.925 ;
        RECT 174.530 561.535 180.130 564.925 ;
        RECT 180.970 561.535 183.350 564.925 ;
        RECT 184.190 561.535 186.570 564.925 ;
        RECT 187.410 561.535 189.790 564.925 ;
        RECT 190.630 561.535 193.010 564.925 ;
        RECT 193.850 561.535 199.450 564.925 ;
        RECT 200.290 561.535 202.670 564.925 ;
        RECT 203.510 561.535 205.890 564.925 ;
        RECT 206.730 561.535 209.110 564.925 ;
        RECT 209.950 561.535 212.330 564.925 ;
        RECT 213.170 561.535 215.550 564.925 ;
        RECT 216.390 561.535 221.990 564.925 ;
        RECT 222.830 561.535 225.210 564.925 ;
        RECT 226.050 561.535 228.430 564.925 ;
        RECT 229.270 561.535 231.650 564.925 ;
        RECT 232.490 561.535 234.870 564.925 ;
        RECT 235.710 561.535 238.090 564.925 ;
        RECT 238.930 561.535 244.530 564.925 ;
        RECT 245.370 561.535 247.750 564.925 ;
        RECT 248.590 561.535 250.970 564.925 ;
        RECT 251.810 561.535 254.190 564.925 ;
        RECT 255.030 561.535 257.410 564.925 ;
        RECT 258.250 561.535 260.630 564.925 ;
        RECT 261.470 561.535 267.070 564.925 ;
        RECT 267.910 561.535 270.290 564.925 ;
        RECT 271.130 561.535 273.510 564.925 ;
        RECT 274.350 561.535 276.730 564.925 ;
        RECT 277.570 561.535 279.950 564.925 ;
        RECT 280.790 561.535 286.390 564.925 ;
        RECT 287.230 561.535 289.610 564.925 ;
        RECT 290.450 561.535 292.830 564.925 ;
        RECT 293.670 561.535 296.050 564.925 ;
        RECT 296.890 561.535 299.270 564.925 ;
        RECT 300.110 561.535 302.490 564.925 ;
        RECT 303.330 561.535 308.930 564.925 ;
        RECT 309.770 561.535 312.150 564.925 ;
        RECT 312.990 561.535 315.370 564.925 ;
        RECT 316.210 561.535 318.590 564.925 ;
        RECT 319.430 561.535 321.810 564.925 ;
        RECT 322.650 561.535 325.030 564.925 ;
        RECT 325.870 561.535 331.470 564.925 ;
        RECT 332.310 561.535 334.690 564.925 ;
        RECT 335.530 561.535 337.910 564.925 ;
        RECT 338.750 561.535 341.130 564.925 ;
        RECT 341.970 561.535 344.350 564.925 ;
        RECT 345.190 561.535 347.570 564.925 ;
        RECT 348.410 561.535 354.010 564.925 ;
        RECT 354.850 561.535 357.230 564.925 ;
        RECT 358.070 561.535 360.450 564.925 ;
        RECT 361.290 561.535 363.670 564.925 ;
        RECT 364.510 561.535 366.890 564.925 ;
        RECT 367.730 561.535 373.330 564.925 ;
        RECT 374.170 561.535 376.550 564.925 ;
        RECT 377.390 561.535 379.770 564.925 ;
        RECT 380.610 561.535 382.990 564.925 ;
        RECT 383.830 561.535 386.210 564.925 ;
        RECT 387.050 561.535 389.430 564.925 ;
        RECT 390.270 561.535 395.870 564.925 ;
        RECT 396.710 561.535 399.090 564.925 ;
        RECT 399.930 561.535 402.310 564.925 ;
        RECT 403.150 561.535 405.530 564.925 ;
        RECT 406.370 561.535 408.750 564.925 ;
        RECT 409.590 561.535 411.970 564.925 ;
        RECT 412.810 561.535 418.410 564.925 ;
        RECT 419.250 561.535 421.630 564.925 ;
        RECT 422.470 561.535 424.850 564.925 ;
        RECT 425.690 561.535 428.070 564.925 ;
        RECT 428.910 561.535 431.290 564.925 ;
        RECT 432.130 561.535 437.730 564.925 ;
        RECT 438.570 561.535 440.950 564.925 ;
        RECT 441.790 561.535 444.170 564.925 ;
        RECT 445.010 561.535 447.390 564.925 ;
        RECT 448.230 561.535 450.610 564.925 ;
        RECT 451.450 561.535 453.830 564.925 ;
        RECT 454.670 561.535 460.270 564.925 ;
        RECT 461.110 561.535 463.490 564.925 ;
        RECT 464.330 561.535 466.710 564.925 ;
        RECT 467.550 561.535 469.930 564.925 ;
        RECT 470.770 561.535 473.150 564.925 ;
        RECT 473.990 561.535 476.370 564.925 ;
        RECT 477.210 561.535 482.810 564.925 ;
        RECT 483.650 561.535 486.030 564.925 ;
        RECT 486.870 561.535 489.250 564.925 ;
        RECT 490.090 561.535 492.470 564.925 ;
        RECT 493.310 561.535 495.690 564.925 ;
        RECT 496.530 561.535 498.910 564.925 ;
        RECT 499.750 561.535 505.350 564.925 ;
        RECT 506.190 561.535 508.570 564.925 ;
        RECT 509.410 561.535 511.790 564.925 ;
        RECT 512.630 561.535 515.010 564.925 ;
        RECT 515.850 561.535 518.230 564.925 ;
        RECT 519.070 561.535 524.670 564.925 ;
        RECT 525.510 561.535 527.890 564.925 ;
        RECT 528.730 561.535 531.110 564.925 ;
        RECT 531.950 561.535 534.330 564.925 ;
        RECT 535.170 561.535 537.550 564.925 ;
        RECT 538.390 561.535 540.770 564.925 ;
        RECT 541.610 561.535 547.210 564.925 ;
        RECT 548.050 561.535 550.430 564.925 ;
        RECT 551.270 561.535 553.650 564.925 ;
        RECT 554.490 561.535 555.060 564.925 ;
        RECT 0.100 4.280 555.060 561.535 ;
        RECT 0.650 0.155 3.030 4.280 ;
        RECT 3.870 0.155 6.250 4.280 ;
        RECT 7.090 0.155 9.470 4.280 ;
        RECT 10.310 0.155 12.690 4.280 ;
        RECT 13.530 0.155 15.910 4.280 ;
        RECT 16.750 0.155 22.350 4.280 ;
        RECT 23.190 0.155 25.570 4.280 ;
        RECT 26.410 0.155 28.790 4.280 ;
        RECT 29.630 0.155 32.010 4.280 ;
        RECT 32.850 0.155 35.230 4.280 ;
        RECT 36.070 0.155 38.450 4.280 ;
        RECT 39.290 0.155 44.890 4.280 ;
        RECT 45.730 0.155 48.110 4.280 ;
        RECT 48.950 0.155 51.330 4.280 ;
        RECT 52.170 0.155 54.550 4.280 ;
        RECT 55.390 0.155 57.770 4.280 ;
        RECT 58.610 0.155 60.990 4.280 ;
        RECT 61.830 0.155 67.430 4.280 ;
        RECT 68.270 0.155 70.650 4.280 ;
        RECT 71.490 0.155 73.870 4.280 ;
        RECT 74.710 0.155 77.090 4.280 ;
        RECT 77.930 0.155 80.310 4.280 ;
        RECT 81.150 0.155 86.750 4.280 ;
        RECT 87.590 0.155 89.970 4.280 ;
        RECT 90.810 0.155 93.190 4.280 ;
        RECT 94.030 0.155 96.410 4.280 ;
        RECT 97.250 0.155 99.630 4.280 ;
        RECT 100.470 0.155 102.850 4.280 ;
        RECT 103.690 0.155 109.290 4.280 ;
        RECT 110.130 0.155 112.510 4.280 ;
        RECT 113.350 0.155 115.730 4.280 ;
        RECT 116.570 0.155 118.950 4.280 ;
        RECT 119.790 0.155 122.170 4.280 ;
        RECT 123.010 0.155 125.390 4.280 ;
        RECT 126.230 0.155 131.830 4.280 ;
        RECT 132.670 0.155 135.050 4.280 ;
        RECT 135.890 0.155 138.270 4.280 ;
        RECT 139.110 0.155 141.490 4.280 ;
        RECT 142.330 0.155 144.710 4.280 ;
        RECT 145.550 0.155 147.930 4.280 ;
        RECT 148.770 0.155 154.370 4.280 ;
        RECT 155.210 0.155 157.590 4.280 ;
        RECT 158.430 0.155 160.810 4.280 ;
        RECT 161.650 0.155 164.030 4.280 ;
        RECT 164.870 0.155 167.250 4.280 ;
        RECT 168.090 0.155 173.690 4.280 ;
        RECT 174.530 0.155 176.910 4.280 ;
        RECT 177.750 0.155 180.130 4.280 ;
        RECT 180.970 0.155 183.350 4.280 ;
        RECT 184.190 0.155 186.570 4.280 ;
        RECT 187.410 0.155 189.790 4.280 ;
        RECT 190.630 0.155 196.230 4.280 ;
        RECT 197.070 0.155 199.450 4.280 ;
        RECT 200.290 0.155 202.670 4.280 ;
        RECT 203.510 0.155 205.890 4.280 ;
        RECT 206.730 0.155 209.110 4.280 ;
        RECT 209.950 0.155 212.330 4.280 ;
        RECT 213.170 0.155 218.770 4.280 ;
        RECT 219.610 0.155 221.990 4.280 ;
        RECT 222.830 0.155 225.210 4.280 ;
        RECT 226.050 0.155 228.430 4.280 ;
        RECT 229.270 0.155 231.650 4.280 ;
        RECT 232.490 0.155 234.870 4.280 ;
        RECT 235.710 0.155 241.310 4.280 ;
        RECT 242.150 0.155 244.530 4.280 ;
        RECT 245.370 0.155 247.750 4.280 ;
        RECT 248.590 0.155 250.970 4.280 ;
        RECT 251.810 0.155 254.190 4.280 ;
        RECT 255.030 0.155 260.630 4.280 ;
        RECT 261.470 0.155 263.850 4.280 ;
        RECT 264.690 0.155 267.070 4.280 ;
        RECT 267.910 0.155 270.290 4.280 ;
        RECT 271.130 0.155 273.510 4.280 ;
        RECT 274.350 0.155 276.730 4.280 ;
        RECT 277.570 0.155 283.170 4.280 ;
        RECT 284.010 0.155 286.390 4.280 ;
        RECT 287.230 0.155 289.610 4.280 ;
        RECT 290.450 0.155 292.830 4.280 ;
        RECT 293.670 0.155 296.050 4.280 ;
        RECT 296.890 0.155 299.270 4.280 ;
        RECT 300.110 0.155 305.710 4.280 ;
        RECT 306.550 0.155 308.930 4.280 ;
        RECT 309.770 0.155 312.150 4.280 ;
        RECT 312.990 0.155 315.370 4.280 ;
        RECT 316.210 0.155 318.590 4.280 ;
        RECT 319.430 0.155 325.030 4.280 ;
        RECT 325.870 0.155 328.250 4.280 ;
        RECT 329.090 0.155 331.470 4.280 ;
        RECT 332.310 0.155 334.690 4.280 ;
        RECT 335.530 0.155 337.910 4.280 ;
        RECT 338.750 0.155 341.130 4.280 ;
        RECT 341.970 0.155 347.570 4.280 ;
        RECT 348.410 0.155 350.790 4.280 ;
        RECT 351.630 0.155 354.010 4.280 ;
        RECT 354.850 0.155 357.230 4.280 ;
        RECT 358.070 0.155 360.450 4.280 ;
        RECT 361.290 0.155 363.670 4.280 ;
        RECT 364.510 0.155 370.110 4.280 ;
        RECT 370.950 0.155 373.330 4.280 ;
        RECT 374.170 0.155 376.550 4.280 ;
        RECT 377.390 0.155 379.770 4.280 ;
        RECT 380.610 0.155 382.990 4.280 ;
        RECT 383.830 0.155 386.210 4.280 ;
        RECT 387.050 0.155 392.650 4.280 ;
        RECT 393.490 0.155 395.870 4.280 ;
        RECT 396.710 0.155 399.090 4.280 ;
        RECT 399.930 0.155 402.310 4.280 ;
        RECT 403.150 0.155 405.530 4.280 ;
        RECT 406.370 0.155 411.970 4.280 ;
        RECT 412.810 0.155 415.190 4.280 ;
        RECT 416.030 0.155 418.410 4.280 ;
        RECT 419.250 0.155 421.630 4.280 ;
        RECT 422.470 0.155 424.850 4.280 ;
        RECT 425.690 0.155 428.070 4.280 ;
        RECT 428.910 0.155 434.510 4.280 ;
        RECT 435.350 0.155 437.730 4.280 ;
        RECT 438.570 0.155 440.950 4.280 ;
        RECT 441.790 0.155 444.170 4.280 ;
        RECT 445.010 0.155 447.390 4.280 ;
        RECT 448.230 0.155 450.610 4.280 ;
        RECT 451.450 0.155 457.050 4.280 ;
        RECT 457.890 0.155 460.270 4.280 ;
        RECT 461.110 0.155 463.490 4.280 ;
        RECT 464.330 0.155 466.710 4.280 ;
        RECT 467.550 0.155 469.930 4.280 ;
        RECT 470.770 0.155 473.150 4.280 ;
        RECT 473.990 0.155 479.590 4.280 ;
        RECT 480.430 0.155 482.810 4.280 ;
        RECT 483.650 0.155 486.030 4.280 ;
        RECT 486.870 0.155 489.250 4.280 ;
        RECT 490.090 0.155 492.470 4.280 ;
        RECT 493.310 0.155 498.910 4.280 ;
        RECT 499.750 0.155 502.130 4.280 ;
        RECT 502.970 0.155 505.350 4.280 ;
        RECT 506.190 0.155 508.570 4.280 ;
        RECT 509.410 0.155 511.790 4.280 ;
        RECT 512.630 0.155 515.010 4.280 ;
        RECT 515.850 0.155 521.450 4.280 ;
        RECT 522.290 0.155 524.670 4.280 ;
        RECT 525.510 0.155 527.890 4.280 ;
        RECT 528.730 0.155 531.110 4.280 ;
        RECT 531.950 0.155 534.330 4.280 ;
        RECT 535.170 0.155 537.550 4.280 ;
        RECT 538.390 0.155 543.990 4.280 ;
        RECT 544.830 0.155 547.210 4.280 ;
        RECT 548.050 0.155 550.430 4.280 ;
        RECT 551.270 0.155 553.650 4.280 ;
        RECT 554.490 0.155 555.060 4.280 ;
      LAYER met3 ;
        RECT 4.400 564.040 550.695 564.905 ;
        RECT 0.270 562.040 554.695 564.040 ;
        RECT 4.400 560.640 550.695 562.040 ;
        RECT 0.270 558.640 554.695 560.640 ;
        RECT 4.400 557.240 550.695 558.640 ;
        RECT 0.270 555.240 554.695 557.240 ;
        RECT 4.400 553.840 554.695 555.240 ;
        RECT 0.270 551.840 554.695 553.840 ;
        RECT 4.400 550.440 550.695 551.840 ;
        RECT 0.270 548.440 554.695 550.440 ;
        RECT 0.270 547.040 550.695 548.440 ;
        RECT 0.270 545.040 554.695 547.040 ;
        RECT 4.400 543.640 550.695 545.040 ;
        RECT 0.270 541.640 554.695 543.640 ;
        RECT 4.400 540.240 550.695 541.640 ;
        RECT 0.270 538.240 554.695 540.240 ;
        RECT 4.400 536.840 550.695 538.240 ;
        RECT 0.270 534.840 554.695 536.840 ;
        RECT 4.400 533.440 550.695 534.840 ;
        RECT 0.270 531.440 554.695 533.440 ;
        RECT 4.400 530.040 554.695 531.440 ;
        RECT 0.270 528.040 554.695 530.040 ;
        RECT 4.400 526.640 550.695 528.040 ;
        RECT 0.270 524.640 554.695 526.640 ;
        RECT 0.270 523.240 550.695 524.640 ;
        RECT 0.270 521.240 554.695 523.240 ;
        RECT 4.400 519.840 550.695 521.240 ;
        RECT 0.270 517.840 554.695 519.840 ;
        RECT 4.400 516.440 550.695 517.840 ;
        RECT 0.270 514.440 554.695 516.440 ;
        RECT 4.400 513.040 550.695 514.440 ;
        RECT 0.270 511.040 554.695 513.040 ;
        RECT 4.400 509.640 554.695 511.040 ;
        RECT 0.270 507.640 554.695 509.640 ;
        RECT 4.400 506.240 550.695 507.640 ;
        RECT 0.270 504.240 554.695 506.240 ;
        RECT 0.270 502.840 550.695 504.240 ;
        RECT 0.270 500.840 554.695 502.840 ;
        RECT 4.400 499.440 550.695 500.840 ;
        RECT 0.270 497.440 554.695 499.440 ;
        RECT 4.400 496.040 550.695 497.440 ;
        RECT 0.270 494.040 554.695 496.040 ;
        RECT 4.400 492.640 550.695 494.040 ;
        RECT 0.270 490.640 554.695 492.640 ;
        RECT 4.400 489.240 550.695 490.640 ;
        RECT 0.270 487.240 554.695 489.240 ;
        RECT 4.400 485.840 554.695 487.240 ;
        RECT 0.270 483.840 554.695 485.840 ;
        RECT 4.400 482.440 550.695 483.840 ;
        RECT 0.270 480.440 554.695 482.440 ;
        RECT 0.270 479.040 550.695 480.440 ;
        RECT 0.270 477.040 554.695 479.040 ;
        RECT 4.400 475.640 550.695 477.040 ;
        RECT 0.270 473.640 554.695 475.640 ;
        RECT 4.400 472.240 550.695 473.640 ;
        RECT 0.270 470.240 554.695 472.240 ;
        RECT 4.400 468.840 550.695 470.240 ;
        RECT 0.270 466.840 554.695 468.840 ;
        RECT 4.400 465.440 550.695 466.840 ;
        RECT 0.270 463.440 554.695 465.440 ;
        RECT 4.400 462.040 554.695 463.440 ;
        RECT 0.270 460.040 554.695 462.040 ;
        RECT 4.400 458.640 550.695 460.040 ;
        RECT 0.270 456.640 554.695 458.640 ;
        RECT 0.270 455.240 550.695 456.640 ;
        RECT 0.270 453.240 554.695 455.240 ;
        RECT 4.400 451.840 550.695 453.240 ;
        RECT 0.270 449.840 554.695 451.840 ;
        RECT 4.400 448.440 550.695 449.840 ;
        RECT 0.270 446.440 554.695 448.440 ;
        RECT 4.400 445.040 550.695 446.440 ;
        RECT 0.270 443.040 554.695 445.040 ;
        RECT 4.400 441.640 550.695 443.040 ;
        RECT 0.270 439.640 554.695 441.640 ;
        RECT 4.400 438.240 554.695 439.640 ;
        RECT 0.270 436.240 554.695 438.240 ;
        RECT 4.400 434.840 550.695 436.240 ;
        RECT 0.270 432.840 554.695 434.840 ;
        RECT 0.270 431.440 550.695 432.840 ;
        RECT 0.270 429.440 554.695 431.440 ;
        RECT 4.400 428.040 550.695 429.440 ;
        RECT 0.270 426.040 554.695 428.040 ;
        RECT 4.400 424.640 550.695 426.040 ;
        RECT 0.270 422.640 554.695 424.640 ;
        RECT 4.400 421.240 550.695 422.640 ;
        RECT 0.270 419.240 554.695 421.240 ;
        RECT 4.400 417.840 554.695 419.240 ;
        RECT 0.270 415.840 554.695 417.840 ;
        RECT 4.400 414.440 550.695 415.840 ;
        RECT 0.270 412.440 554.695 414.440 ;
        RECT 0.270 411.040 550.695 412.440 ;
        RECT 0.270 409.040 554.695 411.040 ;
        RECT 4.400 407.640 550.695 409.040 ;
        RECT 0.270 405.640 554.695 407.640 ;
        RECT 4.400 404.240 550.695 405.640 ;
        RECT 0.270 402.240 554.695 404.240 ;
        RECT 4.400 400.840 550.695 402.240 ;
        RECT 0.270 398.840 554.695 400.840 ;
        RECT 4.400 397.440 550.695 398.840 ;
        RECT 0.270 395.440 554.695 397.440 ;
        RECT 4.400 394.040 554.695 395.440 ;
        RECT 0.270 392.040 554.695 394.040 ;
        RECT 4.400 390.640 550.695 392.040 ;
        RECT 0.270 388.640 554.695 390.640 ;
        RECT 0.270 387.240 550.695 388.640 ;
        RECT 0.270 385.240 554.695 387.240 ;
        RECT 4.400 383.840 550.695 385.240 ;
        RECT 0.270 381.840 554.695 383.840 ;
        RECT 4.400 380.440 550.695 381.840 ;
        RECT 0.270 378.440 554.695 380.440 ;
        RECT 4.400 377.040 550.695 378.440 ;
        RECT 0.270 375.040 554.695 377.040 ;
        RECT 4.400 373.640 550.695 375.040 ;
        RECT 0.270 371.640 554.695 373.640 ;
        RECT 4.400 370.240 554.695 371.640 ;
        RECT 0.270 368.240 554.695 370.240 ;
        RECT 4.400 366.840 550.695 368.240 ;
        RECT 0.270 364.840 554.695 366.840 ;
        RECT 0.270 363.440 550.695 364.840 ;
        RECT 0.270 361.440 554.695 363.440 ;
        RECT 4.400 360.040 550.695 361.440 ;
        RECT 0.270 358.040 554.695 360.040 ;
        RECT 4.400 356.640 550.695 358.040 ;
        RECT 0.270 354.640 554.695 356.640 ;
        RECT 4.400 353.240 550.695 354.640 ;
        RECT 0.270 351.240 554.695 353.240 ;
        RECT 4.400 349.840 554.695 351.240 ;
        RECT 0.270 347.840 554.695 349.840 ;
        RECT 4.400 346.440 550.695 347.840 ;
        RECT 0.270 344.440 554.695 346.440 ;
        RECT 4.400 343.040 550.695 344.440 ;
        RECT 0.270 341.040 554.695 343.040 ;
        RECT 0.270 339.640 550.695 341.040 ;
        RECT 0.270 337.640 554.695 339.640 ;
        RECT 4.400 336.240 550.695 337.640 ;
        RECT 0.270 334.240 554.695 336.240 ;
        RECT 4.400 332.840 550.695 334.240 ;
        RECT 0.270 330.840 554.695 332.840 ;
        RECT 4.400 329.440 550.695 330.840 ;
        RECT 0.270 327.440 554.695 329.440 ;
        RECT 4.400 326.040 554.695 327.440 ;
        RECT 0.270 324.040 554.695 326.040 ;
        RECT 4.400 322.640 550.695 324.040 ;
        RECT 0.270 320.640 554.695 322.640 ;
        RECT 0.270 319.240 550.695 320.640 ;
        RECT 0.270 317.240 554.695 319.240 ;
        RECT 4.400 315.840 550.695 317.240 ;
        RECT 0.270 313.840 554.695 315.840 ;
        RECT 4.400 312.440 550.695 313.840 ;
        RECT 0.270 310.440 554.695 312.440 ;
        RECT 4.400 309.040 550.695 310.440 ;
        RECT 0.270 307.040 554.695 309.040 ;
        RECT 4.400 305.640 550.695 307.040 ;
        RECT 0.270 303.640 554.695 305.640 ;
        RECT 4.400 302.240 554.695 303.640 ;
        RECT 0.270 300.240 554.695 302.240 ;
        RECT 4.400 298.840 550.695 300.240 ;
        RECT 0.270 296.840 554.695 298.840 ;
        RECT 0.270 295.440 550.695 296.840 ;
        RECT 0.270 293.440 554.695 295.440 ;
        RECT 4.400 292.040 550.695 293.440 ;
        RECT 0.270 290.040 554.695 292.040 ;
        RECT 4.400 288.640 550.695 290.040 ;
        RECT 0.270 286.640 554.695 288.640 ;
        RECT 4.400 285.240 550.695 286.640 ;
        RECT 0.270 283.240 554.695 285.240 ;
        RECT 4.400 281.840 550.695 283.240 ;
        RECT 0.270 279.840 554.695 281.840 ;
        RECT 4.400 278.440 554.695 279.840 ;
        RECT 0.270 276.440 554.695 278.440 ;
        RECT 4.400 275.040 550.695 276.440 ;
        RECT 0.270 273.040 554.695 275.040 ;
        RECT 0.270 271.640 550.695 273.040 ;
        RECT 0.270 269.640 554.695 271.640 ;
        RECT 4.400 268.240 550.695 269.640 ;
        RECT 0.270 266.240 554.695 268.240 ;
        RECT 4.400 264.840 550.695 266.240 ;
        RECT 0.270 262.840 554.695 264.840 ;
        RECT 4.400 261.440 550.695 262.840 ;
        RECT 0.270 259.440 554.695 261.440 ;
        RECT 4.400 258.040 554.695 259.440 ;
        RECT 0.270 256.040 554.695 258.040 ;
        RECT 4.400 254.640 550.695 256.040 ;
        RECT 0.270 252.640 554.695 254.640 ;
        RECT 0.270 251.240 550.695 252.640 ;
        RECT 0.270 249.240 554.695 251.240 ;
        RECT 4.400 247.840 550.695 249.240 ;
        RECT 0.270 245.840 554.695 247.840 ;
        RECT 4.400 244.440 550.695 245.840 ;
        RECT 0.270 242.440 554.695 244.440 ;
        RECT 4.400 241.040 550.695 242.440 ;
        RECT 0.270 239.040 554.695 241.040 ;
        RECT 4.400 237.640 550.695 239.040 ;
        RECT 0.270 235.640 554.695 237.640 ;
        RECT 4.400 234.240 554.695 235.640 ;
        RECT 0.270 232.240 554.695 234.240 ;
        RECT 4.400 230.840 550.695 232.240 ;
        RECT 0.270 228.840 554.695 230.840 ;
        RECT 0.270 227.440 550.695 228.840 ;
        RECT 0.270 225.440 554.695 227.440 ;
        RECT 4.400 224.040 550.695 225.440 ;
        RECT 0.270 222.040 554.695 224.040 ;
        RECT 4.400 220.640 550.695 222.040 ;
        RECT 0.270 218.640 554.695 220.640 ;
        RECT 4.400 217.240 550.695 218.640 ;
        RECT 0.270 215.240 554.695 217.240 ;
        RECT 4.400 213.840 550.695 215.240 ;
        RECT 0.270 211.840 554.695 213.840 ;
        RECT 4.400 210.440 554.695 211.840 ;
        RECT 0.270 208.440 554.695 210.440 ;
        RECT 4.400 207.040 550.695 208.440 ;
        RECT 0.270 205.040 554.695 207.040 ;
        RECT 0.270 203.640 550.695 205.040 ;
        RECT 0.270 201.640 554.695 203.640 ;
        RECT 4.400 200.240 550.695 201.640 ;
        RECT 0.270 198.240 554.695 200.240 ;
        RECT 4.400 196.840 550.695 198.240 ;
        RECT 0.270 194.840 554.695 196.840 ;
        RECT 4.400 193.440 550.695 194.840 ;
        RECT 0.270 191.440 554.695 193.440 ;
        RECT 4.400 190.040 550.695 191.440 ;
        RECT 0.270 188.040 554.695 190.040 ;
        RECT 4.400 186.640 554.695 188.040 ;
        RECT 0.270 184.640 554.695 186.640 ;
        RECT 4.400 183.240 550.695 184.640 ;
        RECT 0.270 181.240 554.695 183.240 ;
        RECT 0.270 179.840 550.695 181.240 ;
        RECT 0.270 177.840 554.695 179.840 ;
        RECT 4.400 176.440 550.695 177.840 ;
        RECT 0.270 174.440 554.695 176.440 ;
        RECT 4.400 173.040 550.695 174.440 ;
        RECT 0.270 171.040 554.695 173.040 ;
        RECT 4.400 169.640 550.695 171.040 ;
        RECT 0.270 167.640 554.695 169.640 ;
        RECT 4.400 166.240 554.695 167.640 ;
        RECT 0.270 164.240 554.695 166.240 ;
        RECT 4.400 162.840 550.695 164.240 ;
        RECT 0.270 160.840 554.695 162.840 ;
        RECT 0.270 159.440 550.695 160.840 ;
        RECT 0.270 157.440 554.695 159.440 ;
        RECT 4.400 156.040 550.695 157.440 ;
        RECT 0.270 154.040 554.695 156.040 ;
        RECT 4.400 152.640 550.695 154.040 ;
        RECT 0.270 150.640 554.695 152.640 ;
        RECT 4.400 149.240 550.695 150.640 ;
        RECT 0.270 147.240 554.695 149.240 ;
        RECT 4.400 145.840 550.695 147.240 ;
        RECT 0.270 143.840 554.695 145.840 ;
        RECT 4.400 142.440 554.695 143.840 ;
        RECT 0.270 140.440 554.695 142.440 ;
        RECT 4.400 139.040 550.695 140.440 ;
        RECT 0.270 137.040 554.695 139.040 ;
        RECT 0.270 135.640 550.695 137.040 ;
        RECT 0.270 133.640 554.695 135.640 ;
        RECT 4.400 132.240 550.695 133.640 ;
        RECT 0.270 130.240 554.695 132.240 ;
        RECT 4.400 128.840 550.695 130.240 ;
        RECT 0.270 126.840 554.695 128.840 ;
        RECT 4.400 125.440 550.695 126.840 ;
        RECT 0.270 123.440 554.695 125.440 ;
        RECT 4.400 122.040 550.695 123.440 ;
        RECT 0.270 120.040 554.695 122.040 ;
        RECT 4.400 118.640 554.695 120.040 ;
        RECT 0.270 116.640 554.695 118.640 ;
        RECT 4.400 115.240 550.695 116.640 ;
        RECT 0.270 113.240 554.695 115.240 ;
        RECT 0.270 111.840 550.695 113.240 ;
        RECT 0.270 109.840 554.695 111.840 ;
        RECT 4.400 108.440 550.695 109.840 ;
        RECT 0.270 106.440 554.695 108.440 ;
        RECT 4.400 105.040 550.695 106.440 ;
        RECT 0.270 103.040 554.695 105.040 ;
        RECT 4.400 101.640 550.695 103.040 ;
        RECT 0.270 99.640 554.695 101.640 ;
        RECT 4.400 98.240 550.695 99.640 ;
        RECT 0.270 96.240 554.695 98.240 ;
        RECT 4.400 94.840 554.695 96.240 ;
        RECT 0.270 92.840 554.695 94.840 ;
        RECT 4.400 91.440 550.695 92.840 ;
        RECT 0.270 89.440 554.695 91.440 ;
        RECT 0.270 88.040 550.695 89.440 ;
        RECT 0.270 86.040 554.695 88.040 ;
        RECT 4.400 84.640 550.695 86.040 ;
        RECT 0.270 82.640 554.695 84.640 ;
        RECT 4.400 81.240 550.695 82.640 ;
        RECT 0.270 79.240 554.695 81.240 ;
        RECT 4.400 77.840 550.695 79.240 ;
        RECT 0.270 75.840 554.695 77.840 ;
        RECT 4.400 74.440 554.695 75.840 ;
        RECT 0.270 72.440 554.695 74.440 ;
        RECT 4.400 71.040 550.695 72.440 ;
        RECT 0.270 69.040 554.695 71.040 ;
        RECT 0.270 67.640 550.695 69.040 ;
        RECT 0.270 65.640 554.695 67.640 ;
        RECT 4.400 64.240 550.695 65.640 ;
        RECT 0.270 62.240 554.695 64.240 ;
        RECT 4.400 60.840 550.695 62.240 ;
        RECT 0.270 58.840 554.695 60.840 ;
        RECT 4.400 57.440 550.695 58.840 ;
        RECT 0.270 55.440 554.695 57.440 ;
        RECT 4.400 54.040 550.695 55.440 ;
        RECT 0.270 52.040 554.695 54.040 ;
        RECT 4.400 50.640 554.695 52.040 ;
        RECT 0.270 48.640 554.695 50.640 ;
        RECT 4.400 47.240 550.695 48.640 ;
        RECT 0.270 45.240 554.695 47.240 ;
        RECT 0.270 43.840 550.695 45.240 ;
        RECT 0.270 41.840 554.695 43.840 ;
        RECT 4.400 40.440 550.695 41.840 ;
        RECT 0.270 38.440 554.695 40.440 ;
        RECT 4.400 37.040 550.695 38.440 ;
        RECT 0.270 35.040 554.695 37.040 ;
        RECT 4.400 33.640 550.695 35.040 ;
        RECT 0.270 31.640 554.695 33.640 ;
        RECT 4.400 30.240 550.695 31.640 ;
        RECT 0.270 28.240 554.695 30.240 ;
        RECT 4.400 26.840 554.695 28.240 ;
        RECT 0.270 24.840 554.695 26.840 ;
        RECT 4.400 23.440 550.695 24.840 ;
        RECT 0.270 21.440 554.695 23.440 ;
        RECT 0.270 20.040 550.695 21.440 ;
        RECT 0.270 18.040 554.695 20.040 ;
        RECT 4.400 16.640 550.695 18.040 ;
        RECT 0.270 14.640 554.695 16.640 ;
        RECT 4.400 13.240 550.695 14.640 ;
        RECT 0.270 11.240 554.695 13.240 ;
        RECT 4.400 9.840 550.695 11.240 ;
        RECT 0.270 7.840 554.695 9.840 ;
        RECT 4.400 6.440 554.695 7.840 ;
        RECT 0.270 4.440 554.695 6.440 ;
        RECT 4.400 3.040 550.695 4.440 ;
        RECT 0.270 1.040 554.695 3.040 ;
        RECT 0.270 0.175 550.695 1.040 ;
      LAYER met4 ;
        RECT 0.295 555.520 545.690 558.105 ;
        RECT 0.295 10.240 20.640 555.520 ;
        RECT 23.040 10.240 23.940 555.520 ;
        RECT 26.340 10.240 174.240 555.520 ;
        RECT 176.640 10.240 177.540 555.520 ;
        RECT 179.940 10.240 327.840 555.520 ;
        RECT 330.240 10.240 331.140 555.520 ;
        RECT 333.540 10.240 481.440 555.520 ;
        RECT 483.840 10.240 484.740 555.520 ;
        RECT 487.140 10.240 545.690 555.520 ;
        RECT 0.295 6.975 545.690 10.240 ;
      LAYER met5 ;
        RECT 2.420 494.030 545.900 532.900 ;
        RECT 2.420 485.930 3.680 494.030 ;
        RECT 2.420 340.430 545.900 485.930 ;
        RECT 2.420 332.330 3.680 340.430 ;
        RECT 2.420 186.830 545.900 332.330 ;
        RECT 2.420 178.730 3.680 186.830 ;
        RECT 2.420 33.230 545.900 178.730 ;
        RECT 2.420 25.130 3.680 33.230 ;
        RECT 2.420 11.100 545.900 25.130 ;
  END
END systolic_array
END LIBRARY

